VERSION 5.8 ;
BUSBITCHARS "[]" ;
DIVIDERCHAR "/" ;
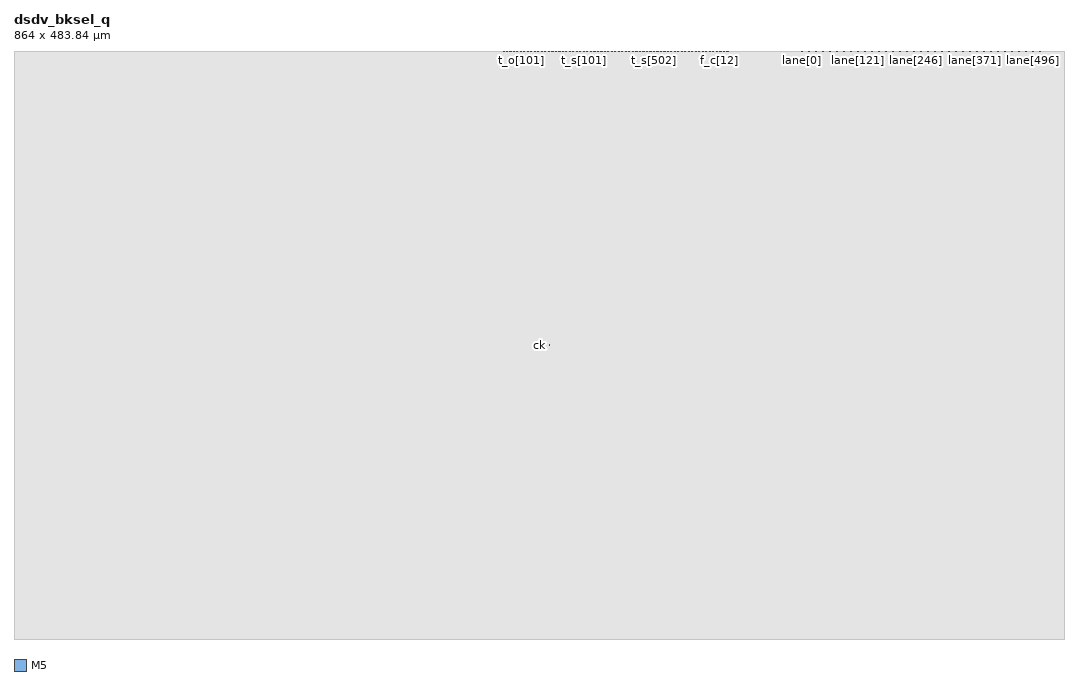
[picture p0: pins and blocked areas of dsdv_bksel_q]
MACRO dsdv_bksel_q
  CLASS BLOCK ;
  ORIGIN 0 0 ;
  SIZE 864.0 BY 483.84 ;
  PIN t_o[0]
    DIRECTION OUTPUT ;
    USE SIGNAL ;
    PORT
      LAYER M5 ;
        RECT 403.200 483.608 403.248 483.808 ;
    END
  END t_o[0]
  PIN t_o[1]
    DIRECTION OUTPUT ;
    USE SIGNAL ;
    PORT
      LAYER M5 ;
        RECT 403.344 483.608 403.392 483.808 ;
    END
  END t_o[1]
  PIN t_o[2]
    DIRECTION OUTPUT ;
    USE SIGNAL ;
    PORT
      LAYER M5 ;
        RECT 403.488 483.608 403.536 483.808 ;
    END
  END t_o[2]
  PIN t_o[3]
    DIRECTION OUTPUT ;
    USE SIGNAL ;
    PORT
      LAYER M5 ;
        RECT 403.632 483.608 403.680 483.808 ;
    END
  END t_o[3]
  PIN t_o[4]
    DIRECTION OUTPUT ;
    USE SIGNAL ;
    PORT
      LAYER M5 ;
        RECT 403.776 483.608 403.824 483.808 ;
    END
  END t_o[4]
  PIN t_o[5]
    DIRECTION OUTPUT ;
    USE SIGNAL ;
    PORT
      LAYER M5 ;
        RECT 403.920 483.608 403.968 483.808 ;
    END
  END t_o[5]
  PIN t_o[6]
    DIRECTION OUTPUT ;
    USE SIGNAL ;
    PORT
      LAYER M5 ;
        RECT 404.064 483.608 404.112 483.808 ;
    END
  END t_o[6]
  PIN t_o[7]
    DIRECTION OUTPUT ;
    USE SIGNAL ;
    PORT
      LAYER M5 ;
        RECT 404.208 483.608 404.256 483.808 ;
    END
  END t_o[7]
  PIN t_o[8]
    DIRECTION OUTPUT ;
    USE SIGNAL ;
    PORT
      LAYER M5 ;
        RECT 404.352 483.608 404.400 483.808 ;
    END
  END t_o[8]
  PIN t_o[9]
    DIRECTION OUTPUT ;
    USE SIGNAL ;
    PORT
      LAYER M5 ;
        RECT 404.496 483.608 404.544 483.808 ;
    END
  END t_o[9]
  PIN t_o[10]
    DIRECTION OUTPUT ;
    USE SIGNAL ;
    PORT
      LAYER M5 ;
        RECT 404.640 483.608 404.688 483.808 ;
    END
  END t_o[10]
  PIN t_o[11]
    DIRECTION OUTPUT ;
    USE SIGNAL ;
    PORT
      LAYER M5 ;
        RECT 404.784 483.608 404.832 483.808 ;
    END
  END t_o[11]
  PIN t_o[12]
    DIRECTION OUTPUT ;
    USE SIGNAL ;
    PORT
      LAYER M5 ;
        RECT 404.928 483.608 404.976 483.808 ;
    END
  END t_o[12]
  PIN t_o[13]
    DIRECTION OUTPUT ;
    USE SIGNAL ;
    PORT
      LAYER M5 ;
        RECT 405.072 483.608 405.120 483.808 ;
    END
  END t_o[13]
  PIN t_o[14]
    DIRECTION OUTPUT ;
    USE SIGNAL ;
    PORT
      LAYER M5 ;
        RECT 405.216 483.608 405.264 483.808 ;
    END
  END t_o[14]
  PIN t_o[15]
    DIRECTION OUTPUT ;
    USE SIGNAL ;
    PORT
      LAYER M5 ;
        RECT 405.360 483.608 405.408 483.808 ;
    END
  END t_o[15]
  PIN t_o[16]
    DIRECTION OUTPUT ;
    USE SIGNAL ;
    PORT
      LAYER M5 ;
        RECT 405.504 483.608 405.552 483.808 ;
    END
  END t_o[16]
  PIN t_o[17]
    DIRECTION OUTPUT ;
    USE SIGNAL ;
    PORT
      LAYER M5 ;
        RECT 405.648 483.608 405.696 483.808 ;
    END
  END t_o[17]
  PIN t_o[18]
    DIRECTION OUTPUT ;
    USE SIGNAL ;
    PORT
      LAYER M5 ;
        RECT 405.792 483.608 405.840 483.808 ;
    END
  END t_o[18]
  PIN t_o[19]
    DIRECTION OUTPUT ;
    USE SIGNAL ;
    PORT
      LAYER M5 ;
        RECT 405.936 483.608 405.984 483.808 ;
    END
  END t_o[19]
  PIN t_o[20]
    DIRECTION OUTPUT ;
    USE SIGNAL ;
    PORT
      LAYER M5 ;
        RECT 406.080 483.608 406.128 483.808 ;
    END
  END t_o[20]
  PIN t_o[21]
    DIRECTION OUTPUT ;
    USE SIGNAL ;
    PORT
      LAYER M5 ;
        RECT 406.224 483.608 406.272 483.808 ;
    END
  END t_o[21]
  PIN t_o[22]
    DIRECTION OUTPUT ;
    USE SIGNAL ;
    PORT
      LAYER M5 ;
        RECT 406.368 483.608 406.416 483.808 ;
    END
  END t_o[22]
  PIN t_o[23]
    DIRECTION OUTPUT ;
    USE SIGNAL ;
    PORT
      LAYER M5 ;
        RECT 406.512 483.608 406.560 483.808 ;
    END
  END t_o[23]
  PIN t_o[24]
    DIRECTION OUTPUT ;
    USE SIGNAL ;
    PORT
      LAYER M5 ;
        RECT 406.656 483.608 406.704 483.808 ;
    END
  END t_o[24]
  PIN t_o[25]
    DIRECTION OUTPUT ;
    USE SIGNAL ;
    PORT
      LAYER M5 ;
        RECT 406.800 483.608 406.848 483.808 ;
    END
  END t_o[25]
  PIN t_o[26]
    DIRECTION OUTPUT ;
    USE SIGNAL ;
    PORT
      LAYER M5 ;
        RECT 406.944 483.608 406.992 483.808 ;
    END
  END t_o[26]
  PIN t_o[27]
    DIRECTION OUTPUT ;
    USE SIGNAL ;
    PORT
      LAYER M5 ;
        RECT 407.088 483.608 407.136 483.808 ;
    END
  END t_o[27]
  PIN t_o[28]
    DIRECTION OUTPUT ;
    USE SIGNAL ;
    PORT
      LAYER M5 ;
        RECT 407.232 483.608 407.280 483.808 ;
    END
  END t_o[28]
  PIN t_o[29]
    DIRECTION OUTPUT ;
    USE SIGNAL ;
    PORT
      LAYER M5 ;
        RECT 407.376 483.608 407.424 483.808 ;
    END
  END t_o[29]
  PIN t_o[30]
    DIRECTION OUTPUT ;
    USE SIGNAL ;
    PORT
      LAYER M5 ;
        RECT 407.520 483.608 407.568 483.808 ;
    END
  END t_o[30]
  PIN t_o[31]
    DIRECTION OUTPUT ;
    USE SIGNAL ;
    PORT
      LAYER M5 ;
        RECT 407.664 483.608 407.712 483.808 ;
    END
  END t_o[31]
  PIN t_o[32]
    DIRECTION OUTPUT ;
    USE SIGNAL ;
    PORT
      LAYER M5 ;
        RECT 407.808 483.608 407.856 483.808 ;
    END
  END t_o[32]
  PIN t_o[33]
    DIRECTION OUTPUT ;
    USE SIGNAL ;
    PORT
      LAYER M5 ;
        RECT 407.952 483.608 408.000 483.808 ;
    END
  END t_o[33]
  PIN t_o[34]
    DIRECTION OUTPUT ;
    USE SIGNAL ;
    PORT
      LAYER M5 ;
        RECT 408.096 483.608 408.144 483.808 ;
    END
  END t_o[34]
  PIN t_o[35]
    DIRECTION OUTPUT ;
    USE SIGNAL ;
    PORT
      LAYER M5 ;
        RECT 408.240 483.608 408.288 483.808 ;
    END
  END t_o[35]
  PIN t_o[36]
    DIRECTION OUTPUT ;
    USE SIGNAL ;
    PORT
      LAYER M5 ;
        RECT 408.384 483.608 408.432 483.808 ;
    END
  END t_o[36]
  PIN t_o[37]
    DIRECTION OUTPUT ;
    USE SIGNAL ;
    PORT
      LAYER M5 ;
        RECT 408.528 483.608 408.576 483.808 ;
    END
  END t_o[37]
  PIN t_o[38]
    DIRECTION OUTPUT ;
    USE SIGNAL ;
    PORT
      LAYER M5 ;
        RECT 408.672 483.608 408.720 483.808 ;
    END
  END t_o[38]
  PIN t_o[39]
    DIRECTION OUTPUT ;
    USE SIGNAL ;
    PORT
      LAYER M5 ;
        RECT 408.816 483.608 408.864 483.808 ;
    END
  END t_o[39]
  PIN t_o[40]
    DIRECTION OUTPUT ;
    USE SIGNAL ;
    PORT
      LAYER M5 ;
        RECT 408.960 483.608 409.008 483.808 ;
    END
  END t_o[40]
  PIN t_o[41]
    DIRECTION OUTPUT ;
    USE SIGNAL ;
    PORT
      LAYER M5 ;
        RECT 409.104 483.608 409.152 483.808 ;
    END
  END t_o[41]
  PIN t_o[42]
    DIRECTION OUTPUT ;
    USE SIGNAL ;
    PORT
      LAYER M5 ;
        RECT 409.248 483.608 409.296 483.808 ;
    END
  END t_o[42]
  PIN t_o[43]
    DIRECTION OUTPUT ;
    USE SIGNAL ;
    PORT
      LAYER M5 ;
        RECT 409.392 483.608 409.440 483.808 ;
    END
  END t_o[43]
  PIN t_o[44]
    DIRECTION OUTPUT ;
    USE SIGNAL ;
    PORT
      LAYER M5 ;
        RECT 409.536 483.608 409.584 483.808 ;
    END
  END t_o[44]
  PIN t_o[45]
    DIRECTION OUTPUT ;
    USE SIGNAL ;
    PORT
      LAYER M5 ;
        RECT 409.680 483.608 409.728 483.808 ;
    END
  END t_o[45]
  PIN t_o[46]
    DIRECTION OUTPUT ;
    USE SIGNAL ;
    PORT
      LAYER M5 ;
        RECT 409.824 483.608 409.872 483.808 ;
    END
  END t_o[46]
  PIN t_o[47]
    DIRECTION OUTPUT ;
    USE SIGNAL ;
    PORT
      LAYER M5 ;
        RECT 409.968 483.608 410.016 483.808 ;
    END
  END t_o[47]
  PIN t_o[48]
    DIRECTION OUTPUT ;
    USE SIGNAL ;
    PORT
      LAYER M5 ;
        RECT 410.112 483.608 410.160 483.808 ;
    END
  END t_o[48]
  PIN t_o[49]
    DIRECTION OUTPUT ;
    USE SIGNAL ;
    PORT
      LAYER M5 ;
        RECT 410.256 483.608 410.304 483.808 ;
    END
  END t_o[49]
  PIN t_o[50]
    DIRECTION OUTPUT ;
    USE SIGNAL ;
    PORT
      LAYER M5 ;
        RECT 410.400 483.608 410.448 483.808 ;
    END
  END t_o[50]
  PIN t_o[51]
    DIRECTION OUTPUT ;
    USE SIGNAL ;
    PORT
      LAYER M5 ;
        RECT 410.544 483.608 410.592 483.808 ;
    END
  END t_o[51]
  PIN t_o[52]
    DIRECTION OUTPUT ;
    USE SIGNAL ;
    PORT
      LAYER M5 ;
        RECT 410.688 483.608 410.736 483.808 ;
    END
  END t_o[52]
  PIN t_o[53]
    DIRECTION OUTPUT ;
    USE SIGNAL ;
    PORT
      LAYER M5 ;
        RECT 410.832 483.608 410.880 483.808 ;
    END
  END t_o[53]
  PIN t_o[54]
    DIRECTION OUTPUT ;
    USE SIGNAL ;
    PORT
      LAYER M5 ;
        RECT 410.976 483.608 411.024 483.808 ;
    END
  END t_o[54]
  PIN t_o[55]
    DIRECTION OUTPUT ;
    USE SIGNAL ;
    PORT
      LAYER M5 ;
        RECT 411.120 483.608 411.168 483.808 ;
    END
  END t_o[55]
  PIN t_o[56]
    DIRECTION OUTPUT ;
    USE SIGNAL ;
    PORT
      LAYER M5 ;
        RECT 411.264 483.608 411.312 483.808 ;
    END
  END t_o[56]
  PIN t_o[57]
    DIRECTION OUTPUT ;
    USE SIGNAL ;
    PORT
      LAYER M5 ;
        RECT 411.408 483.608 411.456 483.808 ;
    END
  END t_o[57]
  PIN t_o[58]
    DIRECTION OUTPUT ;
    USE SIGNAL ;
    PORT
      LAYER M5 ;
        RECT 411.552 483.608 411.600 483.808 ;
    END
  END t_o[58]
  PIN t_o[59]
    DIRECTION OUTPUT ;
    USE SIGNAL ;
    PORT
      LAYER M5 ;
        RECT 411.696 483.608 411.744 483.808 ;
    END
  END t_o[59]
  PIN t_o[60]
    DIRECTION OUTPUT ;
    USE SIGNAL ;
    PORT
      LAYER M5 ;
        RECT 411.840 483.608 411.888 483.808 ;
    END
  END t_o[60]
  PIN t_o[61]
    DIRECTION OUTPUT ;
    USE SIGNAL ;
    PORT
      LAYER M5 ;
        RECT 411.984 483.608 412.032 483.808 ;
    END
  END t_o[61]
  PIN t_o[62]
    DIRECTION OUTPUT ;
    USE SIGNAL ;
    PORT
      LAYER M5 ;
        RECT 412.128 483.608 412.176 483.808 ;
    END
  END t_o[62]
  PIN t_o[63]
    DIRECTION OUTPUT ;
    USE SIGNAL ;
    PORT
      LAYER M5 ;
        RECT 412.272 483.608 412.320 483.808 ;
    END
  END t_o[63]
  PIN t_o[64]
    DIRECTION OUTPUT ;
    USE SIGNAL ;
    PORT
      LAYER M5 ;
        RECT 412.416 483.608 412.464 483.808 ;
    END
  END t_o[64]
  PIN t_o[65]
    DIRECTION OUTPUT ;
    USE SIGNAL ;
    PORT
      LAYER M5 ;
        RECT 412.560 483.608 412.608 483.808 ;
    END
  END t_o[65]
  PIN t_o[66]
    DIRECTION OUTPUT ;
    USE SIGNAL ;
    PORT
      LAYER M5 ;
        RECT 412.704 483.608 412.752 483.808 ;
    END
  END t_o[66]
  PIN t_o[67]
    DIRECTION OUTPUT ;
    USE SIGNAL ;
    PORT
      LAYER M5 ;
        RECT 412.848 483.608 412.896 483.808 ;
    END
  END t_o[67]
  PIN t_o[68]
    DIRECTION OUTPUT ;
    USE SIGNAL ;
    PORT
      LAYER M5 ;
        RECT 412.992 483.608 413.040 483.808 ;
    END
  END t_o[68]
  PIN t_o[69]
    DIRECTION OUTPUT ;
    USE SIGNAL ;
    PORT
      LAYER M5 ;
        RECT 413.136 483.608 413.184 483.808 ;
    END
  END t_o[69]
  PIN t_o[70]
    DIRECTION OUTPUT ;
    USE SIGNAL ;
    PORT
      LAYER M5 ;
        RECT 413.280 483.608 413.328 483.808 ;
    END
  END t_o[70]
  PIN t_o[71]
    DIRECTION OUTPUT ;
    USE SIGNAL ;
    PORT
      LAYER M5 ;
        RECT 413.424 483.608 413.472 483.808 ;
    END
  END t_o[71]
  PIN t_o[72]
    DIRECTION OUTPUT ;
    USE SIGNAL ;
    PORT
      LAYER M5 ;
        RECT 413.568 483.608 413.616 483.808 ;
    END
  END t_o[72]
  PIN t_o[73]
    DIRECTION OUTPUT ;
    USE SIGNAL ;
    PORT
      LAYER M5 ;
        RECT 413.712 483.608 413.760 483.808 ;
    END
  END t_o[73]
  PIN t_o[74]
    DIRECTION OUTPUT ;
    USE SIGNAL ;
    PORT
      LAYER M5 ;
        RECT 413.856 483.608 413.904 483.808 ;
    END
  END t_o[74]
  PIN t_o[75]
    DIRECTION OUTPUT ;
    USE SIGNAL ;
    PORT
      LAYER M5 ;
        RECT 414.000 483.608 414.048 483.808 ;
    END
  END t_o[75]
  PIN t_o[76]
    DIRECTION OUTPUT ;
    USE SIGNAL ;
    PORT
      LAYER M5 ;
        RECT 414.144 483.608 414.192 483.808 ;
    END
  END t_o[76]
  PIN t_o[77]
    DIRECTION OUTPUT ;
    USE SIGNAL ;
    PORT
      LAYER M5 ;
        RECT 414.288 483.608 414.336 483.808 ;
    END
  END t_o[77]
  PIN t_o[78]
    DIRECTION OUTPUT ;
    USE SIGNAL ;
    PORT
      LAYER M5 ;
        RECT 414.432 483.608 414.480 483.808 ;
    END
  END t_o[78]
  PIN t_o[79]
    DIRECTION OUTPUT ;
    USE SIGNAL ;
    PORT
      LAYER M5 ;
        RECT 414.576 483.608 414.624 483.808 ;
    END
  END t_o[79]
  PIN t_o[80]
    DIRECTION OUTPUT ;
    USE SIGNAL ;
    PORT
      LAYER M5 ;
        RECT 414.720 483.608 414.768 483.808 ;
    END
  END t_o[80]
  PIN t_o[81]
    DIRECTION OUTPUT ;
    USE SIGNAL ;
    PORT
      LAYER M5 ;
        RECT 414.864 483.608 414.912 483.808 ;
    END
  END t_o[81]
  PIN t_o[82]
    DIRECTION OUTPUT ;
    USE SIGNAL ;
    PORT
      LAYER M5 ;
        RECT 415.008 483.608 415.056 483.808 ;
    END
  END t_o[82]
  PIN t_o[83]
    DIRECTION OUTPUT ;
    USE SIGNAL ;
    PORT
      LAYER M5 ;
        RECT 415.152 483.608 415.200 483.808 ;
    END
  END t_o[83]
  PIN t_o[84]
    DIRECTION OUTPUT ;
    USE SIGNAL ;
    PORT
      LAYER M5 ;
        RECT 415.296 483.608 415.344 483.808 ;
    END
  END t_o[84]
  PIN t_o[85]
    DIRECTION OUTPUT ;
    USE SIGNAL ;
    PORT
      LAYER M5 ;
        RECT 415.440 483.608 415.488 483.808 ;
    END
  END t_o[85]
  PIN t_o[86]
    DIRECTION OUTPUT ;
    USE SIGNAL ;
    PORT
      LAYER M5 ;
        RECT 415.584 483.608 415.632 483.808 ;
    END
  END t_o[86]
  PIN t_o[87]
    DIRECTION OUTPUT ;
    USE SIGNAL ;
    PORT
      LAYER M5 ;
        RECT 415.728 483.608 415.776 483.808 ;
    END
  END t_o[87]
  PIN t_o[88]
    DIRECTION OUTPUT ;
    USE SIGNAL ;
    PORT
      LAYER M5 ;
        RECT 415.872 483.608 415.920 483.808 ;
    END
  END t_o[88]
  PIN t_o[89]
    DIRECTION OUTPUT ;
    USE SIGNAL ;
    PORT
      LAYER M5 ;
        RECT 416.016 483.608 416.064 483.808 ;
    END
  END t_o[89]
  PIN t_o[90]
    DIRECTION OUTPUT ;
    USE SIGNAL ;
    PORT
      LAYER M5 ;
        RECT 416.160 483.608 416.208 483.808 ;
    END
  END t_o[90]
  PIN t_o[91]
    DIRECTION OUTPUT ;
    USE SIGNAL ;
    PORT
      LAYER M5 ;
        RECT 416.304 483.608 416.352 483.808 ;
    END
  END t_o[91]
  PIN t_o[92]
    DIRECTION OUTPUT ;
    USE SIGNAL ;
    PORT
      LAYER M5 ;
        RECT 416.448 483.608 416.496 483.808 ;
    END
  END t_o[92]
  PIN t_o[93]
    DIRECTION OUTPUT ;
    USE SIGNAL ;
    PORT
      LAYER M5 ;
        RECT 416.592 483.608 416.640 483.808 ;
    END
  END t_o[93]
  PIN t_o[94]
    DIRECTION OUTPUT ;
    USE SIGNAL ;
    PORT
      LAYER M5 ;
        RECT 416.736 483.608 416.784 483.808 ;
    END
  END t_o[94]
  PIN t_o[95]
    DIRECTION OUTPUT ;
    USE SIGNAL ;
    PORT
      LAYER M5 ;
        RECT 416.880 483.608 416.928 483.808 ;
    END
  END t_o[95]
  PIN t_o[96]
    DIRECTION OUTPUT ;
    USE SIGNAL ;
    PORT
      LAYER M5 ;
        RECT 417.024 483.608 417.072 483.808 ;
    END
  END t_o[96]
  PIN t_o[97]
    DIRECTION OUTPUT ;
    USE SIGNAL ;
    PORT
      LAYER M5 ;
        RECT 417.168 483.608 417.216 483.808 ;
    END
  END t_o[97]
  PIN t_o[98]
    DIRECTION OUTPUT ;
    USE SIGNAL ;
    PORT
      LAYER M5 ;
        RECT 417.312 483.608 417.360 483.808 ;
    END
  END t_o[98]
  PIN t_o[99]
    DIRECTION OUTPUT ;
    USE SIGNAL ;
    PORT
      LAYER M5 ;
        RECT 417.456 483.608 417.504 483.808 ;
    END
  END t_o[99]
  PIN t_o[100]
    DIRECTION OUTPUT ;
    USE SIGNAL ;
    PORT
      LAYER M5 ;
        RECT 417.600 483.608 417.648 483.808 ;
    END
  END t_o[100]
  PIN t_o[101]
    DIRECTION OUTPUT ;
    USE SIGNAL ;
    PORT
      LAYER M5 ;
        RECT 417.744 483.608 417.792 483.808 ;
    END
  END t_o[101]
  PIN t_o[102]
    DIRECTION OUTPUT ;
    USE SIGNAL ;
    PORT
      LAYER M5 ;
        RECT 417.888 483.608 417.936 483.808 ;
    END
  END t_o[102]
  PIN t_o[103]
    DIRECTION OUTPUT ;
    USE SIGNAL ;
    PORT
      LAYER M5 ;
        RECT 418.032 483.608 418.080 483.808 ;
    END
  END t_o[103]
  PIN t_o[104]
    DIRECTION OUTPUT ;
    USE SIGNAL ;
    PORT
      LAYER M5 ;
        RECT 418.176 483.608 418.224 483.808 ;
    END
  END t_o[104]
  PIN t_o[105]
    DIRECTION OUTPUT ;
    USE SIGNAL ;
    PORT
      LAYER M5 ;
        RECT 418.320 483.608 418.368 483.808 ;
    END
  END t_o[105]
  PIN t_o[106]
    DIRECTION OUTPUT ;
    USE SIGNAL ;
    PORT
      LAYER M5 ;
        RECT 418.464 483.608 418.512 483.808 ;
    END
  END t_o[106]
  PIN t_o[107]
    DIRECTION OUTPUT ;
    USE SIGNAL ;
    PORT
      LAYER M5 ;
        RECT 418.608 483.608 418.656 483.808 ;
    END
  END t_o[107]
  PIN t_o[108]
    DIRECTION OUTPUT ;
    USE SIGNAL ;
    PORT
      LAYER M5 ;
        RECT 418.752 483.608 418.800 483.808 ;
    END
  END t_o[108]
  PIN t_o[109]
    DIRECTION OUTPUT ;
    USE SIGNAL ;
    PORT
      LAYER M5 ;
        RECT 418.896 483.608 418.944 483.808 ;
    END
  END t_o[109]
  PIN t_o[110]
    DIRECTION OUTPUT ;
    USE SIGNAL ;
    PORT
      LAYER M5 ;
        RECT 419.040 483.608 419.088 483.808 ;
    END
  END t_o[110]
  PIN t_o[111]
    DIRECTION OUTPUT ;
    USE SIGNAL ;
    PORT
      LAYER M5 ;
        RECT 419.184 483.608 419.232 483.808 ;
    END
  END t_o[111]
  PIN t_o[112]
    DIRECTION OUTPUT ;
    USE SIGNAL ;
    PORT
      LAYER M5 ;
        RECT 419.328 483.608 419.376 483.808 ;
    END
  END t_o[112]
  PIN t_o[113]
    DIRECTION OUTPUT ;
    USE SIGNAL ;
    PORT
      LAYER M5 ;
        RECT 419.472 483.608 419.520 483.808 ;
    END
  END t_o[113]
  PIN t_o[114]
    DIRECTION OUTPUT ;
    USE SIGNAL ;
    PORT
      LAYER M5 ;
        RECT 419.616 483.608 419.664 483.808 ;
    END
  END t_o[114]
  PIN t_o[115]
    DIRECTION OUTPUT ;
    USE SIGNAL ;
    PORT
      LAYER M5 ;
        RECT 419.760 483.608 419.808 483.808 ;
    END
  END t_o[115]
  PIN t_o[116]
    DIRECTION OUTPUT ;
    USE SIGNAL ;
    PORT
      LAYER M5 ;
        RECT 419.904 483.608 419.952 483.808 ;
    END
  END t_o[116]
  PIN t_o[117]
    DIRECTION OUTPUT ;
    USE SIGNAL ;
    PORT
      LAYER M5 ;
        RECT 420.048 483.608 420.096 483.808 ;
    END
  END t_o[117]
  PIN t_o[118]
    DIRECTION OUTPUT ;
    USE SIGNAL ;
    PORT
      LAYER M5 ;
        RECT 420.192 483.608 420.240 483.808 ;
    END
  END t_o[118]
  PIN t_o[119]
    DIRECTION OUTPUT ;
    USE SIGNAL ;
    PORT
      LAYER M5 ;
        RECT 420.336 483.608 420.384 483.808 ;
    END
  END t_o[119]
  PIN t_o[120]
    DIRECTION OUTPUT ;
    USE SIGNAL ;
    PORT
      LAYER M5 ;
        RECT 420.480 483.608 420.528 483.808 ;
    END
  END t_o[120]
  PIN t_o[121]
    DIRECTION OUTPUT ;
    USE SIGNAL ;
    PORT
      LAYER M5 ;
        RECT 420.624 483.608 420.672 483.808 ;
    END
  END t_o[121]
  PIN t_o[122]
    DIRECTION OUTPUT ;
    USE SIGNAL ;
    PORT
      LAYER M5 ;
        RECT 420.768 483.608 420.816 483.808 ;
    END
  END t_o[122]
  PIN t_o[123]
    DIRECTION OUTPUT ;
    USE SIGNAL ;
    PORT
      LAYER M5 ;
        RECT 420.912 483.608 420.960 483.808 ;
    END
  END t_o[123]
  PIN t_o[124]
    DIRECTION OUTPUT ;
    USE SIGNAL ;
    PORT
      LAYER M5 ;
        RECT 421.056 483.608 421.104 483.808 ;
    END
  END t_o[124]
  PIN t_o[125]
    DIRECTION OUTPUT ;
    USE SIGNAL ;
    PORT
      LAYER M5 ;
        RECT 421.200 483.608 421.248 483.808 ;
    END
  END t_o[125]
  PIN t_o[126]
    DIRECTION OUTPUT ;
    USE SIGNAL ;
    PORT
      LAYER M5 ;
        RECT 421.344 483.608 421.392 483.808 ;
    END
  END t_o[126]
  PIN t_o[127]
    DIRECTION OUTPUT ;
    USE SIGNAL ;
    PORT
      LAYER M5 ;
        RECT 421.488 483.608 421.536 483.808 ;
    END
  END t_o[127]
  PIN t_o[128]
    DIRECTION OUTPUT ;
    USE SIGNAL ;
    PORT
      LAYER M5 ;
        RECT 421.632 483.608 421.680 483.808 ;
    END
  END t_o[128]
  PIN t_o[129]
    DIRECTION OUTPUT ;
    USE SIGNAL ;
    PORT
      LAYER M5 ;
        RECT 421.776 483.608 421.824 483.808 ;
    END
  END t_o[129]
  PIN t_o[130]
    DIRECTION OUTPUT ;
    USE SIGNAL ;
    PORT
      LAYER M5 ;
        RECT 421.920 483.608 421.968 483.808 ;
    END
  END t_o[130]
  PIN t_o[131]
    DIRECTION OUTPUT ;
    USE SIGNAL ;
    PORT
      LAYER M5 ;
        RECT 422.064 483.608 422.112 483.808 ;
    END
  END t_o[131]
  PIN t_o[132]
    DIRECTION OUTPUT ;
    USE SIGNAL ;
    PORT
      LAYER M5 ;
        RECT 422.208 483.608 422.256 483.808 ;
    END
  END t_o[132]
  PIN t_o[133]
    DIRECTION OUTPUT ;
    USE SIGNAL ;
    PORT
      LAYER M5 ;
        RECT 422.352 483.608 422.400 483.808 ;
    END
  END t_o[133]
  PIN t_o[134]
    DIRECTION OUTPUT ;
    USE SIGNAL ;
    PORT
      LAYER M5 ;
        RECT 422.496 483.608 422.544 483.808 ;
    END
  END t_o[134]
  PIN t_o[135]
    DIRECTION OUTPUT ;
    USE SIGNAL ;
    PORT
      LAYER M5 ;
        RECT 422.640 483.608 422.688 483.808 ;
    END
  END t_o[135]
  PIN t_o[136]
    DIRECTION OUTPUT ;
    USE SIGNAL ;
    PORT
      LAYER M5 ;
        RECT 422.784 483.608 422.832 483.808 ;
    END
  END t_o[136]
  PIN t_o[137]
    DIRECTION OUTPUT ;
    USE SIGNAL ;
    PORT
      LAYER M5 ;
        RECT 422.928 483.608 422.976 483.808 ;
    END
  END t_o[137]
  PIN t_o[138]
    DIRECTION OUTPUT ;
    USE SIGNAL ;
    PORT
      LAYER M5 ;
        RECT 423.072 483.608 423.120 483.808 ;
    END
  END t_o[138]
  PIN t_o[139]
    DIRECTION OUTPUT ;
    USE SIGNAL ;
    PORT
      LAYER M5 ;
        RECT 423.216 483.608 423.264 483.808 ;
    END
  END t_o[139]
  PIN t_o[140]
    DIRECTION OUTPUT ;
    USE SIGNAL ;
    PORT
      LAYER M5 ;
        RECT 423.360 483.608 423.408 483.808 ;
    END
  END t_o[140]
  PIN t_o[141]
    DIRECTION OUTPUT ;
    USE SIGNAL ;
    PORT
      LAYER M5 ;
        RECT 423.504 483.608 423.552 483.808 ;
    END
  END t_o[141]
  PIN t_o[142]
    DIRECTION OUTPUT ;
    USE SIGNAL ;
    PORT
      LAYER M5 ;
        RECT 423.648 483.608 423.696 483.808 ;
    END
  END t_o[142]
  PIN t_o[143]
    DIRECTION OUTPUT ;
    USE SIGNAL ;
    PORT
      LAYER M5 ;
        RECT 423.792 483.608 423.840 483.808 ;
    END
  END t_o[143]
  PIN t_o[144]
    DIRECTION OUTPUT ;
    USE SIGNAL ;
    PORT
      LAYER M5 ;
        RECT 423.936 483.608 423.984 483.808 ;
    END
  END t_o[144]
  PIN t_o[145]
    DIRECTION OUTPUT ;
    USE SIGNAL ;
    PORT
      LAYER M5 ;
        RECT 424.080 483.608 424.128 483.808 ;
    END
  END t_o[145]
  PIN t_o[146]
    DIRECTION OUTPUT ;
    USE SIGNAL ;
    PORT
      LAYER M5 ;
        RECT 424.224 483.608 424.272 483.808 ;
    END
  END t_o[146]
  PIN t_o[147]
    DIRECTION OUTPUT ;
    USE SIGNAL ;
    PORT
      LAYER M5 ;
        RECT 424.368 483.608 424.416 483.808 ;
    END
  END t_o[147]
  PIN t_o[148]
    DIRECTION OUTPUT ;
    USE SIGNAL ;
    PORT
      LAYER M5 ;
        RECT 424.512 483.608 424.560 483.808 ;
    END
  END t_o[148]
  PIN t_o[149]
    DIRECTION OUTPUT ;
    USE SIGNAL ;
    PORT
      LAYER M5 ;
        RECT 424.656 483.608 424.704 483.808 ;
    END
  END t_o[149]
  PIN t_o[150]
    DIRECTION OUTPUT ;
    USE SIGNAL ;
    PORT
      LAYER M5 ;
        RECT 424.800 483.608 424.848 483.808 ;
    END
  END t_o[150]
  PIN t_o[151]
    DIRECTION OUTPUT ;
    USE SIGNAL ;
    PORT
      LAYER M5 ;
        RECT 424.944 483.608 424.992 483.808 ;
    END
  END t_o[151]
  PIN t_o[152]
    DIRECTION OUTPUT ;
    USE SIGNAL ;
    PORT
      LAYER M5 ;
        RECT 425.088 483.608 425.136 483.808 ;
    END
  END t_o[152]
  PIN t_o[153]
    DIRECTION OUTPUT ;
    USE SIGNAL ;
    PORT
      LAYER M5 ;
        RECT 425.232 483.608 425.280 483.808 ;
    END
  END t_o[153]
  PIN t_o[154]
    DIRECTION OUTPUT ;
    USE SIGNAL ;
    PORT
      LAYER M5 ;
        RECT 425.376 483.608 425.424 483.808 ;
    END
  END t_o[154]
  PIN t_o[155]
    DIRECTION OUTPUT ;
    USE SIGNAL ;
    PORT
      LAYER M5 ;
        RECT 425.520 483.608 425.568 483.808 ;
    END
  END t_o[155]
  PIN t_o[156]
    DIRECTION OUTPUT ;
    USE SIGNAL ;
    PORT
      LAYER M5 ;
        RECT 425.664 483.608 425.712 483.808 ;
    END
  END t_o[156]
  PIN t_o[157]
    DIRECTION OUTPUT ;
    USE SIGNAL ;
    PORT
      LAYER M5 ;
        RECT 425.808 483.608 425.856 483.808 ;
    END
  END t_o[157]
  PIN t_o[158]
    DIRECTION OUTPUT ;
    USE SIGNAL ;
    PORT
      LAYER M5 ;
        RECT 425.952 483.608 426.000 483.808 ;
    END
  END t_o[158]
  PIN t_o[159]
    DIRECTION OUTPUT ;
    USE SIGNAL ;
    PORT
      LAYER M5 ;
        RECT 426.096 483.608 426.144 483.808 ;
    END
  END t_o[159]
  PIN t_o[160]
    DIRECTION OUTPUT ;
    USE SIGNAL ;
    PORT
      LAYER M5 ;
        RECT 426.240 483.608 426.288 483.808 ;
    END
  END t_o[160]
  PIN t_o[161]
    DIRECTION OUTPUT ;
    USE SIGNAL ;
    PORT
      LAYER M5 ;
        RECT 426.384 483.608 426.432 483.808 ;
    END
  END t_o[161]
  PIN t_o[162]
    DIRECTION OUTPUT ;
    USE SIGNAL ;
    PORT
      LAYER M5 ;
        RECT 426.528 483.608 426.576 483.808 ;
    END
  END t_o[162]
  PIN t_o[163]
    DIRECTION OUTPUT ;
    USE SIGNAL ;
    PORT
      LAYER M5 ;
        RECT 426.672 483.608 426.720 483.808 ;
    END
  END t_o[163]
  PIN t_o[164]
    DIRECTION OUTPUT ;
    USE SIGNAL ;
    PORT
      LAYER M5 ;
        RECT 426.816 483.608 426.864 483.808 ;
    END
  END t_o[164]
  PIN t_o[165]
    DIRECTION OUTPUT ;
    USE SIGNAL ;
    PORT
      LAYER M5 ;
        RECT 426.960 483.608 427.008 483.808 ;
    END
  END t_o[165]
  PIN t_o[166]
    DIRECTION OUTPUT ;
    USE SIGNAL ;
    PORT
      LAYER M5 ;
        RECT 427.104 483.608 427.152 483.808 ;
    END
  END t_o[166]
  PIN t_o[167]
    DIRECTION OUTPUT ;
    USE SIGNAL ;
    PORT
      LAYER M5 ;
        RECT 427.248 483.608 427.296 483.808 ;
    END
  END t_o[167]
  PIN t_o[168]
    DIRECTION OUTPUT ;
    USE SIGNAL ;
    PORT
      LAYER M5 ;
        RECT 427.392 483.608 427.440 483.808 ;
    END
  END t_o[168]
  PIN t_o[169]
    DIRECTION OUTPUT ;
    USE SIGNAL ;
    PORT
      LAYER M5 ;
        RECT 427.536 483.608 427.584 483.808 ;
    END
  END t_o[169]
  PIN t_o[170]
    DIRECTION OUTPUT ;
    USE SIGNAL ;
    PORT
      LAYER M5 ;
        RECT 427.680 483.608 427.728 483.808 ;
    END
  END t_o[170]
  PIN t_o[171]
    DIRECTION OUTPUT ;
    USE SIGNAL ;
    PORT
      LAYER M5 ;
        RECT 427.824 483.608 427.872 483.808 ;
    END
  END t_o[171]
  PIN t_o[172]
    DIRECTION OUTPUT ;
    USE SIGNAL ;
    PORT
      LAYER M5 ;
        RECT 427.968 483.608 428.016 483.808 ;
    END
  END t_o[172]
  PIN t_o[173]
    DIRECTION OUTPUT ;
    USE SIGNAL ;
    PORT
      LAYER M5 ;
        RECT 428.112 483.608 428.160 483.808 ;
    END
  END t_o[173]
  PIN t_o[174]
    DIRECTION OUTPUT ;
    USE SIGNAL ;
    PORT
      LAYER M5 ;
        RECT 428.256 483.608 428.304 483.808 ;
    END
  END t_o[174]
  PIN t_o[175]
    DIRECTION OUTPUT ;
    USE SIGNAL ;
    PORT
      LAYER M5 ;
        RECT 428.400 483.608 428.448 483.808 ;
    END
  END t_o[175]
  PIN t_o[176]
    DIRECTION OUTPUT ;
    USE SIGNAL ;
    PORT
      LAYER M5 ;
        RECT 428.544 483.608 428.592 483.808 ;
    END
  END t_o[176]
  PIN t_o[177]
    DIRECTION OUTPUT ;
    USE SIGNAL ;
    PORT
      LAYER M5 ;
        RECT 428.688 483.608 428.736 483.808 ;
    END
  END t_o[177]
  PIN t_o[178]
    DIRECTION OUTPUT ;
    USE SIGNAL ;
    PORT
      LAYER M5 ;
        RECT 428.832 483.608 428.880 483.808 ;
    END
  END t_o[178]
  PIN t_o[179]
    DIRECTION OUTPUT ;
    USE SIGNAL ;
    PORT
      LAYER M5 ;
        RECT 428.976 483.608 429.024 483.808 ;
    END
  END t_o[179]
  PIN t_o[180]
    DIRECTION OUTPUT ;
    USE SIGNAL ;
    PORT
      LAYER M5 ;
        RECT 429.120 483.608 429.168 483.808 ;
    END
  END t_o[180]
  PIN t_o[181]
    DIRECTION OUTPUT ;
    USE SIGNAL ;
    PORT
      LAYER M5 ;
        RECT 429.264 483.608 429.312 483.808 ;
    END
  END t_o[181]
  PIN t_o[182]
    DIRECTION OUTPUT ;
    USE SIGNAL ;
    PORT
      LAYER M5 ;
        RECT 429.408 483.608 429.456 483.808 ;
    END
  END t_o[182]
  PIN t_o[183]
    DIRECTION OUTPUT ;
    USE SIGNAL ;
    PORT
      LAYER M5 ;
        RECT 429.552 483.608 429.600 483.808 ;
    END
  END t_o[183]
  PIN t_o[184]
    DIRECTION OUTPUT ;
    USE SIGNAL ;
    PORT
      LAYER M5 ;
        RECT 429.696 483.608 429.744 483.808 ;
    END
  END t_o[184]
  PIN t_o[185]
    DIRECTION OUTPUT ;
    USE SIGNAL ;
    PORT
      LAYER M5 ;
        RECT 429.840 483.608 429.888 483.808 ;
    END
  END t_o[185]
  PIN t_o[186]
    DIRECTION OUTPUT ;
    USE SIGNAL ;
    PORT
      LAYER M5 ;
        RECT 429.984 483.608 430.032 483.808 ;
    END
  END t_o[186]
  PIN t_o[187]
    DIRECTION OUTPUT ;
    USE SIGNAL ;
    PORT
      LAYER M5 ;
        RECT 430.128 483.608 430.176 483.808 ;
    END
  END t_o[187]
  PIN t_o[188]
    DIRECTION OUTPUT ;
    USE SIGNAL ;
    PORT
      LAYER M5 ;
        RECT 430.272 483.608 430.320 483.808 ;
    END
  END t_o[188]
  PIN t_o[189]
    DIRECTION OUTPUT ;
    USE SIGNAL ;
    PORT
      LAYER M5 ;
        RECT 430.416 483.608 430.464 483.808 ;
    END
  END t_o[189]
  PIN t_o[190]
    DIRECTION OUTPUT ;
    USE SIGNAL ;
    PORT
      LAYER M5 ;
        RECT 430.560 483.608 430.608 483.808 ;
    END
  END t_o[190]
  PIN t_o[191]
    DIRECTION OUTPUT ;
    USE SIGNAL ;
    PORT
      LAYER M5 ;
        RECT 430.704 483.608 430.752 483.808 ;
    END
  END t_o[191]
  PIN t_o[192]
    DIRECTION OUTPUT ;
    USE SIGNAL ;
    PORT
      LAYER M5 ;
        RECT 430.848 483.608 430.896 483.808 ;
    END
  END t_o[192]
  PIN t_o[193]
    DIRECTION OUTPUT ;
    USE SIGNAL ;
    PORT
      LAYER M5 ;
        RECT 430.992 483.608 431.040 483.808 ;
    END
  END t_o[193]
  PIN t_o[194]
    DIRECTION OUTPUT ;
    USE SIGNAL ;
    PORT
      LAYER M5 ;
        RECT 431.136 483.608 431.184 483.808 ;
    END
  END t_o[194]
  PIN t_o[195]
    DIRECTION OUTPUT ;
    USE SIGNAL ;
    PORT
      LAYER M5 ;
        RECT 431.280 483.608 431.328 483.808 ;
    END
  END t_o[195]
  PIN t_o[196]
    DIRECTION OUTPUT ;
    USE SIGNAL ;
    PORT
      LAYER M5 ;
        RECT 431.424 483.608 431.472 483.808 ;
    END
  END t_o[196]
  PIN t_o[197]
    DIRECTION OUTPUT ;
    USE SIGNAL ;
    PORT
      LAYER M5 ;
        RECT 431.568 483.608 431.616 483.808 ;
    END
  END t_o[197]
  PIN t_o[198]
    DIRECTION OUTPUT ;
    USE SIGNAL ;
    PORT
      LAYER M5 ;
        RECT 431.712 483.608 431.760 483.808 ;
    END
  END t_o[198]
  PIN t_o[199]
    DIRECTION OUTPUT ;
    USE SIGNAL ;
    PORT
      LAYER M5 ;
        RECT 431.856 483.608 431.904 483.808 ;
    END
  END t_o[199]
  PIN t_o[200]
    DIRECTION OUTPUT ;
    USE SIGNAL ;
    PORT
      LAYER M5 ;
        RECT 432.000 483.608 432.048 483.808 ;
    END
  END t_o[200]
  PIN t_o[201]
    DIRECTION OUTPUT ;
    USE SIGNAL ;
    PORT
      LAYER M5 ;
        RECT 432.144 483.608 432.192 483.808 ;
    END
  END t_o[201]
  PIN t_o[202]
    DIRECTION OUTPUT ;
    USE SIGNAL ;
    PORT
      LAYER M5 ;
        RECT 432.288 483.608 432.336 483.808 ;
    END
  END t_o[202]
  PIN t_o[203]
    DIRECTION OUTPUT ;
    USE SIGNAL ;
    PORT
      LAYER M5 ;
        RECT 432.432 483.608 432.480 483.808 ;
    END
  END t_o[203]
  PIN t_o[204]
    DIRECTION OUTPUT ;
    USE SIGNAL ;
    PORT
      LAYER M5 ;
        RECT 432.576 483.608 432.624 483.808 ;
    END
  END t_o[204]
  PIN t_o[205]
    DIRECTION OUTPUT ;
    USE SIGNAL ;
    PORT
      LAYER M5 ;
        RECT 432.720 483.608 432.768 483.808 ;
    END
  END t_o[205]
  PIN t_o[206]
    DIRECTION OUTPUT ;
    USE SIGNAL ;
    PORT
      LAYER M5 ;
        RECT 432.864 483.608 432.912 483.808 ;
    END
  END t_o[206]
  PIN t_o[207]
    DIRECTION OUTPUT ;
    USE SIGNAL ;
    PORT
      LAYER M5 ;
        RECT 433.008 483.608 433.056 483.808 ;
    END
  END t_o[207]
  PIN t_o[208]
    DIRECTION OUTPUT ;
    USE SIGNAL ;
    PORT
      LAYER M5 ;
        RECT 433.152 483.608 433.200 483.808 ;
    END
  END t_o[208]
  PIN t_o[209]
    DIRECTION OUTPUT ;
    USE SIGNAL ;
    PORT
      LAYER M5 ;
        RECT 433.296 483.608 433.344 483.808 ;
    END
  END t_o[209]
  PIN t_o[210]
    DIRECTION OUTPUT ;
    USE SIGNAL ;
    PORT
      LAYER M5 ;
        RECT 433.440 483.608 433.488 483.808 ;
    END
  END t_o[210]
  PIN t_o[211]
    DIRECTION OUTPUT ;
    USE SIGNAL ;
    PORT
      LAYER M5 ;
        RECT 433.584 483.608 433.632 483.808 ;
    END
  END t_o[211]
  PIN t_o[212]
    DIRECTION OUTPUT ;
    USE SIGNAL ;
    PORT
      LAYER M5 ;
        RECT 433.728 483.608 433.776 483.808 ;
    END
  END t_o[212]
  PIN t_o[213]
    DIRECTION OUTPUT ;
    USE SIGNAL ;
    PORT
      LAYER M5 ;
        RECT 433.872 483.608 433.920 483.808 ;
    END
  END t_o[213]
  PIN t_o[214]
    DIRECTION OUTPUT ;
    USE SIGNAL ;
    PORT
      LAYER M5 ;
        RECT 434.016 483.608 434.064 483.808 ;
    END
  END t_o[214]
  PIN t_o[215]
    DIRECTION OUTPUT ;
    USE SIGNAL ;
    PORT
      LAYER M5 ;
        RECT 434.160 483.608 434.208 483.808 ;
    END
  END t_o[215]
  PIN t_o[216]
    DIRECTION OUTPUT ;
    USE SIGNAL ;
    PORT
      LAYER M5 ;
        RECT 434.304 483.608 434.352 483.808 ;
    END
  END t_o[216]
  PIN t_o[217]
    DIRECTION OUTPUT ;
    USE SIGNAL ;
    PORT
      LAYER M5 ;
        RECT 434.448 483.608 434.496 483.808 ;
    END
  END t_o[217]
  PIN t_o[218]
    DIRECTION OUTPUT ;
    USE SIGNAL ;
    PORT
      LAYER M5 ;
        RECT 434.592 483.608 434.640 483.808 ;
    END
  END t_o[218]
  PIN t_o[219]
    DIRECTION OUTPUT ;
    USE SIGNAL ;
    PORT
      LAYER M5 ;
        RECT 434.736 483.608 434.784 483.808 ;
    END
  END t_o[219]
  PIN t_o[220]
    DIRECTION OUTPUT ;
    USE SIGNAL ;
    PORT
      LAYER M5 ;
        RECT 434.880 483.608 434.928 483.808 ;
    END
  END t_o[220]
  PIN t_o[221]
    DIRECTION OUTPUT ;
    USE SIGNAL ;
    PORT
      LAYER M5 ;
        RECT 435.024 483.608 435.072 483.808 ;
    END
  END t_o[221]
  PIN t_o[222]
    DIRECTION OUTPUT ;
    USE SIGNAL ;
    PORT
      LAYER M5 ;
        RECT 435.168 483.608 435.216 483.808 ;
    END
  END t_o[222]
  PIN t_o[223]
    DIRECTION OUTPUT ;
    USE SIGNAL ;
    PORT
      LAYER M5 ;
        RECT 435.312 483.608 435.360 483.808 ;
    END
  END t_o[223]
  PIN t_o[224]
    DIRECTION OUTPUT ;
    USE SIGNAL ;
    PORT
      LAYER M5 ;
        RECT 435.456 483.608 435.504 483.808 ;
    END
  END t_o[224]
  PIN t_o[225]
    DIRECTION OUTPUT ;
    USE SIGNAL ;
    PORT
      LAYER M5 ;
        RECT 435.600 483.608 435.648 483.808 ;
    END
  END t_o[225]
  PIN t_o[226]
    DIRECTION OUTPUT ;
    USE SIGNAL ;
    PORT
      LAYER M5 ;
        RECT 435.744 483.608 435.792 483.808 ;
    END
  END t_o[226]
  PIN t_o[227]
    DIRECTION OUTPUT ;
    USE SIGNAL ;
    PORT
      LAYER M5 ;
        RECT 435.888 483.608 435.936 483.808 ;
    END
  END t_o[227]
  PIN t_o[228]
    DIRECTION OUTPUT ;
    USE SIGNAL ;
    PORT
      LAYER M5 ;
        RECT 436.032 483.608 436.080 483.808 ;
    END
  END t_o[228]
  PIN t_o[229]
    DIRECTION OUTPUT ;
    USE SIGNAL ;
    PORT
      LAYER M5 ;
        RECT 436.176 483.608 436.224 483.808 ;
    END
  END t_o[229]
  PIN t_o[230]
    DIRECTION OUTPUT ;
    USE SIGNAL ;
    PORT
      LAYER M5 ;
        RECT 436.320 483.608 436.368 483.808 ;
    END
  END t_o[230]
  PIN t_o[231]
    DIRECTION OUTPUT ;
    USE SIGNAL ;
    PORT
      LAYER M5 ;
        RECT 436.464 483.608 436.512 483.808 ;
    END
  END t_o[231]
  PIN t_o[232]
    DIRECTION OUTPUT ;
    USE SIGNAL ;
    PORT
      LAYER M5 ;
        RECT 436.608 483.608 436.656 483.808 ;
    END
  END t_o[232]
  PIN t_o[233]
    DIRECTION OUTPUT ;
    USE SIGNAL ;
    PORT
      LAYER M5 ;
        RECT 436.752 483.608 436.800 483.808 ;
    END
  END t_o[233]
  PIN t_o[234]
    DIRECTION OUTPUT ;
    USE SIGNAL ;
    PORT
      LAYER M5 ;
        RECT 436.896 483.608 436.944 483.808 ;
    END
  END t_o[234]
  PIN t_o[235]
    DIRECTION OUTPUT ;
    USE SIGNAL ;
    PORT
      LAYER M5 ;
        RECT 437.040 483.608 437.088 483.808 ;
    END
  END t_o[235]
  PIN t_o[236]
    DIRECTION OUTPUT ;
    USE SIGNAL ;
    PORT
      LAYER M5 ;
        RECT 437.184 483.608 437.232 483.808 ;
    END
  END t_o[236]
  PIN t_o[237]
    DIRECTION OUTPUT ;
    USE SIGNAL ;
    PORT
      LAYER M5 ;
        RECT 437.328 483.608 437.376 483.808 ;
    END
  END t_o[237]
  PIN t_o[238]
    DIRECTION OUTPUT ;
    USE SIGNAL ;
    PORT
      LAYER M5 ;
        RECT 437.472 483.608 437.520 483.808 ;
    END
  END t_o[238]
  PIN t_o[239]
    DIRECTION OUTPUT ;
    USE SIGNAL ;
    PORT
      LAYER M5 ;
        RECT 437.616 483.608 437.664 483.808 ;
    END
  END t_o[239]
  PIN t_o[240]
    DIRECTION OUTPUT ;
    USE SIGNAL ;
    PORT
      LAYER M5 ;
        RECT 437.760 483.608 437.808 483.808 ;
    END
  END t_o[240]
  PIN t_o[241]
    DIRECTION OUTPUT ;
    USE SIGNAL ;
    PORT
      LAYER M5 ;
        RECT 437.904 483.608 437.952 483.808 ;
    END
  END t_o[241]
  PIN t_o[242]
    DIRECTION OUTPUT ;
    USE SIGNAL ;
    PORT
      LAYER M5 ;
        RECT 438.048 483.608 438.096 483.808 ;
    END
  END t_o[242]
  PIN t_o[243]
    DIRECTION OUTPUT ;
    USE SIGNAL ;
    PORT
      LAYER M5 ;
        RECT 438.192 483.608 438.240 483.808 ;
    END
  END t_o[243]
  PIN t_o[244]
    DIRECTION OUTPUT ;
    USE SIGNAL ;
    PORT
      LAYER M5 ;
        RECT 438.336 483.608 438.384 483.808 ;
    END
  END t_o[244]
  PIN t_o[245]
    DIRECTION OUTPUT ;
    USE SIGNAL ;
    PORT
      LAYER M5 ;
        RECT 438.480 483.608 438.528 483.808 ;
    END
  END t_o[245]
  PIN t_o[246]
    DIRECTION OUTPUT ;
    USE SIGNAL ;
    PORT
      LAYER M5 ;
        RECT 438.624 483.608 438.672 483.808 ;
    END
  END t_o[246]
  PIN t_o[247]
    DIRECTION OUTPUT ;
    USE SIGNAL ;
    PORT
      LAYER M5 ;
        RECT 438.768 483.608 438.816 483.808 ;
    END
  END t_o[247]
  PIN t_o[248]
    DIRECTION OUTPUT ;
    USE SIGNAL ;
    PORT
      LAYER M5 ;
        RECT 438.912 483.608 438.960 483.808 ;
    END
  END t_o[248]
  PIN t_o[249]
    DIRECTION OUTPUT ;
    USE SIGNAL ;
    PORT
      LAYER M5 ;
        RECT 439.056 483.608 439.104 483.808 ;
    END
  END t_o[249]
  PIN t_o[250]
    DIRECTION OUTPUT ;
    USE SIGNAL ;
    PORT
      LAYER M5 ;
        RECT 439.200 483.608 439.248 483.808 ;
    END
  END t_o[250]
  PIN t_o[251]
    DIRECTION OUTPUT ;
    USE SIGNAL ;
    PORT
      LAYER M5 ;
        RECT 439.344 483.608 439.392 483.808 ;
    END
  END t_o[251]
  PIN t_o[252]
    DIRECTION OUTPUT ;
    USE SIGNAL ;
    PORT
      LAYER M5 ;
        RECT 439.488 483.608 439.536 483.808 ;
    END
  END t_o[252]
  PIN t_o[253]
    DIRECTION OUTPUT ;
    USE SIGNAL ;
    PORT
      LAYER M5 ;
        RECT 439.632 483.608 439.680 483.808 ;
    END
  END t_o[253]
  PIN t_o[254]
    DIRECTION OUTPUT ;
    USE SIGNAL ;
    PORT
      LAYER M5 ;
        RECT 439.776 483.608 439.824 483.808 ;
    END
  END t_o[254]
  PIN t_o[255]
    DIRECTION OUTPUT ;
    USE SIGNAL ;
    PORT
      LAYER M5 ;
        RECT 439.920 483.608 439.968 483.808 ;
    END
  END t_o[255]
  PIN t_o[256]
    DIRECTION OUTPUT ;
    USE SIGNAL ;
    PORT
      LAYER M5 ;
        RECT 440.064 483.608 440.112 483.808 ;
    END
  END t_o[256]
  PIN t_o[257]
    DIRECTION OUTPUT ;
    USE SIGNAL ;
    PORT
      LAYER M5 ;
        RECT 440.208 483.608 440.256 483.808 ;
    END
  END t_o[257]
  PIN t_o[258]
    DIRECTION OUTPUT ;
    USE SIGNAL ;
    PORT
      LAYER M5 ;
        RECT 440.352 483.608 440.400 483.808 ;
    END
  END t_o[258]
  PIN t_o[259]
    DIRECTION OUTPUT ;
    USE SIGNAL ;
    PORT
      LAYER M5 ;
        RECT 440.496 483.608 440.544 483.808 ;
    END
  END t_o[259]
  PIN t_o[260]
    DIRECTION OUTPUT ;
    USE SIGNAL ;
    PORT
      LAYER M5 ;
        RECT 440.640 483.608 440.688 483.808 ;
    END
  END t_o[260]
  PIN t_o[261]
    DIRECTION OUTPUT ;
    USE SIGNAL ;
    PORT
      LAYER M5 ;
        RECT 440.784 483.608 440.832 483.808 ;
    END
  END t_o[261]
  PIN t_o[262]
    DIRECTION OUTPUT ;
    USE SIGNAL ;
    PORT
      LAYER M5 ;
        RECT 440.928 483.608 440.976 483.808 ;
    END
  END t_o[262]
  PIN t_o[263]
    DIRECTION OUTPUT ;
    USE SIGNAL ;
    PORT
      LAYER M5 ;
        RECT 441.072 483.608 441.120 483.808 ;
    END
  END t_o[263]
  PIN t_o[264]
    DIRECTION OUTPUT ;
    USE SIGNAL ;
    PORT
      LAYER M5 ;
        RECT 441.216 483.608 441.264 483.808 ;
    END
  END t_o[264]
  PIN t_o[265]
    DIRECTION OUTPUT ;
    USE SIGNAL ;
    PORT
      LAYER M5 ;
        RECT 441.360 483.608 441.408 483.808 ;
    END
  END t_o[265]
  PIN t_o[266]
    DIRECTION OUTPUT ;
    USE SIGNAL ;
    PORT
      LAYER M5 ;
        RECT 441.504 483.608 441.552 483.808 ;
    END
  END t_o[266]
  PIN t_o[267]
    DIRECTION OUTPUT ;
    USE SIGNAL ;
    PORT
      LAYER M5 ;
        RECT 441.648 483.608 441.696 483.808 ;
    END
  END t_o[267]
  PIN t_o[268]
    DIRECTION OUTPUT ;
    USE SIGNAL ;
    PORT
      LAYER M5 ;
        RECT 441.792 483.608 441.840 483.808 ;
    END
  END t_o[268]
  PIN t_o[269]
    DIRECTION OUTPUT ;
    USE SIGNAL ;
    PORT
      LAYER M5 ;
        RECT 441.936 483.608 441.984 483.808 ;
    END
  END t_o[269]
  PIN t_o[270]
    DIRECTION OUTPUT ;
    USE SIGNAL ;
    PORT
      LAYER M5 ;
        RECT 442.080 483.608 442.128 483.808 ;
    END
  END t_o[270]
  PIN t_o[271]
    DIRECTION OUTPUT ;
    USE SIGNAL ;
    PORT
      LAYER M5 ;
        RECT 442.224 483.608 442.272 483.808 ;
    END
  END t_o[271]
  PIN t_o[272]
    DIRECTION OUTPUT ;
    USE SIGNAL ;
    PORT
      LAYER M5 ;
        RECT 442.368 483.608 442.416 483.808 ;
    END
  END t_o[272]
  PIN t_o[273]
    DIRECTION OUTPUT ;
    USE SIGNAL ;
    PORT
      LAYER M5 ;
        RECT 442.512 483.608 442.560 483.808 ;
    END
  END t_o[273]
  PIN t_o[274]
    DIRECTION OUTPUT ;
    USE SIGNAL ;
    PORT
      LAYER M5 ;
        RECT 442.656 483.608 442.704 483.808 ;
    END
  END t_o[274]
  PIN t_o[275]
    DIRECTION OUTPUT ;
    USE SIGNAL ;
    PORT
      LAYER M5 ;
        RECT 442.800 483.608 442.848 483.808 ;
    END
  END t_o[275]
  PIN t_o[276]
    DIRECTION OUTPUT ;
    USE SIGNAL ;
    PORT
      LAYER M5 ;
        RECT 442.944 483.608 442.992 483.808 ;
    END
  END t_o[276]
  PIN t_o[277]
    DIRECTION OUTPUT ;
    USE SIGNAL ;
    PORT
      LAYER M5 ;
        RECT 443.088 483.608 443.136 483.808 ;
    END
  END t_o[277]
  PIN t_o[278]
    DIRECTION OUTPUT ;
    USE SIGNAL ;
    PORT
      LAYER M5 ;
        RECT 443.232 483.608 443.280 483.808 ;
    END
  END t_o[278]
  PIN t_o[279]
    DIRECTION OUTPUT ;
    USE SIGNAL ;
    PORT
      LAYER M5 ;
        RECT 443.376 483.608 443.424 483.808 ;
    END
  END t_o[279]
  PIN t_o[280]
    DIRECTION OUTPUT ;
    USE SIGNAL ;
    PORT
      LAYER M5 ;
        RECT 443.520 483.608 443.568 483.808 ;
    END
  END t_o[280]
  PIN t_o[281]
    DIRECTION OUTPUT ;
    USE SIGNAL ;
    PORT
      LAYER M5 ;
        RECT 443.664 483.608 443.712 483.808 ;
    END
  END t_o[281]
  PIN t_o[282]
    DIRECTION OUTPUT ;
    USE SIGNAL ;
    PORT
      LAYER M5 ;
        RECT 443.808 483.608 443.856 483.808 ;
    END
  END t_o[282]
  PIN t_o[283]
    DIRECTION OUTPUT ;
    USE SIGNAL ;
    PORT
      LAYER M5 ;
        RECT 443.952 483.608 444.000 483.808 ;
    END
  END t_o[283]
  PIN t_o[284]
    DIRECTION OUTPUT ;
    USE SIGNAL ;
    PORT
      LAYER M5 ;
        RECT 444.096 483.608 444.144 483.808 ;
    END
  END t_o[284]
  PIN t_o[285]
    DIRECTION OUTPUT ;
    USE SIGNAL ;
    PORT
      LAYER M5 ;
        RECT 444.240 483.608 444.288 483.808 ;
    END
  END t_o[285]
  PIN t_o[286]
    DIRECTION OUTPUT ;
    USE SIGNAL ;
    PORT
      LAYER M5 ;
        RECT 444.384 483.608 444.432 483.808 ;
    END
  END t_o[286]
  PIN t_o[287]
    DIRECTION OUTPUT ;
    USE SIGNAL ;
    PORT
      LAYER M5 ;
        RECT 444.528 483.608 444.576 483.808 ;
    END
  END t_o[287]
  PIN t_o[288]
    DIRECTION OUTPUT ;
    USE SIGNAL ;
    PORT
      LAYER M5 ;
        RECT 444.672 483.608 444.720 483.808 ;
    END
  END t_o[288]
  PIN t_o[289]
    DIRECTION OUTPUT ;
    USE SIGNAL ;
    PORT
      LAYER M5 ;
        RECT 444.816 483.608 444.864 483.808 ;
    END
  END t_o[289]
  PIN t_o[290]
    DIRECTION OUTPUT ;
    USE SIGNAL ;
    PORT
      LAYER M5 ;
        RECT 444.960 483.608 445.008 483.808 ;
    END
  END t_o[290]
  PIN t_o[291]
    DIRECTION OUTPUT ;
    USE SIGNAL ;
    PORT
      LAYER M5 ;
        RECT 445.104 483.608 445.152 483.808 ;
    END
  END t_o[291]
  PIN t_o[292]
    DIRECTION OUTPUT ;
    USE SIGNAL ;
    PORT
      LAYER M5 ;
        RECT 445.248 483.608 445.296 483.808 ;
    END
  END t_o[292]
  PIN t_o[293]
    DIRECTION OUTPUT ;
    USE SIGNAL ;
    PORT
      LAYER M5 ;
        RECT 445.392 483.608 445.440 483.808 ;
    END
  END t_o[293]
  PIN t_o[294]
    DIRECTION OUTPUT ;
    USE SIGNAL ;
    PORT
      LAYER M5 ;
        RECT 445.536 483.608 445.584 483.808 ;
    END
  END t_o[294]
  PIN t_o[295]
    DIRECTION OUTPUT ;
    USE SIGNAL ;
    PORT
      LAYER M5 ;
        RECT 445.680 483.608 445.728 483.808 ;
    END
  END t_o[295]
  PIN t_o[296]
    DIRECTION OUTPUT ;
    USE SIGNAL ;
    PORT
      LAYER M5 ;
        RECT 445.824 483.608 445.872 483.808 ;
    END
  END t_o[296]
  PIN t_o[297]
    DIRECTION OUTPUT ;
    USE SIGNAL ;
    PORT
      LAYER M5 ;
        RECT 445.968 483.608 446.016 483.808 ;
    END
  END t_o[297]
  PIN t_o[298]
    DIRECTION OUTPUT ;
    USE SIGNAL ;
    PORT
      LAYER M5 ;
        RECT 446.112 483.608 446.160 483.808 ;
    END
  END t_o[298]
  PIN t_o[299]
    DIRECTION OUTPUT ;
    USE SIGNAL ;
    PORT
      LAYER M5 ;
        RECT 446.256 483.608 446.304 483.808 ;
    END
  END t_o[299]
  PIN t_o[300]
    DIRECTION OUTPUT ;
    USE SIGNAL ;
    PORT
      LAYER M5 ;
        RECT 446.400 483.608 446.448 483.808 ;
    END
  END t_o[300]
  PIN t_o[301]
    DIRECTION OUTPUT ;
    USE SIGNAL ;
    PORT
      LAYER M5 ;
        RECT 446.544 483.608 446.592 483.808 ;
    END
  END t_o[301]
  PIN t_o[302]
    DIRECTION OUTPUT ;
    USE SIGNAL ;
    PORT
      LAYER M5 ;
        RECT 446.688 483.608 446.736 483.808 ;
    END
  END t_o[302]
  PIN t_o[303]
    DIRECTION OUTPUT ;
    USE SIGNAL ;
    PORT
      LAYER M5 ;
        RECT 446.832 483.608 446.880 483.808 ;
    END
  END t_o[303]
  PIN t_o[304]
    DIRECTION OUTPUT ;
    USE SIGNAL ;
    PORT
      LAYER M5 ;
        RECT 446.976 483.608 447.024 483.808 ;
    END
  END t_o[304]
  PIN t_o[305]
    DIRECTION OUTPUT ;
    USE SIGNAL ;
    PORT
      LAYER M5 ;
        RECT 447.120 483.608 447.168 483.808 ;
    END
  END t_o[305]
  PIN t_o[306]
    DIRECTION OUTPUT ;
    USE SIGNAL ;
    PORT
      LAYER M5 ;
        RECT 447.264 483.608 447.312 483.808 ;
    END
  END t_o[306]
  PIN t_o[307]
    DIRECTION OUTPUT ;
    USE SIGNAL ;
    PORT
      LAYER M5 ;
        RECT 447.408 483.608 447.456 483.808 ;
    END
  END t_o[307]
  PIN t_o[308]
    DIRECTION OUTPUT ;
    USE SIGNAL ;
    PORT
      LAYER M5 ;
        RECT 447.552 483.608 447.600 483.808 ;
    END
  END t_o[308]
  PIN t_o[309]
    DIRECTION OUTPUT ;
    USE SIGNAL ;
    PORT
      LAYER M5 ;
        RECT 447.696 483.608 447.744 483.808 ;
    END
  END t_o[309]
  PIN t_o[310]
    DIRECTION OUTPUT ;
    USE SIGNAL ;
    PORT
      LAYER M5 ;
        RECT 447.840 483.608 447.888 483.808 ;
    END
  END t_o[310]
  PIN t_o[311]
    DIRECTION OUTPUT ;
    USE SIGNAL ;
    PORT
      LAYER M5 ;
        RECT 447.984 483.608 448.032 483.808 ;
    END
  END t_o[311]
  PIN t_o[312]
    DIRECTION OUTPUT ;
    USE SIGNAL ;
    PORT
      LAYER M5 ;
        RECT 448.128 483.608 448.176 483.808 ;
    END
  END t_o[312]
  PIN t_o[313]
    DIRECTION OUTPUT ;
    USE SIGNAL ;
    PORT
      LAYER M5 ;
        RECT 448.272 483.608 448.320 483.808 ;
    END
  END t_o[313]
  PIN t_o[314]
    DIRECTION OUTPUT ;
    USE SIGNAL ;
    PORT
      LAYER M5 ;
        RECT 448.416 483.608 448.464 483.808 ;
    END
  END t_o[314]
  PIN t_o[315]
    DIRECTION OUTPUT ;
    USE SIGNAL ;
    PORT
      LAYER M5 ;
        RECT 448.560 483.608 448.608 483.808 ;
    END
  END t_o[315]
  PIN t_o[316]
    DIRECTION OUTPUT ;
    USE SIGNAL ;
    PORT
      LAYER M5 ;
        RECT 448.704 483.608 448.752 483.808 ;
    END
  END t_o[316]
  PIN t_o[317]
    DIRECTION OUTPUT ;
    USE SIGNAL ;
    PORT
      LAYER M5 ;
        RECT 448.848 483.608 448.896 483.808 ;
    END
  END t_o[317]
  PIN t_o[318]
    DIRECTION OUTPUT ;
    USE SIGNAL ;
    PORT
      LAYER M5 ;
        RECT 448.992 483.608 449.040 483.808 ;
    END
  END t_o[318]
  PIN t_o[319]
    DIRECTION OUTPUT ;
    USE SIGNAL ;
    PORT
      LAYER M5 ;
        RECT 449.136 483.608 449.184 483.808 ;
    END
  END t_o[319]
  PIN t_o[320]
    DIRECTION OUTPUT ;
    USE SIGNAL ;
    PORT
      LAYER M5 ;
        RECT 449.280 483.608 449.328 483.808 ;
    END
  END t_o[320]
  PIN t_o[321]
    DIRECTION OUTPUT ;
    USE SIGNAL ;
    PORT
      LAYER M5 ;
        RECT 449.424 483.608 449.472 483.808 ;
    END
  END t_o[321]
  PIN t_o[322]
    DIRECTION OUTPUT ;
    USE SIGNAL ;
    PORT
      LAYER M5 ;
        RECT 449.568 483.608 449.616 483.808 ;
    END
  END t_o[322]
  PIN t_o[323]
    DIRECTION OUTPUT ;
    USE SIGNAL ;
    PORT
      LAYER M5 ;
        RECT 449.712 483.608 449.760 483.808 ;
    END
  END t_o[323]
  PIN t_o[324]
    DIRECTION OUTPUT ;
    USE SIGNAL ;
    PORT
      LAYER M5 ;
        RECT 449.856 483.608 449.904 483.808 ;
    END
  END t_o[324]
  PIN t_o[325]
    DIRECTION OUTPUT ;
    USE SIGNAL ;
    PORT
      LAYER M5 ;
        RECT 450.000 483.608 450.048 483.808 ;
    END
  END t_o[325]
  PIN t_o[326]
    DIRECTION OUTPUT ;
    USE SIGNAL ;
    PORT
      LAYER M5 ;
        RECT 450.144 483.608 450.192 483.808 ;
    END
  END t_o[326]
  PIN t_o[327]
    DIRECTION OUTPUT ;
    USE SIGNAL ;
    PORT
      LAYER M5 ;
        RECT 450.288 483.608 450.336 483.808 ;
    END
  END t_o[327]
  PIN t_o[328]
    DIRECTION OUTPUT ;
    USE SIGNAL ;
    PORT
      LAYER M5 ;
        RECT 450.432 483.608 450.480 483.808 ;
    END
  END t_o[328]
  PIN t_o[329]
    DIRECTION OUTPUT ;
    USE SIGNAL ;
    PORT
      LAYER M5 ;
        RECT 450.576 483.608 450.624 483.808 ;
    END
  END t_o[329]
  PIN t_o[330]
    DIRECTION OUTPUT ;
    USE SIGNAL ;
    PORT
      LAYER M5 ;
        RECT 450.720 483.608 450.768 483.808 ;
    END
  END t_o[330]
  PIN t_o[331]
    DIRECTION OUTPUT ;
    USE SIGNAL ;
    PORT
      LAYER M5 ;
        RECT 450.864 483.608 450.912 483.808 ;
    END
  END t_o[331]
  PIN t_o[332]
    DIRECTION OUTPUT ;
    USE SIGNAL ;
    PORT
      LAYER M5 ;
        RECT 451.008 483.608 451.056 483.808 ;
    END
  END t_o[332]
  PIN t_o[333]
    DIRECTION OUTPUT ;
    USE SIGNAL ;
    PORT
      LAYER M5 ;
        RECT 451.152 483.608 451.200 483.808 ;
    END
  END t_o[333]
  PIN t_o[334]
    DIRECTION OUTPUT ;
    USE SIGNAL ;
    PORT
      LAYER M5 ;
        RECT 451.296 483.608 451.344 483.808 ;
    END
  END t_o[334]
  PIN t_o[335]
    DIRECTION OUTPUT ;
    USE SIGNAL ;
    PORT
      LAYER M5 ;
        RECT 451.440 483.608 451.488 483.808 ;
    END
  END t_o[335]
  PIN t_o[336]
    DIRECTION OUTPUT ;
    USE SIGNAL ;
    PORT
      LAYER M5 ;
        RECT 451.584 483.608 451.632 483.808 ;
    END
  END t_o[336]
  PIN t_o[337]
    DIRECTION OUTPUT ;
    USE SIGNAL ;
    PORT
      LAYER M5 ;
        RECT 451.728 483.608 451.776 483.808 ;
    END
  END t_o[337]
  PIN t_o[338]
    DIRECTION OUTPUT ;
    USE SIGNAL ;
    PORT
      LAYER M5 ;
        RECT 451.872 483.608 451.920 483.808 ;
    END
  END t_o[338]
  PIN t_o[339]
    DIRECTION OUTPUT ;
    USE SIGNAL ;
    PORT
      LAYER M5 ;
        RECT 452.016 483.608 452.064 483.808 ;
    END
  END t_o[339]
  PIN t_o[340]
    DIRECTION OUTPUT ;
    USE SIGNAL ;
    PORT
      LAYER M5 ;
        RECT 452.160 483.608 452.208 483.808 ;
    END
  END t_o[340]
  PIN t_o[341]
    DIRECTION OUTPUT ;
    USE SIGNAL ;
    PORT
      LAYER M5 ;
        RECT 452.304 483.608 452.352 483.808 ;
    END
  END t_o[341]
  PIN t_o[342]
    DIRECTION OUTPUT ;
    USE SIGNAL ;
    PORT
      LAYER M5 ;
        RECT 452.448 483.608 452.496 483.808 ;
    END
  END t_o[342]
  PIN t_o[343]
    DIRECTION OUTPUT ;
    USE SIGNAL ;
    PORT
      LAYER M5 ;
        RECT 452.592 483.608 452.640 483.808 ;
    END
  END t_o[343]
  PIN t_o[344]
    DIRECTION OUTPUT ;
    USE SIGNAL ;
    PORT
      LAYER M5 ;
        RECT 452.736 483.608 452.784 483.808 ;
    END
  END t_o[344]
  PIN t_o[345]
    DIRECTION OUTPUT ;
    USE SIGNAL ;
    PORT
      LAYER M5 ;
        RECT 452.880 483.608 452.928 483.808 ;
    END
  END t_o[345]
  PIN t_o[346]
    DIRECTION OUTPUT ;
    USE SIGNAL ;
    PORT
      LAYER M5 ;
        RECT 453.024 483.608 453.072 483.808 ;
    END
  END t_o[346]
  PIN t_o[347]
    DIRECTION OUTPUT ;
    USE SIGNAL ;
    PORT
      LAYER M5 ;
        RECT 453.168 483.608 453.216 483.808 ;
    END
  END t_o[347]
  PIN t_o[348]
    DIRECTION OUTPUT ;
    USE SIGNAL ;
    PORT
      LAYER M5 ;
        RECT 453.312 483.608 453.360 483.808 ;
    END
  END t_o[348]
  PIN t_o[349]
    DIRECTION OUTPUT ;
    USE SIGNAL ;
    PORT
      LAYER M5 ;
        RECT 453.456 483.608 453.504 483.808 ;
    END
  END t_o[349]
  PIN t_o[350]
    DIRECTION OUTPUT ;
    USE SIGNAL ;
    PORT
      LAYER M5 ;
        RECT 453.600 483.608 453.648 483.808 ;
    END
  END t_o[350]
  PIN t_o[351]
    DIRECTION OUTPUT ;
    USE SIGNAL ;
    PORT
      LAYER M5 ;
        RECT 453.744 483.608 453.792 483.808 ;
    END
  END t_o[351]
  PIN t_o[352]
    DIRECTION OUTPUT ;
    USE SIGNAL ;
    PORT
      LAYER M5 ;
        RECT 453.888 483.608 453.936 483.808 ;
    END
  END t_o[352]
  PIN t_o[353]
    DIRECTION OUTPUT ;
    USE SIGNAL ;
    PORT
      LAYER M5 ;
        RECT 454.032 483.608 454.080 483.808 ;
    END
  END t_o[353]
  PIN t_s[0]
    DIRECTION OUTPUT ;
    USE SIGNAL ;
    PORT
      LAYER M5 ;
        RECT 454.176 483.608 454.224 483.808 ;
    END
  END t_s[0]
  PIN t_s[1]
    DIRECTION OUTPUT ;
    USE SIGNAL ;
    PORT
      LAYER M5 ;
        RECT 454.320 483.608 454.368 483.808 ;
    END
  END t_s[1]
  PIN t_s[2]
    DIRECTION OUTPUT ;
    USE SIGNAL ;
    PORT
      LAYER M5 ;
        RECT 454.464 483.608 454.512 483.808 ;
    END
  END t_s[2]
  PIN t_s[3]
    DIRECTION OUTPUT ;
    USE SIGNAL ;
    PORT
      LAYER M5 ;
        RECT 454.608 483.608 454.656 483.808 ;
    END
  END t_s[3]
  PIN t_s[4]
    DIRECTION OUTPUT ;
    USE SIGNAL ;
    PORT
      LAYER M5 ;
        RECT 454.752 483.608 454.800 483.808 ;
    END
  END t_s[4]
  PIN t_s[5]
    DIRECTION OUTPUT ;
    USE SIGNAL ;
    PORT
      LAYER M5 ;
        RECT 454.896 483.608 454.944 483.808 ;
    END
  END t_s[5]
  PIN t_s[6]
    DIRECTION OUTPUT ;
    USE SIGNAL ;
    PORT
      LAYER M5 ;
        RECT 455.040 483.608 455.088 483.808 ;
    END
  END t_s[6]
  PIN t_s[7]
    DIRECTION OUTPUT ;
    USE SIGNAL ;
    PORT
      LAYER M5 ;
        RECT 455.184 483.608 455.232 483.808 ;
    END
  END t_s[7]
  PIN t_s[8]
    DIRECTION OUTPUT ;
    USE SIGNAL ;
    PORT
      LAYER M5 ;
        RECT 455.328 483.608 455.376 483.808 ;
    END
  END t_s[8]
  PIN t_s[9]
    DIRECTION OUTPUT ;
    USE SIGNAL ;
    PORT
      LAYER M5 ;
        RECT 455.472 483.608 455.520 483.808 ;
    END
  END t_s[9]
  PIN t_s[10]
    DIRECTION OUTPUT ;
    USE SIGNAL ;
    PORT
      LAYER M5 ;
        RECT 455.616 483.608 455.664 483.808 ;
    END
  END t_s[10]
  PIN t_s[11]
    DIRECTION OUTPUT ;
    USE SIGNAL ;
    PORT
      LAYER M5 ;
        RECT 455.760 483.608 455.808 483.808 ;
    END
  END t_s[11]
  PIN t_s[12]
    DIRECTION OUTPUT ;
    USE SIGNAL ;
    PORT
      LAYER M5 ;
        RECT 455.904 483.608 455.952 483.808 ;
    END
  END t_s[12]
  PIN t_s[13]
    DIRECTION OUTPUT ;
    USE SIGNAL ;
    PORT
      LAYER M5 ;
        RECT 456.048 483.608 456.096 483.808 ;
    END
  END t_s[13]
  PIN t_s[14]
    DIRECTION OUTPUT ;
    USE SIGNAL ;
    PORT
      LAYER M5 ;
        RECT 456.192 483.608 456.240 483.808 ;
    END
  END t_s[14]
  PIN t_s[15]
    DIRECTION OUTPUT ;
    USE SIGNAL ;
    PORT
      LAYER M5 ;
        RECT 456.336 483.608 456.384 483.808 ;
    END
  END t_s[15]
  PIN t_s[16]
    DIRECTION OUTPUT ;
    USE SIGNAL ;
    PORT
      LAYER M5 ;
        RECT 456.480 483.608 456.528 483.808 ;
    END
  END t_s[16]
  PIN t_s[17]
    DIRECTION OUTPUT ;
    USE SIGNAL ;
    PORT
      LAYER M5 ;
        RECT 456.624 483.608 456.672 483.808 ;
    END
  END t_s[17]
  PIN t_s[18]
    DIRECTION OUTPUT ;
    USE SIGNAL ;
    PORT
      LAYER M5 ;
        RECT 456.768 483.608 456.816 483.808 ;
    END
  END t_s[18]
  PIN t_s[19]
    DIRECTION OUTPUT ;
    USE SIGNAL ;
    PORT
      LAYER M5 ;
        RECT 456.912 483.608 456.960 483.808 ;
    END
  END t_s[19]
  PIN t_s[20]
    DIRECTION OUTPUT ;
    USE SIGNAL ;
    PORT
      LAYER M5 ;
        RECT 457.056 483.608 457.104 483.808 ;
    END
  END t_s[20]
  PIN t_s[21]
    DIRECTION OUTPUT ;
    USE SIGNAL ;
    PORT
      LAYER M5 ;
        RECT 457.200 483.608 457.248 483.808 ;
    END
  END t_s[21]
  PIN t_s[22]
    DIRECTION OUTPUT ;
    USE SIGNAL ;
    PORT
      LAYER M5 ;
        RECT 457.344 483.608 457.392 483.808 ;
    END
  END t_s[22]
  PIN t_s[23]
    DIRECTION OUTPUT ;
    USE SIGNAL ;
    PORT
      LAYER M5 ;
        RECT 457.488 483.608 457.536 483.808 ;
    END
  END t_s[23]
  PIN t_s[24]
    DIRECTION OUTPUT ;
    USE SIGNAL ;
    PORT
      LAYER M5 ;
        RECT 457.632 483.608 457.680 483.808 ;
    END
  END t_s[24]
  PIN t_s[25]
    DIRECTION OUTPUT ;
    USE SIGNAL ;
    PORT
      LAYER M5 ;
        RECT 457.776 483.608 457.824 483.808 ;
    END
  END t_s[25]
  PIN t_s[26]
    DIRECTION OUTPUT ;
    USE SIGNAL ;
    PORT
      LAYER M5 ;
        RECT 457.920 483.608 457.968 483.808 ;
    END
  END t_s[26]
  PIN t_s[27]
    DIRECTION OUTPUT ;
    USE SIGNAL ;
    PORT
      LAYER M5 ;
        RECT 458.064 483.608 458.112 483.808 ;
    END
  END t_s[27]
  PIN t_s[28]
    DIRECTION OUTPUT ;
    USE SIGNAL ;
    PORT
      LAYER M5 ;
        RECT 458.208 483.608 458.256 483.808 ;
    END
  END t_s[28]
  PIN t_s[29]
    DIRECTION OUTPUT ;
    USE SIGNAL ;
    PORT
      LAYER M5 ;
        RECT 458.352 483.608 458.400 483.808 ;
    END
  END t_s[29]
  PIN t_s[30]
    DIRECTION OUTPUT ;
    USE SIGNAL ;
    PORT
      LAYER M5 ;
        RECT 458.496 483.608 458.544 483.808 ;
    END
  END t_s[30]
  PIN t_s[31]
    DIRECTION OUTPUT ;
    USE SIGNAL ;
    PORT
      LAYER M5 ;
        RECT 458.640 483.608 458.688 483.808 ;
    END
  END t_s[31]
  PIN t_s[32]
    DIRECTION OUTPUT ;
    USE SIGNAL ;
    PORT
      LAYER M5 ;
        RECT 458.784 483.608 458.832 483.808 ;
    END
  END t_s[32]
  PIN t_s[33]
    DIRECTION OUTPUT ;
    USE SIGNAL ;
    PORT
      LAYER M5 ;
        RECT 458.928 483.608 458.976 483.808 ;
    END
  END t_s[33]
  PIN t_s[34]
    DIRECTION OUTPUT ;
    USE SIGNAL ;
    PORT
      LAYER M5 ;
        RECT 459.072 483.608 459.120 483.808 ;
    END
  END t_s[34]
  PIN t_s[35]
    DIRECTION OUTPUT ;
    USE SIGNAL ;
    PORT
      LAYER M5 ;
        RECT 459.216 483.608 459.264 483.808 ;
    END
  END t_s[35]
  PIN t_s[36]
    DIRECTION OUTPUT ;
    USE SIGNAL ;
    PORT
      LAYER M5 ;
        RECT 459.360 483.608 459.408 483.808 ;
    END
  END t_s[36]
  PIN t_s[37]
    DIRECTION OUTPUT ;
    USE SIGNAL ;
    PORT
      LAYER M5 ;
        RECT 459.504 483.608 459.552 483.808 ;
    END
  END t_s[37]
  PIN t_s[38]
    DIRECTION OUTPUT ;
    USE SIGNAL ;
    PORT
      LAYER M5 ;
        RECT 459.648 483.608 459.696 483.808 ;
    END
  END t_s[38]
  PIN t_s[39]
    DIRECTION OUTPUT ;
    USE SIGNAL ;
    PORT
      LAYER M5 ;
        RECT 459.792 483.608 459.840 483.808 ;
    END
  END t_s[39]
  PIN t_s[40]
    DIRECTION OUTPUT ;
    USE SIGNAL ;
    PORT
      LAYER M5 ;
        RECT 459.936 483.608 459.984 483.808 ;
    END
  END t_s[40]
  PIN t_s[41]
    DIRECTION OUTPUT ;
    USE SIGNAL ;
    PORT
      LAYER M5 ;
        RECT 460.080 483.608 460.128 483.808 ;
    END
  END t_s[41]
  PIN t_s[42]
    DIRECTION OUTPUT ;
    USE SIGNAL ;
    PORT
      LAYER M5 ;
        RECT 460.224 483.608 460.272 483.808 ;
    END
  END t_s[42]
  PIN t_s[43]
    DIRECTION OUTPUT ;
    USE SIGNAL ;
    PORT
      LAYER M5 ;
        RECT 460.368 483.608 460.416 483.808 ;
    END
  END t_s[43]
  PIN t_s[44]
    DIRECTION OUTPUT ;
    USE SIGNAL ;
    PORT
      LAYER M5 ;
        RECT 460.512 483.608 460.560 483.808 ;
    END
  END t_s[44]
  PIN t_s[45]
    DIRECTION OUTPUT ;
    USE SIGNAL ;
    PORT
      LAYER M5 ;
        RECT 460.656 483.608 460.704 483.808 ;
    END
  END t_s[45]
  PIN t_s[46]
    DIRECTION OUTPUT ;
    USE SIGNAL ;
    PORT
      LAYER M5 ;
        RECT 460.800 483.608 460.848 483.808 ;
    END
  END t_s[46]
  PIN t_s[47]
    DIRECTION OUTPUT ;
    USE SIGNAL ;
    PORT
      LAYER M5 ;
        RECT 460.944 483.608 460.992 483.808 ;
    END
  END t_s[47]
  PIN t_s[48]
    DIRECTION OUTPUT ;
    USE SIGNAL ;
    PORT
      LAYER M5 ;
        RECT 461.088 483.608 461.136 483.808 ;
    END
  END t_s[48]
  PIN t_s[49]
    DIRECTION OUTPUT ;
    USE SIGNAL ;
    PORT
      LAYER M5 ;
        RECT 461.232 483.608 461.280 483.808 ;
    END
  END t_s[49]
  PIN t_s[50]
    DIRECTION OUTPUT ;
    USE SIGNAL ;
    PORT
      LAYER M5 ;
        RECT 461.376 483.608 461.424 483.808 ;
    END
  END t_s[50]
  PIN t_s[51]
    DIRECTION OUTPUT ;
    USE SIGNAL ;
    PORT
      LAYER M5 ;
        RECT 461.520 483.608 461.568 483.808 ;
    END
  END t_s[51]
  PIN t_s[52]
    DIRECTION OUTPUT ;
    USE SIGNAL ;
    PORT
      LAYER M5 ;
        RECT 461.664 483.608 461.712 483.808 ;
    END
  END t_s[52]
  PIN t_s[53]
    DIRECTION OUTPUT ;
    USE SIGNAL ;
    PORT
      LAYER M5 ;
        RECT 461.808 483.608 461.856 483.808 ;
    END
  END t_s[53]
  PIN t_s[54]
    DIRECTION OUTPUT ;
    USE SIGNAL ;
    PORT
      LAYER M5 ;
        RECT 461.952 483.608 462.000 483.808 ;
    END
  END t_s[54]
  PIN t_s[55]
    DIRECTION OUTPUT ;
    USE SIGNAL ;
    PORT
      LAYER M5 ;
        RECT 462.096 483.608 462.144 483.808 ;
    END
  END t_s[55]
  PIN t_s[56]
    DIRECTION OUTPUT ;
    USE SIGNAL ;
    PORT
      LAYER M5 ;
        RECT 462.240 483.608 462.288 483.808 ;
    END
  END t_s[56]
  PIN t_s[57]
    DIRECTION OUTPUT ;
    USE SIGNAL ;
    PORT
      LAYER M5 ;
        RECT 462.384 483.608 462.432 483.808 ;
    END
  END t_s[57]
  PIN t_s[58]
    DIRECTION OUTPUT ;
    USE SIGNAL ;
    PORT
      LAYER M5 ;
        RECT 462.528 483.608 462.576 483.808 ;
    END
  END t_s[58]
  PIN t_s[59]
    DIRECTION OUTPUT ;
    USE SIGNAL ;
    PORT
      LAYER M5 ;
        RECT 462.672 483.608 462.720 483.808 ;
    END
  END t_s[59]
  PIN t_s[60]
    DIRECTION OUTPUT ;
    USE SIGNAL ;
    PORT
      LAYER M5 ;
        RECT 462.816 483.608 462.864 483.808 ;
    END
  END t_s[60]
  PIN t_s[61]
    DIRECTION OUTPUT ;
    USE SIGNAL ;
    PORT
      LAYER M5 ;
        RECT 462.960 483.608 463.008 483.808 ;
    END
  END t_s[61]
  PIN t_s[62]
    DIRECTION OUTPUT ;
    USE SIGNAL ;
    PORT
      LAYER M5 ;
        RECT 463.104 483.608 463.152 483.808 ;
    END
  END t_s[62]
  PIN t_s[63]
    DIRECTION OUTPUT ;
    USE SIGNAL ;
    PORT
      LAYER M5 ;
        RECT 463.248 483.608 463.296 483.808 ;
    END
  END t_s[63]
  PIN t_s[64]
    DIRECTION OUTPUT ;
    USE SIGNAL ;
    PORT
      LAYER M5 ;
        RECT 463.392 483.608 463.440 483.808 ;
    END
  END t_s[64]
  PIN t_s[65]
    DIRECTION OUTPUT ;
    USE SIGNAL ;
    PORT
      LAYER M5 ;
        RECT 463.536 483.608 463.584 483.808 ;
    END
  END t_s[65]
  PIN t_s[66]
    DIRECTION OUTPUT ;
    USE SIGNAL ;
    PORT
      LAYER M5 ;
        RECT 463.680 483.608 463.728 483.808 ;
    END
  END t_s[66]
  PIN t_s[67]
    DIRECTION OUTPUT ;
    USE SIGNAL ;
    PORT
      LAYER M5 ;
        RECT 463.824 483.608 463.872 483.808 ;
    END
  END t_s[67]
  PIN t_s[68]
    DIRECTION OUTPUT ;
    USE SIGNAL ;
    PORT
      LAYER M5 ;
        RECT 463.968 483.608 464.016 483.808 ;
    END
  END t_s[68]
  PIN t_s[69]
    DIRECTION OUTPUT ;
    USE SIGNAL ;
    PORT
      LAYER M5 ;
        RECT 464.112 483.608 464.160 483.808 ;
    END
  END t_s[69]
  PIN t_s[70]
    DIRECTION OUTPUT ;
    USE SIGNAL ;
    PORT
      LAYER M5 ;
        RECT 464.256 483.608 464.304 483.808 ;
    END
  END t_s[70]
  PIN t_s[71]
    DIRECTION OUTPUT ;
    USE SIGNAL ;
    PORT
      LAYER M5 ;
        RECT 464.400 483.608 464.448 483.808 ;
    END
  END t_s[71]
  PIN t_s[72]
    DIRECTION OUTPUT ;
    USE SIGNAL ;
    PORT
      LAYER M5 ;
        RECT 464.544 483.608 464.592 483.808 ;
    END
  END t_s[72]
  PIN t_s[73]
    DIRECTION OUTPUT ;
    USE SIGNAL ;
    PORT
      LAYER M5 ;
        RECT 464.688 483.608 464.736 483.808 ;
    END
  END t_s[73]
  PIN t_s[74]
    DIRECTION OUTPUT ;
    USE SIGNAL ;
    PORT
      LAYER M5 ;
        RECT 464.832 483.608 464.880 483.808 ;
    END
  END t_s[74]
  PIN t_s[75]
    DIRECTION OUTPUT ;
    USE SIGNAL ;
    PORT
      LAYER M5 ;
        RECT 464.976 483.608 465.024 483.808 ;
    END
  END t_s[75]
  PIN t_s[76]
    DIRECTION OUTPUT ;
    USE SIGNAL ;
    PORT
      LAYER M5 ;
        RECT 465.120 483.608 465.168 483.808 ;
    END
  END t_s[76]
  PIN t_s[77]
    DIRECTION OUTPUT ;
    USE SIGNAL ;
    PORT
      LAYER M5 ;
        RECT 465.264 483.608 465.312 483.808 ;
    END
  END t_s[77]
  PIN t_s[78]
    DIRECTION OUTPUT ;
    USE SIGNAL ;
    PORT
      LAYER M5 ;
        RECT 465.408 483.608 465.456 483.808 ;
    END
  END t_s[78]
  PIN t_s[79]
    DIRECTION OUTPUT ;
    USE SIGNAL ;
    PORT
      LAYER M5 ;
        RECT 465.552 483.608 465.600 483.808 ;
    END
  END t_s[79]
  PIN t_s[80]
    DIRECTION OUTPUT ;
    USE SIGNAL ;
    PORT
      LAYER M5 ;
        RECT 465.696 483.608 465.744 483.808 ;
    END
  END t_s[80]
  PIN t_s[81]
    DIRECTION OUTPUT ;
    USE SIGNAL ;
    PORT
      LAYER M5 ;
        RECT 465.840 483.608 465.888 483.808 ;
    END
  END t_s[81]
  PIN t_s[82]
    DIRECTION OUTPUT ;
    USE SIGNAL ;
    PORT
      LAYER M5 ;
        RECT 465.984 483.608 466.032 483.808 ;
    END
  END t_s[82]
  PIN t_s[83]
    DIRECTION OUTPUT ;
    USE SIGNAL ;
    PORT
      LAYER M5 ;
        RECT 466.128 483.608 466.176 483.808 ;
    END
  END t_s[83]
  PIN t_s[84]
    DIRECTION OUTPUT ;
    USE SIGNAL ;
    PORT
      LAYER M5 ;
        RECT 466.272 483.608 466.320 483.808 ;
    END
  END t_s[84]
  PIN t_s[85]
    DIRECTION OUTPUT ;
    USE SIGNAL ;
    PORT
      LAYER M5 ;
        RECT 466.416 483.608 466.464 483.808 ;
    END
  END t_s[85]
  PIN t_s[86]
    DIRECTION OUTPUT ;
    USE SIGNAL ;
    PORT
      LAYER M5 ;
        RECT 466.560 483.608 466.608 483.808 ;
    END
  END t_s[86]
  PIN t_s[87]
    DIRECTION OUTPUT ;
    USE SIGNAL ;
    PORT
      LAYER M5 ;
        RECT 466.704 483.608 466.752 483.808 ;
    END
  END t_s[87]
  PIN t_s[88]
    DIRECTION OUTPUT ;
    USE SIGNAL ;
    PORT
      LAYER M5 ;
        RECT 466.848 483.608 466.896 483.808 ;
    END
  END t_s[88]
  PIN t_s[89]
    DIRECTION OUTPUT ;
    USE SIGNAL ;
    PORT
      LAYER M5 ;
        RECT 466.992 483.608 467.040 483.808 ;
    END
  END t_s[89]
  PIN t_s[90]
    DIRECTION OUTPUT ;
    USE SIGNAL ;
    PORT
      LAYER M5 ;
        RECT 467.136 483.608 467.184 483.808 ;
    END
  END t_s[90]
  PIN t_s[91]
    DIRECTION OUTPUT ;
    USE SIGNAL ;
    PORT
      LAYER M5 ;
        RECT 467.280 483.608 467.328 483.808 ;
    END
  END t_s[91]
  PIN t_s[92]
    DIRECTION OUTPUT ;
    USE SIGNAL ;
    PORT
      LAYER M5 ;
        RECT 467.424 483.608 467.472 483.808 ;
    END
  END t_s[92]
  PIN t_s[93]
    DIRECTION OUTPUT ;
    USE SIGNAL ;
    PORT
      LAYER M5 ;
        RECT 467.568 483.608 467.616 483.808 ;
    END
  END t_s[93]
  PIN t_s[94]
    DIRECTION OUTPUT ;
    USE SIGNAL ;
    PORT
      LAYER M5 ;
        RECT 467.712 483.608 467.760 483.808 ;
    END
  END t_s[94]
  PIN t_s[95]
    DIRECTION OUTPUT ;
    USE SIGNAL ;
    PORT
      LAYER M5 ;
        RECT 467.856 483.608 467.904 483.808 ;
    END
  END t_s[95]
  PIN t_s[96]
    DIRECTION OUTPUT ;
    USE SIGNAL ;
    PORT
      LAYER M5 ;
        RECT 468.000 483.608 468.048 483.808 ;
    END
  END t_s[96]
  PIN t_s[97]
    DIRECTION OUTPUT ;
    USE SIGNAL ;
    PORT
      LAYER M5 ;
        RECT 468.144 483.608 468.192 483.808 ;
    END
  END t_s[97]
  PIN t_s[98]
    DIRECTION OUTPUT ;
    USE SIGNAL ;
    PORT
      LAYER M5 ;
        RECT 468.288 483.608 468.336 483.808 ;
    END
  END t_s[98]
  PIN t_s[99]
    DIRECTION OUTPUT ;
    USE SIGNAL ;
    PORT
      LAYER M5 ;
        RECT 468.432 483.608 468.480 483.808 ;
    END
  END t_s[99]
  PIN t_s[100]
    DIRECTION OUTPUT ;
    USE SIGNAL ;
    PORT
      LAYER M5 ;
        RECT 468.576 483.608 468.624 483.808 ;
    END
  END t_s[100]
  PIN t_s[101]
    DIRECTION OUTPUT ;
    USE SIGNAL ;
    PORT
      LAYER M5 ;
        RECT 468.720 483.608 468.768 483.808 ;
    END
  END t_s[101]
  PIN t_s[102]
    DIRECTION OUTPUT ;
    USE SIGNAL ;
    PORT
      LAYER M5 ;
        RECT 468.864 483.608 468.912 483.808 ;
    END
  END t_s[102]
  PIN t_s[103]
    DIRECTION OUTPUT ;
    USE SIGNAL ;
    PORT
      LAYER M5 ;
        RECT 469.008 483.608 469.056 483.808 ;
    END
  END t_s[103]
  PIN t_s[104]
    DIRECTION OUTPUT ;
    USE SIGNAL ;
    PORT
      LAYER M5 ;
        RECT 469.152 483.608 469.200 483.808 ;
    END
  END t_s[104]
  PIN t_s[105]
    DIRECTION OUTPUT ;
    USE SIGNAL ;
    PORT
      LAYER M5 ;
        RECT 469.296 483.608 469.344 483.808 ;
    END
  END t_s[105]
  PIN t_s[106]
    DIRECTION OUTPUT ;
    USE SIGNAL ;
    PORT
      LAYER M5 ;
        RECT 469.440 483.608 469.488 483.808 ;
    END
  END t_s[106]
  PIN t_s[107]
    DIRECTION OUTPUT ;
    USE SIGNAL ;
    PORT
      LAYER M5 ;
        RECT 469.584 483.608 469.632 483.808 ;
    END
  END t_s[107]
  PIN t_s[108]
    DIRECTION OUTPUT ;
    USE SIGNAL ;
    PORT
      LAYER M5 ;
        RECT 469.728 483.608 469.776 483.808 ;
    END
  END t_s[108]
  PIN t_s[109]
    DIRECTION OUTPUT ;
    USE SIGNAL ;
    PORT
      LAYER M5 ;
        RECT 469.872 483.608 469.920 483.808 ;
    END
  END t_s[109]
  PIN t_s[110]
    DIRECTION OUTPUT ;
    USE SIGNAL ;
    PORT
      LAYER M5 ;
        RECT 470.016 483.608 470.064 483.808 ;
    END
  END t_s[110]
  PIN t_s[111]
    DIRECTION OUTPUT ;
    USE SIGNAL ;
    PORT
      LAYER M5 ;
        RECT 470.160 483.608 470.208 483.808 ;
    END
  END t_s[111]
  PIN t_s[112]
    DIRECTION OUTPUT ;
    USE SIGNAL ;
    PORT
      LAYER M5 ;
        RECT 470.304 483.608 470.352 483.808 ;
    END
  END t_s[112]
  PIN t_s[113]
    DIRECTION OUTPUT ;
    USE SIGNAL ;
    PORT
      LAYER M5 ;
        RECT 470.448 483.608 470.496 483.808 ;
    END
  END t_s[113]
  PIN t_s[114]
    DIRECTION OUTPUT ;
    USE SIGNAL ;
    PORT
      LAYER M5 ;
        RECT 470.592 483.608 470.640 483.808 ;
    END
  END t_s[114]
  PIN t_s[115]
    DIRECTION OUTPUT ;
    USE SIGNAL ;
    PORT
      LAYER M5 ;
        RECT 470.736 483.608 470.784 483.808 ;
    END
  END t_s[115]
  PIN t_s[116]
    DIRECTION OUTPUT ;
    USE SIGNAL ;
    PORT
      LAYER M5 ;
        RECT 470.880 483.608 470.928 483.808 ;
    END
  END t_s[116]
  PIN t_s[117]
    DIRECTION OUTPUT ;
    USE SIGNAL ;
    PORT
      LAYER M5 ;
        RECT 471.024 483.608 471.072 483.808 ;
    END
  END t_s[117]
  PIN t_s[118]
    DIRECTION OUTPUT ;
    USE SIGNAL ;
    PORT
      LAYER M5 ;
        RECT 471.168 483.608 471.216 483.808 ;
    END
  END t_s[118]
  PIN t_s[119]
    DIRECTION OUTPUT ;
    USE SIGNAL ;
    PORT
      LAYER M5 ;
        RECT 471.312 483.608 471.360 483.808 ;
    END
  END t_s[119]
  PIN t_s[120]
    DIRECTION OUTPUT ;
    USE SIGNAL ;
    PORT
      LAYER M5 ;
        RECT 471.456 483.608 471.504 483.808 ;
    END
  END t_s[120]
  PIN t_s[121]
    DIRECTION OUTPUT ;
    USE SIGNAL ;
    PORT
      LAYER M5 ;
        RECT 471.600 483.608 471.648 483.808 ;
    END
  END t_s[121]
  PIN t_s[122]
    DIRECTION OUTPUT ;
    USE SIGNAL ;
    PORT
      LAYER M5 ;
        RECT 471.744 483.608 471.792 483.808 ;
    END
  END t_s[122]
  PIN t_s[123]
    DIRECTION OUTPUT ;
    USE SIGNAL ;
    PORT
      LAYER M5 ;
        RECT 471.888 483.608 471.936 483.808 ;
    END
  END t_s[123]
  PIN t_s[124]
    DIRECTION OUTPUT ;
    USE SIGNAL ;
    PORT
      LAYER M5 ;
        RECT 472.032 483.608 472.080 483.808 ;
    END
  END t_s[124]
  PIN t_s[125]
    DIRECTION OUTPUT ;
    USE SIGNAL ;
    PORT
      LAYER M5 ;
        RECT 472.176 483.608 472.224 483.808 ;
    END
  END t_s[125]
  PIN t_s[126]
    DIRECTION OUTPUT ;
    USE SIGNAL ;
    PORT
      LAYER M5 ;
        RECT 472.320 483.608 472.368 483.808 ;
    END
  END t_s[126]
  PIN t_s[127]
    DIRECTION OUTPUT ;
    USE SIGNAL ;
    PORT
      LAYER M5 ;
        RECT 472.464 483.608 472.512 483.808 ;
    END
  END t_s[127]
  PIN t_s[128]
    DIRECTION OUTPUT ;
    USE SIGNAL ;
    PORT
      LAYER M5 ;
        RECT 472.608 483.608 472.656 483.808 ;
    END
  END t_s[128]
  PIN t_s[129]
    DIRECTION OUTPUT ;
    USE SIGNAL ;
    PORT
      LAYER M5 ;
        RECT 472.752 483.608 472.800 483.808 ;
    END
  END t_s[129]
  PIN t_s[130]
    DIRECTION OUTPUT ;
    USE SIGNAL ;
    PORT
      LAYER M5 ;
        RECT 472.896 483.608 472.944 483.808 ;
    END
  END t_s[130]
  PIN t_s[131]
    DIRECTION OUTPUT ;
    USE SIGNAL ;
    PORT
      LAYER M5 ;
        RECT 473.040 483.608 473.088 483.808 ;
    END
  END t_s[131]
  PIN t_s[132]
    DIRECTION OUTPUT ;
    USE SIGNAL ;
    PORT
      LAYER M5 ;
        RECT 473.184 483.608 473.232 483.808 ;
    END
  END t_s[132]
  PIN t_s[133]
    DIRECTION OUTPUT ;
    USE SIGNAL ;
    PORT
      LAYER M5 ;
        RECT 473.328 483.608 473.376 483.808 ;
    END
  END t_s[133]
  PIN t_s[134]
    DIRECTION OUTPUT ;
    USE SIGNAL ;
    PORT
      LAYER M5 ;
        RECT 473.472 483.608 473.520 483.808 ;
    END
  END t_s[134]
  PIN t_s[135]
    DIRECTION OUTPUT ;
    USE SIGNAL ;
    PORT
      LAYER M5 ;
        RECT 473.616 483.608 473.664 483.808 ;
    END
  END t_s[135]
  PIN t_s[136]
    DIRECTION OUTPUT ;
    USE SIGNAL ;
    PORT
      LAYER M5 ;
        RECT 473.760 483.608 473.808 483.808 ;
    END
  END t_s[136]
  PIN t_s[137]
    DIRECTION OUTPUT ;
    USE SIGNAL ;
    PORT
      LAYER M5 ;
        RECT 473.904 483.608 473.952 483.808 ;
    END
  END t_s[137]
  PIN t_s[138]
    DIRECTION OUTPUT ;
    USE SIGNAL ;
    PORT
      LAYER M5 ;
        RECT 474.048 483.608 474.096 483.808 ;
    END
  END t_s[138]
  PIN t_s[139]
    DIRECTION OUTPUT ;
    USE SIGNAL ;
    PORT
      LAYER M5 ;
        RECT 474.192 483.608 474.240 483.808 ;
    END
  END t_s[139]
  PIN t_s[140]
    DIRECTION OUTPUT ;
    USE SIGNAL ;
    PORT
      LAYER M5 ;
        RECT 474.336 483.608 474.384 483.808 ;
    END
  END t_s[140]
  PIN t_s[141]
    DIRECTION OUTPUT ;
    USE SIGNAL ;
    PORT
      LAYER M5 ;
        RECT 474.480 483.608 474.528 483.808 ;
    END
  END t_s[141]
  PIN t_s[142]
    DIRECTION OUTPUT ;
    USE SIGNAL ;
    PORT
      LAYER M5 ;
        RECT 474.624 483.608 474.672 483.808 ;
    END
  END t_s[142]
  PIN t_s[143]
    DIRECTION OUTPUT ;
    USE SIGNAL ;
    PORT
      LAYER M5 ;
        RECT 474.768 483.608 474.816 483.808 ;
    END
  END t_s[143]
  PIN t_s[144]
    DIRECTION OUTPUT ;
    USE SIGNAL ;
    PORT
      LAYER M5 ;
        RECT 474.912 483.608 474.960 483.808 ;
    END
  END t_s[144]
  PIN t_s[145]
    DIRECTION OUTPUT ;
    USE SIGNAL ;
    PORT
      LAYER M5 ;
        RECT 475.056 483.608 475.104 483.808 ;
    END
  END t_s[145]
  PIN t_s[146]
    DIRECTION OUTPUT ;
    USE SIGNAL ;
    PORT
      LAYER M5 ;
        RECT 475.200 483.608 475.248 483.808 ;
    END
  END t_s[146]
  PIN t_s[147]
    DIRECTION OUTPUT ;
    USE SIGNAL ;
    PORT
      LAYER M5 ;
        RECT 475.344 483.608 475.392 483.808 ;
    END
  END t_s[147]
  PIN t_s[148]
    DIRECTION OUTPUT ;
    USE SIGNAL ;
    PORT
      LAYER M5 ;
        RECT 475.488 483.608 475.536 483.808 ;
    END
  END t_s[148]
  PIN t_s[149]
    DIRECTION OUTPUT ;
    USE SIGNAL ;
    PORT
      LAYER M5 ;
        RECT 475.632 483.608 475.680 483.808 ;
    END
  END t_s[149]
  PIN t_s[150]
    DIRECTION OUTPUT ;
    USE SIGNAL ;
    PORT
      LAYER M5 ;
        RECT 475.776 483.608 475.824 483.808 ;
    END
  END t_s[150]
  PIN t_s[151]
    DIRECTION OUTPUT ;
    USE SIGNAL ;
    PORT
      LAYER M5 ;
        RECT 475.920 483.608 475.968 483.808 ;
    END
  END t_s[151]
  PIN t_s[152]
    DIRECTION OUTPUT ;
    USE SIGNAL ;
    PORT
      LAYER M5 ;
        RECT 476.064 483.608 476.112 483.808 ;
    END
  END t_s[152]
  PIN t_s[153]
    DIRECTION OUTPUT ;
    USE SIGNAL ;
    PORT
      LAYER M5 ;
        RECT 476.208 483.608 476.256 483.808 ;
    END
  END t_s[153]
  PIN t_s[154]
    DIRECTION OUTPUT ;
    USE SIGNAL ;
    PORT
      LAYER M5 ;
        RECT 476.352 483.608 476.400 483.808 ;
    END
  END t_s[154]
  PIN t_s[155]
    DIRECTION OUTPUT ;
    USE SIGNAL ;
    PORT
      LAYER M5 ;
        RECT 476.496 483.608 476.544 483.808 ;
    END
  END t_s[155]
  PIN t_s[156]
    DIRECTION OUTPUT ;
    USE SIGNAL ;
    PORT
      LAYER M5 ;
        RECT 476.640 483.608 476.688 483.808 ;
    END
  END t_s[156]
  PIN t_s[157]
    DIRECTION OUTPUT ;
    USE SIGNAL ;
    PORT
      LAYER M5 ;
        RECT 476.784 483.608 476.832 483.808 ;
    END
  END t_s[157]
  PIN t_s[158]
    DIRECTION OUTPUT ;
    USE SIGNAL ;
    PORT
      LAYER M5 ;
        RECT 476.928 483.608 476.976 483.808 ;
    END
  END t_s[158]
  PIN t_s[159]
    DIRECTION OUTPUT ;
    USE SIGNAL ;
    PORT
      LAYER M5 ;
        RECT 477.072 483.608 477.120 483.808 ;
    END
  END t_s[159]
  PIN t_s[160]
    DIRECTION OUTPUT ;
    USE SIGNAL ;
    PORT
      LAYER M5 ;
        RECT 477.216 483.608 477.264 483.808 ;
    END
  END t_s[160]
  PIN t_s[161]
    DIRECTION OUTPUT ;
    USE SIGNAL ;
    PORT
      LAYER M5 ;
        RECT 477.360 483.608 477.408 483.808 ;
    END
  END t_s[161]
  PIN t_s[162]
    DIRECTION OUTPUT ;
    USE SIGNAL ;
    PORT
      LAYER M5 ;
        RECT 477.504 483.608 477.552 483.808 ;
    END
  END t_s[162]
  PIN t_s[163]
    DIRECTION OUTPUT ;
    USE SIGNAL ;
    PORT
      LAYER M5 ;
        RECT 477.648 483.608 477.696 483.808 ;
    END
  END t_s[163]
  PIN t_s[164]
    DIRECTION OUTPUT ;
    USE SIGNAL ;
    PORT
      LAYER M5 ;
        RECT 477.792 483.608 477.840 483.808 ;
    END
  END t_s[164]
  PIN t_s[165]
    DIRECTION OUTPUT ;
    USE SIGNAL ;
    PORT
      LAYER M5 ;
        RECT 477.936 483.608 477.984 483.808 ;
    END
  END t_s[165]
  PIN t_s[166]
    DIRECTION OUTPUT ;
    USE SIGNAL ;
    PORT
      LAYER M5 ;
        RECT 478.080 483.608 478.128 483.808 ;
    END
  END t_s[166]
  PIN t_s[167]
    DIRECTION OUTPUT ;
    USE SIGNAL ;
    PORT
      LAYER M5 ;
        RECT 478.224 483.608 478.272 483.808 ;
    END
  END t_s[167]
  PIN t_s[168]
    DIRECTION OUTPUT ;
    USE SIGNAL ;
    PORT
      LAYER M5 ;
        RECT 478.368 483.608 478.416 483.808 ;
    END
  END t_s[168]
  PIN t_s[169]
    DIRECTION OUTPUT ;
    USE SIGNAL ;
    PORT
      LAYER M5 ;
        RECT 478.512 483.608 478.560 483.808 ;
    END
  END t_s[169]
  PIN t_s[170]
    DIRECTION OUTPUT ;
    USE SIGNAL ;
    PORT
      LAYER M5 ;
        RECT 478.656 483.608 478.704 483.808 ;
    END
  END t_s[170]
  PIN t_s[171]
    DIRECTION OUTPUT ;
    USE SIGNAL ;
    PORT
      LAYER M5 ;
        RECT 478.800 483.608 478.848 483.808 ;
    END
  END t_s[171]
  PIN t_s[172]
    DIRECTION OUTPUT ;
    USE SIGNAL ;
    PORT
      LAYER M5 ;
        RECT 478.944 483.608 478.992 483.808 ;
    END
  END t_s[172]
  PIN t_s[173]
    DIRECTION OUTPUT ;
    USE SIGNAL ;
    PORT
      LAYER M5 ;
        RECT 479.088 483.608 479.136 483.808 ;
    END
  END t_s[173]
  PIN t_s[174]
    DIRECTION OUTPUT ;
    USE SIGNAL ;
    PORT
      LAYER M5 ;
        RECT 479.232 483.608 479.280 483.808 ;
    END
  END t_s[174]
  PIN t_s[175]
    DIRECTION OUTPUT ;
    USE SIGNAL ;
    PORT
      LAYER M5 ;
        RECT 479.376 483.608 479.424 483.808 ;
    END
  END t_s[175]
  PIN t_s[176]
    DIRECTION OUTPUT ;
    USE SIGNAL ;
    PORT
      LAYER M5 ;
        RECT 479.520 483.608 479.568 483.808 ;
    END
  END t_s[176]
  PIN t_s[177]
    DIRECTION OUTPUT ;
    USE SIGNAL ;
    PORT
      LAYER M5 ;
        RECT 479.664 483.608 479.712 483.808 ;
    END
  END t_s[177]
  PIN t_s[178]
    DIRECTION OUTPUT ;
    USE SIGNAL ;
    PORT
      LAYER M5 ;
        RECT 479.808 483.608 479.856 483.808 ;
    END
  END t_s[178]
  PIN t_s[179]
    DIRECTION OUTPUT ;
    USE SIGNAL ;
    PORT
      LAYER M5 ;
        RECT 479.952 483.608 480.000 483.808 ;
    END
  END t_s[179]
  PIN t_s[180]
    DIRECTION OUTPUT ;
    USE SIGNAL ;
    PORT
      LAYER M5 ;
        RECT 480.096 483.608 480.144 483.808 ;
    END
  END t_s[180]
  PIN t_s[181]
    DIRECTION OUTPUT ;
    USE SIGNAL ;
    PORT
      LAYER M5 ;
        RECT 480.240 483.608 480.288 483.808 ;
    END
  END t_s[181]
  PIN t_s[182]
    DIRECTION OUTPUT ;
    USE SIGNAL ;
    PORT
      LAYER M5 ;
        RECT 480.384 483.608 480.432 483.808 ;
    END
  END t_s[182]
  PIN t_s[183]
    DIRECTION OUTPUT ;
    USE SIGNAL ;
    PORT
      LAYER M5 ;
        RECT 480.528 483.608 480.576 483.808 ;
    END
  END t_s[183]
  PIN t_s[184]
    DIRECTION OUTPUT ;
    USE SIGNAL ;
    PORT
      LAYER M5 ;
        RECT 480.672 483.608 480.720 483.808 ;
    END
  END t_s[184]
  PIN t_s[185]
    DIRECTION OUTPUT ;
    USE SIGNAL ;
    PORT
      LAYER M5 ;
        RECT 480.816 483.608 480.864 483.808 ;
    END
  END t_s[185]
  PIN t_s[186]
    DIRECTION OUTPUT ;
    USE SIGNAL ;
    PORT
      LAYER M5 ;
        RECT 480.960 483.608 481.008 483.808 ;
    END
  END t_s[186]
  PIN t_s[187]
    DIRECTION OUTPUT ;
    USE SIGNAL ;
    PORT
      LAYER M5 ;
        RECT 481.104 483.608 481.152 483.808 ;
    END
  END t_s[187]
  PIN t_s[188]
    DIRECTION OUTPUT ;
    USE SIGNAL ;
    PORT
      LAYER M5 ;
        RECT 481.248 483.608 481.296 483.808 ;
    END
  END t_s[188]
  PIN t_s[189]
    DIRECTION OUTPUT ;
    USE SIGNAL ;
    PORT
      LAYER M5 ;
        RECT 481.392 483.608 481.440 483.808 ;
    END
  END t_s[189]
  PIN t_s[190]
    DIRECTION OUTPUT ;
    USE SIGNAL ;
    PORT
      LAYER M5 ;
        RECT 481.536 483.608 481.584 483.808 ;
    END
  END t_s[190]
  PIN t_s[191]
    DIRECTION OUTPUT ;
    USE SIGNAL ;
    PORT
      LAYER M5 ;
        RECT 481.680 483.608 481.728 483.808 ;
    END
  END t_s[191]
  PIN t_s[192]
    DIRECTION OUTPUT ;
    USE SIGNAL ;
    PORT
      LAYER M5 ;
        RECT 481.824 483.608 481.872 483.808 ;
    END
  END t_s[192]
  PIN t_s[193]
    DIRECTION OUTPUT ;
    USE SIGNAL ;
    PORT
      LAYER M5 ;
        RECT 481.968 483.608 482.016 483.808 ;
    END
  END t_s[193]
  PIN t_s[194]
    DIRECTION OUTPUT ;
    USE SIGNAL ;
    PORT
      LAYER M5 ;
        RECT 482.112 483.608 482.160 483.808 ;
    END
  END t_s[194]
  PIN t_s[195]
    DIRECTION OUTPUT ;
    USE SIGNAL ;
    PORT
      LAYER M5 ;
        RECT 482.256 483.608 482.304 483.808 ;
    END
  END t_s[195]
  PIN t_s[196]
    DIRECTION OUTPUT ;
    USE SIGNAL ;
    PORT
      LAYER M5 ;
        RECT 482.400 483.608 482.448 483.808 ;
    END
  END t_s[196]
  PIN t_s[197]
    DIRECTION OUTPUT ;
    USE SIGNAL ;
    PORT
      LAYER M5 ;
        RECT 482.544 483.608 482.592 483.808 ;
    END
  END t_s[197]
  PIN t_s[198]
    DIRECTION OUTPUT ;
    USE SIGNAL ;
    PORT
      LAYER M5 ;
        RECT 482.688 483.608 482.736 483.808 ;
    END
  END t_s[198]
  PIN t_s[199]
    DIRECTION OUTPUT ;
    USE SIGNAL ;
    PORT
      LAYER M5 ;
        RECT 482.832 483.608 482.880 483.808 ;
    END
  END t_s[199]
  PIN t_s[200]
    DIRECTION OUTPUT ;
    USE SIGNAL ;
    PORT
      LAYER M5 ;
        RECT 482.976 483.608 483.024 483.808 ;
    END
  END t_s[200]
  PIN t_s[201]
    DIRECTION OUTPUT ;
    USE SIGNAL ;
    PORT
      LAYER M5 ;
        RECT 483.120 483.608 483.168 483.808 ;
    END
  END t_s[201]
  PIN t_s[202]
    DIRECTION OUTPUT ;
    USE SIGNAL ;
    PORT
      LAYER M5 ;
        RECT 483.264 483.608 483.312 483.808 ;
    END
  END t_s[202]
  PIN t_s[203]
    DIRECTION OUTPUT ;
    USE SIGNAL ;
    PORT
      LAYER M5 ;
        RECT 483.408 483.608 483.456 483.808 ;
    END
  END t_s[203]
  PIN t_s[204]
    DIRECTION OUTPUT ;
    USE SIGNAL ;
    PORT
      LAYER M5 ;
        RECT 483.552 483.608 483.600 483.808 ;
    END
  END t_s[204]
  PIN t_s[205]
    DIRECTION OUTPUT ;
    USE SIGNAL ;
    PORT
      LAYER M5 ;
        RECT 483.696 483.608 483.744 483.808 ;
    END
  END t_s[205]
  PIN t_s[206]
    DIRECTION OUTPUT ;
    USE SIGNAL ;
    PORT
      LAYER M5 ;
        RECT 483.840 483.608 483.888 483.808 ;
    END
  END t_s[206]
  PIN t_s[207]
    DIRECTION OUTPUT ;
    USE SIGNAL ;
    PORT
      LAYER M5 ;
        RECT 483.984 483.608 484.032 483.808 ;
    END
  END t_s[207]
  PIN t_s[208]
    DIRECTION OUTPUT ;
    USE SIGNAL ;
    PORT
      LAYER M5 ;
        RECT 484.128 483.608 484.176 483.808 ;
    END
  END t_s[208]
  PIN t_s[209]
    DIRECTION OUTPUT ;
    USE SIGNAL ;
    PORT
      LAYER M5 ;
        RECT 484.272 483.608 484.320 483.808 ;
    END
  END t_s[209]
  PIN t_s[210]
    DIRECTION OUTPUT ;
    USE SIGNAL ;
    PORT
      LAYER M5 ;
        RECT 484.416 483.608 484.464 483.808 ;
    END
  END t_s[210]
  PIN t_s[211]
    DIRECTION OUTPUT ;
    USE SIGNAL ;
    PORT
      LAYER M5 ;
        RECT 484.560 483.608 484.608 483.808 ;
    END
  END t_s[211]
  PIN t_s[212]
    DIRECTION OUTPUT ;
    USE SIGNAL ;
    PORT
      LAYER M5 ;
        RECT 484.704 483.608 484.752 483.808 ;
    END
  END t_s[212]
  PIN t_s[213]
    DIRECTION OUTPUT ;
    USE SIGNAL ;
    PORT
      LAYER M5 ;
        RECT 484.848 483.608 484.896 483.808 ;
    END
  END t_s[213]
  PIN t_s[214]
    DIRECTION OUTPUT ;
    USE SIGNAL ;
    PORT
      LAYER M5 ;
        RECT 484.992 483.608 485.040 483.808 ;
    END
  END t_s[214]
  PIN t_s[215]
    DIRECTION OUTPUT ;
    USE SIGNAL ;
    PORT
      LAYER M5 ;
        RECT 485.136 483.608 485.184 483.808 ;
    END
  END t_s[215]
  PIN t_s[216]
    DIRECTION OUTPUT ;
    USE SIGNAL ;
    PORT
      LAYER M5 ;
        RECT 485.280 483.608 485.328 483.808 ;
    END
  END t_s[216]
  PIN t_s[217]
    DIRECTION OUTPUT ;
    USE SIGNAL ;
    PORT
      LAYER M5 ;
        RECT 485.424 483.608 485.472 483.808 ;
    END
  END t_s[217]
  PIN t_s[218]
    DIRECTION OUTPUT ;
    USE SIGNAL ;
    PORT
      LAYER M5 ;
        RECT 485.568 483.608 485.616 483.808 ;
    END
  END t_s[218]
  PIN t_s[219]
    DIRECTION OUTPUT ;
    USE SIGNAL ;
    PORT
      LAYER M5 ;
        RECT 485.712 483.608 485.760 483.808 ;
    END
  END t_s[219]
  PIN t_s[220]
    DIRECTION OUTPUT ;
    USE SIGNAL ;
    PORT
      LAYER M5 ;
        RECT 485.856 483.608 485.904 483.808 ;
    END
  END t_s[220]
  PIN t_s[221]
    DIRECTION OUTPUT ;
    USE SIGNAL ;
    PORT
      LAYER M5 ;
        RECT 486.000 483.608 486.048 483.808 ;
    END
  END t_s[221]
  PIN t_s[222]
    DIRECTION OUTPUT ;
    USE SIGNAL ;
    PORT
      LAYER M5 ;
        RECT 486.144 483.608 486.192 483.808 ;
    END
  END t_s[222]
  PIN t_s[223]
    DIRECTION OUTPUT ;
    USE SIGNAL ;
    PORT
      LAYER M5 ;
        RECT 486.288 483.608 486.336 483.808 ;
    END
  END t_s[223]
  PIN t_s[224]
    DIRECTION OUTPUT ;
    USE SIGNAL ;
    PORT
      LAYER M5 ;
        RECT 486.432 483.608 486.480 483.808 ;
    END
  END t_s[224]
  PIN t_s[225]
    DIRECTION OUTPUT ;
    USE SIGNAL ;
    PORT
      LAYER M5 ;
        RECT 486.576 483.608 486.624 483.808 ;
    END
  END t_s[225]
  PIN t_s[226]
    DIRECTION OUTPUT ;
    USE SIGNAL ;
    PORT
      LAYER M5 ;
        RECT 486.720 483.608 486.768 483.808 ;
    END
  END t_s[226]
  PIN t_s[227]
    DIRECTION OUTPUT ;
    USE SIGNAL ;
    PORT
      LAYER M5 ;
        RECT 486.864 483.608 486.912 483.808 ;
    END
  END t_s[227]
  PIN t_s[228]
    DIRECTION OUTPUT ;
    USE SIGNAL ;
    PORT
      LAYER M5 ;
        RECT 487.008 483.608 487.056 483.808 ;
    END
  END t_s[228]
  PIN t_s[229]
    DIRECTION OUTPUT ;
    USE SIGNAL ;
    PORT
      LAYER M5 ;
        RECT 487.152 483.608 487.200 483.808 ;
    END
  END t_s[229]
  PIN t_s[230]
    DIRECTION OUTPUT ;
    USE SIGNAL ;
    PORT
      LAYER M5 ;
        RECT 487.296 483.608 487.344 483.808 ;
    END
  END t_s[230]
  PIN t_s[231]
    DIRECTION OUTPUT ;
    USE SIGNAL ;
    PORT
      LAYER M5 ;
        RECT 487.440 483.608 487.488 483.808 ;
    END
  END t_s[231]
  PIN t_s[232]
    DIRECTION OUTPUT ;
    USE SIGNAL ;
    PORT
      LAYER M5 ;
        RECT 487.584 483.608 487.632 483.808 ;
    END
  END t_s[232]
  PIN t_s[233]
    DIRECTION OUTPUT ;
    USE SIGNAL ;
    PORT
      LAYER M5 ;
        RECT 487.728 483.608 487.776 483.808 ;
    END
  END t_s[233]
  PIN t_s[234]
    DIRECTION OUTPUT ;
    USE SIGNAL ;
    PORT
      LAYER M5 ;
        RECT 487.872 483.608 487.920 483.808 ;
    END
  END t_s[234]
  PIN t_s[235]
    DIRECTION OUTPUT ;
    USE SIGNAL ;
    PORT
      LAYER M5 ;
        RECT 488.016 483.608 488.064 483.808 ;
    END
  END t_s[235]
  PIN t_s[236]
    DIRECTION OUTPUT ;
    USE SIGNAL ;
    PORT
      LAYER M5 ;
        RECT 488.160 483.608 488.208 483.808 ;
    END
  END t_s[236]
  PIN t_s[237]
    DIRECTION OUTPUT ;
    USE SIGNAL ;
    PORT
      LAYER M5 ;
        RECT 488.304 483.608 488.352 483.808 ;
    END
  END t_s[237]
  PIN t_s[238]
    DIRECTION OUTPUT ;
    USE SIGNAL ;
    PORT
      LAYER M5 ;
        RECT 488.448 483.608 488.496 483.808 ;
    END
  END t_s[238]
  PIN t_s[239]
    DIRECTION OUTPUT ;
    USE SIGNAL ;
    PORT
      LAYER M5 ;
        RECT 488.592 483.608 488.640 483.808 ;
    END
  END t_s[239]
  PIN t_s[240]
    DIRECTION OUTPUT ;
    USE SIGNAL ;
    PORT
      LAYER M5 ;
        RECT 488.736 483.608 488.784 483.808 ;
    END
  END t_s[240]
  PIN t_s[241]
    DIRECTION OUTPUT ;
    USE SIGNAL ;
    PORT
      LAYER M5 ;
        RECT 488.880 483.608 488.928 483.808 ;
    END
  END t_s[241]
  PIN t_s[242]
    DIRECTION OUTPUT ;
    USE SIGNAL ;
    PORT
      LAYER M5 ;
        RECT 489.024 483.608 489.072 483.808 ;
    END
  END t_s[242]
  PIN t_s[243]
    DIRECTION OUTPUT ;
    USE SIGNAL ;
    PORT
      LAYER M5 ;
        RECT 489.168 483.608 489.216 483.808 ;
    END
  END t_s[243]
  PIN t_s[244]
    DIRECTION OUTPUT ;
    USE SIGNAL ;
    PORT
      LAYER M5 ;
        RECT 489.312 483.608 489.360 483.808 ;
    END
  END t_s[244]
  PIN t_s[245]
    DIRECTION OUTPUT ;
    USE SIGNAL ;
    PORT
      LAYER M5 ;
        RECT 489.456 483.608 489.504 483.808 ;
    END
  END t_s[245]
  PIN t_s[246]
    DIRECTION OUTPUT ;
    USE SIGNAL ;
    PORT
      LAYER M5 ;
        RECT 489.600 483.608 489.648 483.808 ;
    END
  END t_s[246]
  PIN t_s[247]
    DIRECTION OUTPUT ;
    USE SIGNAL ;
    PORT
      LAYER M5 ;
        RECT 489.744 483.608 489.792 483.808 ;
    END
  END t_s[247]
  PIN t_s[248]
    DIRECTION OUTPUT ;
    USE SIGNAL ;
    PORT
      LAYER M5 ;
        RECT 489.888 483.608 489.936 483.808 ;
    END
  END t_s[248]
  PIN t_s[249]
    DIRECTION OUTPUT ;
    USE SIGNAL ;
    PORT
      LAYER M5 ;
        RECT 490.032 483.608 490.080 483.808 ;
    END
  END t_s[249]
  PIN t_s[250]
    DIRECTION OUTPUT ;
    USE SIGNAL ;
    PORT
      LAYER M5 ;
        RECT 490.176 483.608 490.224 483.808 ;
    END
  END t_s[250]
  PIN t_s[251]
    DIRECTION OUTPUT ;
    USE SIGNAL ;
    PORT
      LAYER M5 ;
        RECT 490.320 483.608 490.368 483.808 ;
    END
  END t_s[251]
  PIN t_s[252]
    DIRECTION OUTPUT ;
    USE SIGNAL ;
    PORT
      LAYER M5 ;
        RECT 490.464 483.608 490.512 483.808 ;
    END
  END t_s[252]
  PIN t_s[253]
    DIRECTION OUTPUT ;
    USE SIGNAL ;
    PORT
      LAYER M5 ;
        RECT 490.608 483.608 490.656 483.808 ;
    END
  END t_s[253]
  PIN t_s[254]
    DIRECTION OUTPUT ;
    USE SIGNAL ;
    PORT
      LAYER M5 ;
        RECT 490.752 483.608 490.800 483.808 ;
    END
  END t_s[254]
  PIN t_s[255]
    DIRECTION OUTPUT ;
    USE SIGNAL ;
    PORT
      LAYER M5 ;
        RECT 490.896 483.608 490.944 483.808 ;
    END
  END t_s[255]
  PIN t_s[256]
    DIRECTION OUTPUT ;
    USE SIGNAL ;
    PORT
      LAYER M5 ;
        RECT 491.040 483.608 491.088 483.808 ;
    END
  END t_s[256]
  PIN t_s[257]
    DIRECTION OUTPUT ;
    USE SIGNAL ;
    PORT
      LAYER M5 ;
        RECT 491.184 483.608 491.232 483.808 ;
    END
  END t_s[257]
  PIN t_s[258]
    DIRECTION OUTPUT ;
    USE SIGNAL ;
    PORT
      LAYER M5 ;
        RECT 491.328 483.608 491.376 483.808 ;
    END
  END t_s[258]
  PIN t_s[259]
    DIRECTION OUTPUT ;
    USE SIGNAL ;
    PORT
      LAYER M5 ;
        RECT 491.472 483.608 491.520 483.808 ;
    END
  END t_s[259]
  PIN t_s[260]
    DIRECTION OUTPUT ;
    USE SIGNAL ;
    PORT
      LAYER M5 ;
        RECT 491.616 483.608 491.664 483.808 ;
    END
  END t_s[260]
  PIN t_s[261]
    DIRECTION OUTPUT ;
    USE SIGNAL ;
    PORT
      LAYER M5 ;
        RECT 491.760 483.608 491.808 483.808 ;
    END
  END t_s[261]
  PIN t_s[262]
    DIRECTION OUTPUT ;
    USE SIGNAL ;
    PORT
      LAYER M5 ;
        RECT 491.904 483.608 491.952 483.808 ;
    END
  END t_s[262]
  PIN t_s[263]
    DIRECTION OUTPUT ;
    USE SIGNAL ;
    PORT
      LAYER M5 ;
        RECT 492.048 483.608 492.096 483.808 ;
    END
  END t_s[263]
  PIN t_s[264]
    DIRECTION OUTPUT ;
    USE SIGNAL ;
    PORT
      LAYER M5 ;
        RECT 492.192 483.608 492.240 483.808 ;
    END
  END t_s[264]
  PIN t_s[265]
    DIRECTION OUTPUT ;
    USE SIGNAL ;
    PORT
      LAYER M5 ;
        RECT 492.336 483.608 492.384 483.808 ;
    END
  END t_s[265]
  PIN t_s[266]
    DIRECTION OUTPUT ;
    USE SIGNAL ;
    PORT
      LAYER M5 ;
        RECT 492.480 483.608 492.528 483.808 ;
    END
  END t_s[266]
  PIN t_s[267]
    DIRECTION OUTPUT ;
    USE SIGNAL ;
    PORT
      LAYER M5 ;
        RECT 492.624 483.608 492.672 483.808 ;
    END
  END t_s[267]
  PIN t_s[268]
    DIRECTION OUTPUT ;
    USE SIGNAL ;
    PORT
      LAYER M5 ;
        RECT 492.768 483.608 492.816 483.808 ;
    END
  END t_s[268]
  PIN t_s[269]
    DIRECTION OUTPUT ;
    USE SIGNAL ;
    PORT
      LAYER M5 ;
        RECT 492.912 483.608 492.960 483.808 ;
    END
  END t_s[269]
  PIN t_s[270]
    DIRECTION OUTPUT ;
    USE SIGNAL ;
    PORT
      LAYER M5 ;
        RECT 493.056 483.608 493.104 483.808 ;
    END
  END t_s[270]
  PIN t_s[271]
    DIRECTION OUTPUT ;
    USE SIGNAL ;
    PORT
      LAYER M5 ;
        RECT 493.200 483.608 493.248 483.808 ;
    END
  END t_s[271]
  PIN t_s[272]
    DIRECTION OUTPUT ;
    USE SIGNAL ;
    PORT
      LAYER M5 ;
        RECT 493.344 483.608 493.392 483.808 ;
    END
  END t_s[272]
  PIN t_s[273]
    DIRECTION OUTPUT ;
    USE SIGNAL ;
    PORT
      LAYER M5 ;
        RECT 493.488 483.608 493.536 483.808 ;
    END
  END t_s[273]
  PIN t_s[274]
    DIRECTION OUTPUT ;
    USE SIGNAL ;
    PORT
      LAYER M5 ;
        RECT 493.632 483.608 493.680 483.808 ;
    END
  END t_s[274]
  PIN t_s[275]
    DIRECTION OUTPUT ;
    USE SIGNAL ;
    PORT
      LAYER M5 ;
        RECT 493.776 483.608 493.824 483.808 ;
    END
  END t_s[275]
  PIN t_s[276]
    DIRECTION OUTPUT ;
    USE SIGNAL ;
    PORT
      LAYER M5 ;
        RECT 493.920 483.608 493.968 483.808 ;
    END
  END t_s[276]
  PIN t_s[277]
    DIRECTION OUTPUT ;
    USE SIGNAL ;
    PORT
      LAYER M5 ;
        RECT 494.064 483.608 494.112 483.808 ;
    END
  END t_s[277]
  PIN t_s[278]
    DIRECTION OUTPUT ;
    USE SIGNAL ;
    PORT
      LAYER M5 ;
        RECT 494.208 483.608 494.256 483.808 ;
    END
  END t_s[278]
  PIN t_s[279]
    DIRECTION OUTPUT ;
    USE SIGNAL ;
    PORT
      LAYER M5 ;
        RECT 494.352 483.608 494.400 483.808 ;
    END
  END t_s[279]
  PIN t_s[280]
    DIRECTION OUTPUT ;
    USE SIGNAL ;
    PORT
      LAYER M5 ;
        RECT 494.496 483.608 494.544 483.808 ;
    END
  END t_s[280]
  PIN t_s[281]
    DIRECTION OUTPUT ;
    USE SIGNAL ;
    PORT
      LAYER M5 ;
        RECT 494.640 483.608 494.688 483.808 ;
    END
  END t_s[281]
  PIN t_s[282]
    DIRECTION OUTPUT ;
    USE SIGNAL ;
    PORT
      LAYER M5 ;
        RECT 494.784 483.608 494.832 483.808 ;
    END
  END t_s[282]
  PIN t_s[283]
    DIRECTION OUTPUT ;
    USE SIGNAL ;
    PORT
      LAYER M5 ;
        RECT 494.928 483.608 494.976 483.808 ;
    END
  END t_s[283]
  PIN t_s[284]
    DIRECTION OUTPUT ;
    USE SIGNAL ;
    PORT
      LAYER M5 ;
        RECT 495.072 483.608 495.120 483.808 ;
    END
  END t_s[284]
  PIN t_s[285]
    DIRECTION OUTPUT ;
    USE SIGNAL ;
    PORT
      LAYER M5 ;
        RECT 495.216 483.608 495.264 483.808 ;
    END
  END t_s[285]
  PIN t_s[286]
    DIRECTION OUTPUT ;
    USE SIGNAL ;
    PORT
      LAYER M5 ;
        RECT 495.360 483.608 495.408 483.808 ;
    END
  END t_s[286]
  PIN t_s[287]
    DIRECTION OUTPUT ;
    USE SIGNAL ;
    PORT
      LAYER M5 ;
        RECT 495.504 483.608 495.552 483.808 ;
    END
  END t_s[287]
  PIN t_s[288]
    DIRECTION OUTPUT ;
    USE SIGNAL ;
    PORT
      LAYER M5 ;
        RECT 495.648 483.608 495.696 483.808 ;
    END
  END t_s[288]
  PIN t_s[289]
    DIRECTION OUTPUT ;
    USE SIGNAL ;
    PORT
      LAYER M5 ;
        RECT 495.792 483.608 495.840 483.808 ;
    END
  END t_s[289]
  PIN t_s[290]
    DIRECTION OUTPUT ;
    USE SIGNAL ;
    PORT
      LAYER M5 ;
        RECT 495.936 483.608 495.984 483.808 ;
    END
  END t_s[290]
  PIN t_s[291]
    DIRECTION OUTPUT ;
    USE SIGNAL ;
    PORT
      LAYER M5 ;
        RECT 496.080 483.608 496.128 483.808 ;
    END
  END t_s[291]
  PIN t_s[292]
    DIRECTION OUTPUT ;
    USE SIGNAL ;
    PORT
      LAYER M5 ;
        RECT 496.224 483.608 496.272 483.808 ;
    END
  END t_s[292]
  PIN t_s[293]
    DIRECTION OUTPUT ;
    USE SIGNAL ;
    PORT
      LAYER M5 ;
        RECT 496.368 483.608 496.416 483.808 ;
    END
  END t_s[293]
  PIN t_s[294]
    DIRECTION OUTPUT ;
    USE SIGNAL ;
    PORT
      LAYER M5 ;
        RECT 496.512 483.608 496.560 483.808 ;
    END
  END t_s[294]
  PIN t_s[295]
    DIRECTION OUTPUT ;
    USE SIGNAL ;
    PORT
      LAYER M5 ;
        RECT 496.656 483.608 496.704 483.808 ;
    END
  END t_s[295]
  PIN t_s[296]
    DIRECTION OUTPUT ;
    USE SIGNAL ;
    PORT
      LAYER M5 ;
        RECT 496.800 483.608 496.848 483.808 ;
    END
  END t_s[296]
  PIN t_s[297]
    DIRECTION OUTPUT ;
    USE SIGNAL ;
    PORT
      LAYER M5 ;
        RECT 496.944 483.608 496.992 483.808 ;
    END
  END t_s[297]
  PIN t_s[298]
    DIRECTION OUTPUT ;
    USE SIGNAL ;
    PORT
      LAYER M5 ;
        RECT 497.088 483.608 497.136 483.808 ;
    END
  END t_s[298]
  PIN t_s[299]
    DIRECTION OUTPUT ;
    USE SIGNAL ;
    PORT
      LAYER M5 ;
        RECT 497.232 483.608 497.280 483.808 ;
    END
  END t_s[299]
  PIN t_s[300]
    DIRECTION OUTPUT ;
    USE SIGNAL ;
    PORT
      LAYER M5 ;
        RECT 497.376 483.608 497.424 483.808 ;
    END
  END t_s[300]
  PIN t_s[301]
    DIRECTION OUTPUT ;
    USE SIGNAL ;
    PORT
      LAYER M5 ;
        RECT 497.520 483.608 497.568 483.808 ;
    END
  END t_s[301]
  PIN t_s[302]
    DIRECTION OUTPUT ;
    USE SIGNAL ;
    PORT
      LAYER M5 ;
        RECT 497.664 483.608 497.712 483.808 ;
    END
  END t_s[302]
  PIN t_s[303]
    DIRECTION OUTPUT ;
    USE SIGNAL ;
    PORT
      LAYER M5 ;
        RECT 497.808 483.608 497.856 483.808 ;
    END
  END t_s[303]
  PIN t_s[304]
    DIRECTION OUTPUT ;
    USE SIGNAL ;
    PORT
      LAYER M5 ;
        RECT 497.952 483.608 498.000 483.808 ;
    END
  END t_s[304]
  PIN t_s[305]
    DIRECTION OUTPUT ;
    USE SIGNAL ;
    PORT
      LAYER M5 ;
        RECT 498.096 483.608 498.144 483.808 ;
    END
  END t_s[305]
  PIN t_s[306]
    DIRECTION OUTPUT ;
    USE SIGNAL ;
    PORT
      LAYER M5 ;
        RECT 498.240 483.608 498.288 483.808 ;
    END
  END t_s[306]
  PIN t_s[307]
    DIRECTION OUTPUT ;
    USE SIGNAL ;
    PORT
      LAYER M5 ;
        RECT 498.384 483.608 498.432 483.808 ;
    END
  END t_s[307]
  PIN t_s[308]
    DIRECTION OUTPUT ;
    USE SIGNAL ;
    PORT
      LAYER M5 ;
        RECT 498.528 483.608 498.576 483.808 ;
    END
  END t_s[308]
  PIN t_s[309]
    DIRECTION OUTPUT ;
    USE SIGNAL ;
    PORT
      LAYER M5 ;
        RECT 498.672 483.608 498.720 483.808 ;
    END
  END t_s[309]
  PIN t_s[310]
    DIRECTION OUTPUT ;
    USE SIGNAL ;
    PORT
      LAYER M5 ;
        RECT 498.816 483.608 498.864 483.808 ;
    END
  END t_s[310]
  PIN t_s[311]
    DIRECTION OUTPUT ;
    USE SIGNAL ;
    PORT
      LAYER M5 ;
        RECT 498.960 483.608 499.008 483.808 ;
    END
  END t_s[311]
  PIN t_s[312]
    DIRECTION OUTPUT ;
    USE SIGNAL ;
    PORT
      LAYER M5 ;
        RECT 499.104 483.608 499.152 483.808 ;
    END
  END t_s[312]
  PIN t_s[313]
    DIRECTION OUTPUT ;
    USE SIGNAL ;
    PORT
      LAYER M5 ;
        RECT 499.248 483.608 499.296 483.808 ;
    END
  END t_s[313]
  PIN t_s[314]
    DIRECTION OUTPUT ;
    USE SIGNAL ;
    PORT
      LAYER M5 ;
        RECT 499.392 483.608 499.440 483.808 ;
    END
  END t_s[314]
  PIN t_s[315]
    DIRECTION OUTPUT ;
    USE SIGNAL ;
    PORT
      LAYER M5 ;
        RECT 499.536 483.608 499.584 483.808 ;
    END
  END t_s[315]
  PIN t_s[316]
    DIRECTION OUTPUT ;
    USE SIGNAL ;
    PORT
      LAYER M5 ;
        RECT 499.680 483.608 499.728 483.808 ;
    END
  END t_s[316]
  PIN t_s[317]
    DIRECTION OUTPUT ;
    USE SIGNAL ;
    PORT
      LAYER M5 ;
        RECT 499.824 483.608 499.872 483.808 ;
    END
  END t_s[317]
  PIN t_s[318]
    DIRECTION OUTPUT ;
    USE SIGNAL ;
    PORT
      LAYER M5 ;
        RECT 499.968 483.608 500.016 483.808 ;
    END
  END t_s[318]
  PIN t_s[319]
    DIRECTION OUTPUT ;
    USE SIGNAL ;
    PORT
      LAYER M5 ;
        RECT 500.112 483.608 500.160 483.808 ;
    END
  END t_s[319]
  PIN t_s[320]
    DIRECTION OUTPUT ;
    USE SIGNAL ;
    PORT
      LAYER M5 ;
        RECT 500.256 483.608 500.304 483.808 ;
    END
  END t_s[320]
  PIN t_s[321]
    DIRECTION OUTPUT ;
    USE SIGNAL ;
    PORT
      LAYER M5 ;
        RECT 500.400 483.608 500.448 483.808 ;
    END
  END t_s[321]
  PIN t_s[322]
    DIRECTION OUTPUT ;
    USE SIGNAL ;
    PORT
      LAYER M5 ;
        RECT 500.544 483.608 500.592 483.808 ;
    END
  END t_s[322]
  PIN t_s[323]
    DIRECTION OUTPUT ;
    USE SIGNAL ;
    PORT
      LAYER M5 ;
        RECT 500.688 483.608 500.736 483.808 ;
    END
  END t_s[323]
  PIN t_s[324]
    DIRECTION OUTPUT ;
    USE SIGNAL ;
    PORT
      LAYER M5 ;
        RECT 500.832 483.608 500.880 483.808 ;
    END
  END t_s[324]
  PIN t_s[325]
    DIRECTION OUTPUT ;
    USE SIGNAL ;
    PORT
      LAYER M5 ;
        RECT 500.976 483.608 501.024 483.808 ;
    END
  END t_s[325]
  PIN t_s[326]
    DIRECTION OUTPUT ;
    USE SIGNAL ;
    PORT
      LAYER M5 ;
        RECT 501.120 483.608 501.168 483.808 ;
    END
  END t_s[326]
  PIN t_s[327]
    DIRECTION OUTPUT ;
    USE SIGNAL ;
    PORT
      LAYER M5 ;
        RECT 501.264 483.608 501.312 483.808 ;
    END
  END t_s[327]
  PIN t_s[328]
    DIRECTION OUTPUT ;
    USE SIGNAL ;
    PORT
      LAYER M5 ;
        RECT 501.408 483.608 501.456 483.808 ;
    END
  END t_s[328]
  PIN t_s[329]
    DIRECTION OUTPUT ;
    USE SIGNAL ;
    PORT
      LAYER M5 ;
        RECT 501.552 483.608 501.600 483.808 ;
    END
  END t_s[329]
  PIN t_s[330]
    DIRECTION OUTPUT ;
    USE SIGNAL ;
    PORT
      LAYER M5 ;
        RECT 501.696 483.608 501.744 483.808 ;
    END
  END t_s[330]
  PIN t_s[331]
    DIRECTION OUTPUT ;
    USE SIGNAL ;
    PORT
      LAYER M5 ;
        RECT 501.840 483.608 501.888 483.808 ;
    END
  END t_s[331]
  PIN t_s[332]
    DIRECTION OUTPUT ;
    USE SIGNAL ;
    PORT
      LAYER M5 ;
        RECT 501.984 483.608 502.032 483.808 ;
    END
  END t_s[332]
  PIN t_s[333]
    DIRECTION OUTPUT ;
    USE SIGNAL ;
    PORT
      LAYER M5 ;
        RECT 502.128 483.608 502.176 483.808 ;
    END
  END t_s[333]
  PIN t_s[334]
    DIRECTION OUTPUT ;
    USE SIGNAL ;
    PORT
      LAYER M5 ;
        RECT 502.272 483.608 502.320 483.808 ;
    END
  END t_s[334]
  PIN t_s[335]
    DIRECTION OUTPUT ;
    USE SIGNAL ;
    PORT
      LAYER M5 ;
        RECT 502.416 483.608 502.464 483.808 ;
    END
  END t_s[335]
  PIN t_s[336]
    DIRECTION OUTPUT ;
    USE SIGNAL ;
    PORT
      LAYER M5 ;
        RECT 502.560 483.608 502.608 483.808 ;
    END
  END t_s[336]
  PIN t_s[337]
    DIRECTION OUTPUT ;
    USE SIGNAL ;
    PORT
      LAYER M5 ;
        RECT 502.704 483.608 502.752 483.808 ;
    END
  END t_s[337]
  PIN t_s[338]
    DIRECTION OUTPUT ;
    USE SIGNAL ;
    PORT
      LAYER M5 ;
        RECT 502.848 483.608 502.896 483.808 ;
    END
  END t_s[338]
  PIN t_s[339]
    DIRECTION OUTPUT ;
    USE SIGNAL ;
    PORT
      LAYER M5 ;
        RECT 502.992 483.608 503.040 483.808 ;
    END
  END t_s[339]
  PIN t_s[340]
    DIRECTION OUTPUT ;
    USE SIGNAL ;
    PORT
      LAYER M5 ;
        RECT 503.136 483.608 503.184 483.808 ;
    END
  END t_s[340]
  PIN t_s[341]
    DIRECTION OUTPUT ;
    USE SIGNAL ;
    PORT
      LAYER M5 ;
        RECT 503.280 483.608 503.328 483.808 ;
    END
  END t_s[341]
  PIN t_s[342]
    DIRECTION OUTPUT ;
    USE SIGNAL ;
    PORT
      LAYER M5 ;
        RECT 503.424 483.608 503.472 483.808 ;
    END
  END t_s[342]
  PIN t_s[343]
    DIRECTION OUTPUT ;
    USE SIGNAL ;
    PORT
      LAYER M5 ;
        RECT 503.568 483.608 503.616 483.808 ;
    END
  END t_s[343]
  PIN t_s[344]
    DIRECTION OUTPUT ;
    USE SIGNAL ;
    PORT
      LAYER M5 ;
        RECT 503.712 483.608 503.760 483.808 ;
    END
  END t_s[344]
  PIN t_s[345]
    DIRECTION OUTPUT ;
    USE SIGNAL ;
    PORT
      LAYER M5 ;
        RECT 503.856 483.608 503.904 483.808 ;
    END
  END t_s[345]
  PIN t_s[346]
    DIRECTION OUTPUT ;
    USE SIGNAL ;
    PORT
      LAYER M5 ;
        RECT 504.000 483.608 504.048 483.808 ;
    END
  END t_s[346]
  PIN t_s[347]
    DIRECTION OUTPUT ;
    USE SIGNAL ;
    PORT
      LAYER M5 ;
        RECT 504.144 483.608 504.192 483.808 ;
    END
  END t_s[347]
  PIN t_s[348]
    DIRECTION OUTPUT ;
    USE SIGNAL ;
    PORT
      LAYER M5 ;
        RECT 504.288 483.608 504.336 483.808 ;
    END
  END t_s[348]
  PIN t_s[349]
    DIRECTION OUTPUT ;
    USE SIGNAL ;
    PORT
      LAYER M5 ;
        RECT 504.432 483.608 504.480 483.808 ;
    END
  END t_s[349]
  PIN t_s[350]
    DIRECTION OUTPUT ;
    USE SIGNAL ;
    PORT
      LAYER M5 ;
        RECT 504.576 483.608 504.624 483.808 ;
    END
  END t_s[350]
  PIN t_s[351]
    DIRECTION OUTPUT ;
    USE SIGNAL ;
    PORT
      LAYER M5 ;
        RECT 504.720 483.608 504.768 483.808 ;
    END
  END t_s[351]
  PIN t_s[352]
    DIRECTION OUTPUT ;
    USE SIGNAL ;
    PORT
      LAYER M5 ;
        RECT 504.864 483.608 504.912 483.808 ;
    END
  END t_s[352]
  PIN t_s[353]
    DIRECTION OUTPUT ;
    USE SIGNAL ;
    PORT
      LAYER M5 ;
        RECT 505.008 483.608 505.056 483.808 ;
    END
  END t_s[353]
  PIN t_s[354]
    DIRECTION OUTPUT ;
    USE SIGNAL ;
    PORT
      LAYER M5 ;
        RECT 505.152 483.608 505.200 483.808 ;
    END
  END t_s[354]
  PIN t_s[355]
    DIRECTION OUTPUT ;
    USE SIGNAL ;
    PORT
      LAYER M5 ;
        RECT 505.296 483.608 505.344 483.808 ;
    END
  END t_s[355]
  PIN t_s[356]
    DIRECTION OUTPUT ;
    USE SIGNAL ;
    PORT
      LAYER M5 ;
        RECT 505.440 483.608 505.488 483.808 ;
    END
  END t_s[356]
  PIN t_s[357]
    DIRECTION OUTPUT ;
    USE SIGNAL ;
    PORT
      LAYER M5 ;
        RECT 505.584 483.608 505.632 483.808 ;
    END
  END t_s[357]
  PIN t_s[358]
    DIRECTION OUTPUT ;
    USE SIGNAL ;
    PORT
      LAYER M5 ;
        RECT 505.728 483.608 505.776 483.808 ;
    END
  END t_s[358]
  PIN t_s[359]
    DIRECTION OUTPUT ;
    USE SIGNAL ;
    PORT
      LAYER M5 ;
        RECT 505.872 483.608 505.920 483.808 ;
    END
  END t_s[359]
  PIN t_s[360]
    DIRECTION OUTPUT ;
    USE SIGNAL ;
    PORT
      LAYER M5 ;
        RECT 506.016 483.608 506.064 483.808 ;
    END
  END t_s[360]
  PIN t_s[361]
    DIRECTION OUTPUT ;
    USE SIGNAL ;
    PORT
      LAYER M5 ;
        RECT 506.160 483.608 506.208 483.808 ;
    END
  END t_s[361]
  PIN t_s[362]
    DIRECTION OUTPUT ;
    USE SIGNAL ;
    PORT
      LAYER M5 ;
        RECT 506.304 483.608 506.352 483.808 ;
    END
  END t_s[362]
  PIN t_s[363]
    DIRECTION OUTPUT ;
    USE SIGNAL ;
    PORT
      LAYER M5 ;
        RECT 506.448 483.608 506.496 483.808 ;
    END
  END t_s[363]
  PIN t_s[364]
    DIRECTION OUTPUT ;
    USE SIGNAL ;
    PORT
      LAYER M5 ;
        RECT 506.592 483.608 506.640 483.808 ;
    END
  END t_s[364]
  PIN t_s[365]
    DIRECTION OUTPUT ;
    USE SIGNAL ;
    PORT
      LAYER M5 ;
        RECT 506.736 483.608 506.784 483.808 ;
    END
  END t_s[365]
  PIN t_s[366]
    DIRECTION OUTPUT ;
    USE SIGNAL ;
    PORT
      LAYER M5 ;
        RECT 506.880 483.608 506.928 483.808 ;
    END
  END t_s[366]
  PIN t_s[367]
    DIRECTION OUTPUT ;
    USE SIGNAL ;
    PORT
      LAYER M5 ;
        RECT 507.024 483.608 507.072 483.808 ;
    END
  END t_s[367]
  PIN t_s[368]
    DIRECTION OUTPUT ;
    USE SIGNAL ;
    PORT
      LAYER M5 ;
        RECT 507.168 483.608 507.216 483.808 ;
    END
  END t_s[368]
  PIN t_s[369]
    DIRECTION OUTPUT ;
    USE SIGNAL ;
    PORT
      LAYER M5 ;
        RECT 507.312 483.608 507.360 483.808 ;
    END
  END t_s[369]
  PIN t_s[370]
    DIRECTION OUTPUT ;
    USE SIGNAL ;
    PORT
      LAYER M5 ;
        RECT 507.456 483.608 507.504 483.808 ;
    END
  END t_s[370]
  PIN t_s[371]
    DIRECTION OUTPUT ;
    USE SIGNAL ;
    PORT
      LAYER M5 ;
        RECT 507.600 483.608 507.648 483.808 ;
    END
  END t_s[371]
  PIN t_s[372]
    DIRECTION OUTPUT ;
    USE SIGNAL ;
    PORT
      LAYER M5 ;
        RECT 507.744 483.608 507.792 483.808 ;
    END
  END t_s[372]
  PIN t_s[373]
    DIRECTION OUTPUT ;
    USE SIGNAL ;
    PORT
      LAYER M5 ;
        RECT 507.888 483.608 507.936 483.808 ;
    END
  END t_s[373]
  PIN t_s[374]
    DIRECTION OUTPUT ;
    USE SIGNAL ;
    PORT
      LAYER M5 ;
        RECT 508.032 483.608 508.080 483.808 ;
    END
  END t_s[374]
  PIN t_s[375]
    DIRECTION OUTPUT ;
    USE SIGNAL ;
    PORT
      LAYER M5 ;
        RECT 508.176 483.608 508.224 483.808 ;
    END
  END t_s[375]
  PIN t_s[376]
    DIRECTION OUTPUT ;
    USE SIGNAL ;
    PORT
      LAYER M5 ;
        RECT 508.320 483.608 508.368 483.808 ;
    END
  END t_s[376]
  PIN t_s[377]
    DIRECTION OUTPUT ;
    USE SIGNAL ;
    PORT
      LAYER M5 ;
        RECT 508.464 483.608 508.512 483.808 ;
    END
  END t_s[377]
  PIN t_s[378]
    DIRECTION OUTPUT ;
    USE SIGNAL ;
    PORT
      LAYER M5 ;
        RECT 508.608 483.608 508.656 483.808 ;
    END
  END t_s[378]
  PIN t_s[379]
    DIRECTION OUTPUT ;
    USE SIGNAL ;
    PORT
      LAYER M5 ;
        RECT 508.752 483.608 508.800 483.808 ;
    END
  END t_s[379]
  PIN t_s[380]
    DIRECTION OUTPUT ;
    USE SIGNAL ;
    PORT
      LAYER M5 ;
        RECT 508.896 483.608 508.944 483.808 ;
    END
  END t_s[380]
  PIN t_s[381]
    DIRECTION OUTPUT ;
    USE SIGNAL ;
    PORT
      LAYER M5 ;
        RECT 509.040 483.608 509.088 483.808 ;
    END
  END t_s[381]
  PIN t_s[382]
    DIRECTION OUTPUT ;
    USE SIGNAL ;
    PORT
      LAYER M5 ;
        RECT 509.184 483.608 509.232 483.808 ;
    END
  END t_s[382]
  PIN t_s[383]
    DIRECTION OUTPUT ;
    USE SIGNAL ;
    PORT
      LAYER M5 ;
        RECT 509.328 483.608 509.376 483.808 ;
    END
  END t_s[383]
  PIN t_s[384]
    DIRECTION OUTPUT ;
    USE SIGNAL ;
    PORT
      LAYER M5 ;
        RECT 509.472 483.608 509.520 483.808 ;
    END
  END t_s[384]
  PIN t_s[385]
    DIRECTION OUTPUT ;
    USE SIGNAL ;
    PORT
      LAYER M5 ;
        RECT 509.616 483.608 509.664 483.808 ;
    END
  END t_s[385]
  PIN t_s[386]
    DIRECTION OUTPUT ;
    USE SIGNAL ;
    PORT
      LAYER M5 ;
        RECT 509.760 483.608 509.808 483.808 ;
    END
  END t_s[386]
  PIN t_s[387]
    DIRECTION OUTPUT ;
    USE SIGNAL ;
    PORT
      LAYER M5 ;
        RECT 509.904 483.608 509.952 483.808 ;
    END
  END t_s[387]
  PIN t_s[388]
    DIRECTION OUTPUT ;
    USE SIGNAL ;
    PORT
      LAYER M5 ;
        RECT 510.048 483.608 510.096 483.808 ;
    END
  END t_s[388]
  PIN t_s[389]
    DIRECTION OUTPUT ;
    USE SIGNAL ;
    PORT
      LAYER M5 ;
        RECT 510.192 483.608 510.240 483.808 ;
    END
  END t_s[389]
  PIN t_s[390]
    DIRECTION OUTPUT ;
    USE SIGNAL ;
    PORT
      LAYER M5 ;
        RECT 510.336 483.608 510.384 483.808 ;
    END
  END t_s[390]
  PIN t_s[391]
    DIRECTION OUTPUT ;
    USE SIGNAL ;
    PORT
      LAYER M5 ;
        RECT 510.480 483.608 510.528 483.808 ;
    END
  END t_s[391]
  PIN t_s[392]
    DIRECTION OUTPUT ;
    USE SIGNAL ;
    PORT
      LAYER M5 ;
        RECT 510.624 483.608 510.672 483.808 ;
    END
  END t_s[392]
  PIN t_s[393]
    DIRECTION OUTPUT ;
    USE SIGNAL ;
    PORT
      LAYER M5 ;
        RECT 510.768 483.608 510.816 483.808 ;
    END
  END t_s[393]
  PIN t_s[394]
    DIRECTION OUTPUT ;
    USE SIGNAL ;
    PORT
      LAYER M5 ;
        RECT 510.912 483.608 510.960 483.808 ;
    END
  END t_s[394]
  PIN t_s[395]
    DIRECTION OUTPUT ;
    USE SIGNAL ;
    PORT
      LAYER M5 ;
        RECT 511.056 483.608 511.104 483.808 ;
    END
  END t_s[395]
  PIN t_s[396]
    DIRECTION OUTPUT ;
    USE SIGNAL ;
    PORT
      LAYER M5 ;
        RECT 511.200 483.608 511.248 483.808 ;
    END
  END t_s[396]
  PIN t_s[397]
    DIRECTION OUTPUT ;
    USE SIGNAL ;
    PORT
      LAYER M5 ;
        RECT 511.344 483.608 511.392 483.808 ;
    END
  END t_s[397]
  PIN t_s[398]
    DIRECTION OUTPUT ;
    USE SIGNAL ;
    PORT
      LAYER M5 ;
        RECT 511.488 483.608 511.536 483.808 ;
    END
  END t_s[398]
  PIN t_s[399]
    DIRECTION OUTPUT ;
    USE SIGNAL ;
    PORT
      LAYER M5 ;
        RECT 511.632 483.608 511.680 483.808 ;
    END
  END t_s[399]
  PIN t_s[400]
    DIRECTION OUTPUT ;
    USE SIGNAL ;
    PORT
      LAYER M5 ;
        RECT 511.776 483.608 511.824 483.808 ;
    END
  END t_s[400]
  PIN t_s[401]
    DIRECTION OUTPUT ;
    USE SIGNAL ;
    PORT
      LAYER M5 ;
        RECT 511.920 483.608 511.968 483.808 ;
    END
  END t_s[401]
  PIN t_s[402]
    DIRECTION OUTPUT ;
    USE SIGNAL ;
    PORT
      LAYER M5 ;
        RECT 512.064 483.608 512.112 483.808 ;
    END
  END t_s[402]
  PIN t_s[403]
    DIRECTION OUTPUT ;
    USE SIGNAL ;
    PORT
      LAYER M5 ;
        RECT 512.208 483.608 512.256 483.808 ;
    END
  END t_s[403]
  PIN t_s[404]
    DIRECTION OUTPUT ;
    USE SIGNAL ;
    PORT
      LAYER M5 ;
        RECT 512.352 483.608 512.400 483.808 ;
    END
  END t_s[404]
  PIN t_s[405]
    DIRECTION OUTPUT ;
    USE SIGNAL ;
    PORT
      LAYER M5 ;
        RECT 512.496 483.608 512.544 483.808 ;
    END
  END t_s[405]
  PIN t_s[406]
    DIRECTION OUTPUT ;
    USE SIGNAL ;
    PORT
      LAYER M5 ;
        RECT 512.640 483.608 512.688 483.808 ;
    END
  END t_s[406]
  PIN t_s[407]
    DIRECTION OUTPUT ;
    USE SIGNAL ;
    PORT
      LAYER M5 ;
        RECT 512.784 483.608 512.832 483.808 ;
    END
  END t_s[407]
  PIN t_s[408]
    DIRECTION OUTPUT ;
    USE SIGNAL ;
    PORT
      LAYER M5 ;
        RECT 512.928 483.608 512.976 483.808 ;
    END
  END t_s[408]
  PIN t_s[409]
    DIRECTION OUTPUT ;
    USE SIGNAL ;
    PORT
      LAYER M5 ;
        RECT 513.072 483.608 513.120 483.808 ;
    END
  END t_s[409]
  PIN t_s[410]
    DIRECTION OUTPUT ;
    USE SIGNAL ;
    PORT
      LAYER M5 ;
        RECT 513.216 483.608 513.264 483.808 ;
    END
  END t_s[410]
  PIN t_s[411]
    DIRECTION OUTPUT ;
    USE SIGNAL ;
    PORT
      LAYER M5 ;
        RECT 513.360 483.608 513.408 483.808 ;
    END
  END t_s[411]
  PIN t_s[412]
    DIRECTION OUTPUT ;
    USE SIGNAL ;
    PORT
      LAYER M5 ;
        RECT 513.504 483.608 513.552 483.808 ;
    END
  END t_s[412]
  PIN t_s[413]
    DIRECTION OUTPUT ;
    USE SIGNAL ;
    PORT
      LAYER M5 ;
        RECT 513.648 483.608 513.696 483.808 ;
    END
  END t_s[413]
  PIN t_s[414]
    DIRECTION OUTPUT ;
    USE SIGNAL ;
    PORT
      LAYER M5 ;
        RECT 513.792 483.608 513.840 483.808 ;
    END
  END t_s[414]
  PIN t_s[415]
    DIRECTION OUTPUT ;
    USE SIGNAL ;
    PORT
      LAYER M5 ;
        RECT 513.936 483.608 513.984 483.808 ;
    END
  END t_s[415]
  PIN t_s[416]
    DIRECTION OUTPUT ;
    USE SIGNAL ;
    PORT
      LAYER M5 ;
        RECT 514.080 483.608 514.128 483.808 ;
    END
  END t_s[416]
  PIN t_s[417]
    DIRECTION OUTPUT ;
    USE SIGNAL ;
    PORT
      LAYER M5 ;
        RECT 514.224 483.608 514.272 483.808 ;
    END
  END t_s[417]
  PIN t_s[418]
    DIRECTION OUTPUT ;
    USE SIGNAL ;
    PORT
      LAYER M5 ;
        RECT 514.368 483.608 514.416 483.808 ;
    END
  END t_s[418]
  PIN t_s[419]
    DIRECTION OUTPUT ;
    USE SIGNAL ;
    PORT
      LAYER M5 ;
        RECT 514.512 483.608 514.560 483.808 ;
    END
  END t_s[419]
  PIN t_s[420]
    DIRECTION OUTPUT ;
    USE SIGNAL ;
    PORT
      LAYER M5 ;
        RECT 514.656 483.608 514.704 483.808 ;
    END
  END t_s[420]
  PIN t_s[421]
    DIRECTION OUTPUT ;
    USE SIGNAL ;
    PORT
      LAYER M5 ;
        RECT 514.800 483.608 514.848 483.808 ;
    END
  END t_s[421]
  PIN t_s[422]
    DIRECTION OUTPUT ;
    USE SIGNAL ;
    PORT
      LAYER M5 ;
        RECT 514.944 483.608 514.992 483.808 ;
    END
  END t_s[422]
  PIN t_s[423]
    DIRECTION OUTPUT ;
    USE SIGNAL ;
    PORT
      LAYER M5 ;
        RECT 515.088 483.608 515.136 483.808 ;
    END
  END t_s[423]
  PIN t_s[424]
    DIRECTION OUTPUT ;
    USE SIGNAL ;
    PORT
      LAYER M5 ;
        RECT 515.232 483.608 515.280 483.808 ;
    END
  END t_s[424]
  PIN t_s[425]
    DIRECTION OUTPUT ;
    USE SIGNAL ;
    PORT
      LAYER M5 ;
        RECT 515.376 483.608 515.424 483.808 ;
    END
  END t_s[425]
  PIN t_s[426]
    DIRECTION OUTPUT ;
    USE SIGNAL ;
    PORT
      LAYER M5 ;
        RECT 515.520 483.608 515.568 483.808 ;
    END
  END t_s[426]
  PIN t_s[427]
    DIRECTION OUTPUT ;
    USE SIGNAL ;
    PORT
      LAYER M5 ;
        RECT 515.664 483.608 515.712 483.808 ;
    END
  END t_s[427]
  PIN t_s[428]
    DIRECTION OUTPUT ;
    USE SIGNAL ;
    PORT
      LAYER M5 ;
        RECT 515.808 483.608 515.856 483.808 ;
    END
  END t_s[428]
  PIN t_s[429]
    DIRECTION OUTPUT ;
    USE SIGNAL ;
    PORT
      LAYER M5 ;
        RECT 515.952 483.608 516.000 483.808 ;
    END
  END t_s[429]
  PIN t_s[430]
    DIRECTION OUTPUT ;
    USE SIGNAL ;
    PORT
      LAYER M5 ;
        RECT 516.096 483.608 516.144 483.808 ;
    END
  END t_s[430]
  PIN t_s[431]
    DIRECTION OUTPUT ;
    USE SIGNAL ;
    PORT
      LAYER M5 ;
        RECT 516.240 483.608 516.288 483.808 ;
    END
  END t_s[431]
  PIN t_s[432]
    DIRECTION OUTPUT ;
    USE SIGNAL ;
    PORT
      LAYER M5 ;
        RECT 516.384 483.608 516.432 483.808 ;
    END
  END t_s[432]
  PIN t_s[433]
    DIRECTION OUTPUT ;
    USE SIGNAL ;
    PORT
      LAYER M5 ;
        RECT 516.528 483.608 516.576 483.808 ;
    END
  END t_s[433]
  PIN t_s[434]
    DIRECTION OUTPUT ;
    USE SIGNAL ;
    PORT
      LAYER M5 ;
        RECT 516.672 483.608 516.720 483.808 ;
    END
  END t_s[434]
  PIN t_s[435]
    DIRECTION OUTPUT ;
    USE SIGNAL ;
    PORT
      LAYER M5 ;
        RECT 516.816 483.608 516.864 483.808 ;
    END
  END t_s[435]
  PIN t_s[436]
    DIRECTION OUTPUT ;
    USE SIGNAL ;
    PORT
      LAYER M5 ;
        RECT 516.960 483.608 517.008 483.808 ;
    END
  END t_s[436]
  PIN t_s[437]
    DIRECTION OUTPUT ;
    USE SIGNAL ;
    PORT
      LAYER M5 ;
        RECT 517.104 483.608 517.152 483.808 ;
    END
  END t_s[437]
  PIN t_s[438]
    DIRECTION OUTPUT ;
    USE SIGNAL ;
    PORT
      LAYER M5 ;
        RECT 517.248 483.608 517.296 483.808 ;
    END
  END t_s[438]
  PIN t_s[439]
    DIRECTION OUTPUT ;
    USE SIGNAL ;
    PORT
      LAYER M5 ;
        RECT 517.392 483.608 517.440 483.808 ;
    END
  END t_s[439]
  PIN t_s[440]
    DIRECTION OUTPUT ;
    USE SIGNAL ;
    PORT
      LAYER M5 ;
        RECT 517.536 483.608 517.584 483.808 ;
    END
  END t_s[440]
  PIN t_s[441]
    DIRECTION OUTPUT ;
    USE SIGNAL ;
    PORT
      LAYER M5 ;
        RECT 517.680 483.608 517.728 483.808 ;
    END
  END t_s[441]
  PIN t_s[442]
    DIRECTION OUTPUT ;
    USE SIGNAL ;
    PORT
      LAYER M5 ;
        RECT 517.824 483.608 517.872 483.808 ;
    END
  END t_s[442]
  PIN t_s[443]
    DIRECTION OUTPUT ;
    USE SIGNAL ;
    PORT
      LAYER M5 ;
        RECT 517.968 483.608 518.016 483.808 ;
    END
  END t_s[443]
  PIN t_s[444]
    DIRECTION OUTPUT ;
    USE SIGNAL ;
    PORT
      LAYER M5 ;
        RECT 518.112 483.608 518.160 483.808 ;
    END
  END t_s[444]
  PIN t_s[445]
    DIRECTION OUTPUT ;
    USE SIGNAL ;
    PORT
      LAYER M5 ;
        RECT 518.256 483.608 518.304 483.808 ;
    END
  END t_s[445]
  PIN t_s[446]
    DIRECTION OUTPUT ;
    USE SIGNAL ;
    PORT
      LAYER M5 ;
        RECT 518.400 483.608 518.448 483.808 ;
    END
  END t_s[446]
  PIN t_s[447]
    DIRECTION OUTPUT ;
    USE SIGNAL ;
    PORT
      LAYER M5 ;
        RECT 518.544 483.608 518.592 483.808 ;
    END
  END t_s[447]
  PIN t_s[448]
    DIRECTION OUTPUT ;
    USE SIGNAL ;
    PORT
      LAYER M5 ;
        RECT 518.688 483.608 518.736 483.808 ;
    END
  END t_s[448]
  PIN t_s[449]
    DIRECTION OUTPUT ;
    USE SIGNAL ;
    PORT
      LAYER M5 ;
        RECT 518.832 483.608 518.880 483.808 ;
    END
  END t_s[449]
  PIN t_s[450]
    DIRECTION OUTPUT ;
    USE SIGNAL ;
    PORT
      LAYER M5 ;
        RECT 518.976 483.608 519.024 483.808 ;
    END
  END t_s[450]
  PIN t_s[451]
    DIRECTION OUTPUT ;
    USE SIGNAL ;
    PORT
      LAYER M5 ;
        RECT 519.120 483.608 519.168 483.808 ;
    END
  END t_s[451]
  PIN t_s[452]
    DIRECTION OUTPUT ;
    USE SIGNAL ;
    PORT
      LAYER M5 ;
        RECT 519.264 483.608 519.312 483.808 ;
    END
  END t_s[452]
  PIN t_s[453]
    DIRECTION OUTPUT ;
    USE SIGNAL ;
    PORT
      LAYER M5 ;
        RECT 519.408 483.608 519.456 483.808 ;
    END
  END t_s[453]
  PIN t_s[454]
    DIRECTION OUTPUT ;
    USE SIGNAL ;
    PORT
      LAYER M5 ;
        RECT 519.552 483.608 519.600 483.808 ;
    END
  END t_s[454]
  PIN t_s[455]
    DIRECTION OUTPUT ;
    USE SIGNAL ;
    PORT
      LAYER M5 ;
        RECT 519.696 483.608 519.744 483.808 ;
    END
  END t_s[455]
  PIN t_s[456]
    DIRECTION OUTPUT ;
    USE SIGNAL ;
    PORT
      LAYER M5 ;
        RECT 519.840 483.608 519.888 483.808 ;
    END
  END t_s[456]
  PIN t_s[457]
    DIRECTION OUTPUT ;
    USE SIGNAL ;
    PORT
      LAYER M5 ;
        RECT 519.984 483.608 520.032 483.808 ;
    END
  END t_s[457]
  PIN t_s[458]
    DIRECTION OUTPUT ;
    USE SIGNAL ;
    PORT
      LAYER M5 ;
        RECT 520.128 483.608 520.176 483.808 ;
    END
  END t_s[458]
  PIN t_s[459]
    DIRECTION OUTPUT ;
    USE SIGNAL ;
    PORT
      LAYER M5 ;
        RECT 520.272 483.608 520.320 483.808 ;
    END
  END t_s[459]
  PIN t_s[460]
    DIRECTION OUTPUT ;
    USE SIGNAL ;
    PORT
      LAYER M5 ;
        RECT 520.416 483.608 520.464 483.808 ;
    END
  END t_s[460]
  PIN t_s[461]
    DIRECTION OUTPUT ;
    USE SIGNAL ;
    PORT
      LAYER M5 ;
        RECT 520.560 483.608 520.608 483.808 ;
    END
  END t_s[461]
  PIN t_s[462]
    DIRECTION OUTPUT ;
    USE SIGNAL ;
    PORT
      LAYER M5 ;
        RECT 520.704 483.608 520.752 483.808 ;
    END
  END t_s[462]
  PIN t_s[463]
    DIRECTION OUTPUT ;
    USE SIGNAL ;
    PORT
      LAYER M5 ;
        RECT 520.848 483.608 520.896 483.808 ;
    END
  END t_s[463]
  PIN t_s[464]
    DIRECTION OUTPUT ;
    USE SIGNAL ;
    PORT
      LAYER M5 ;
        RECT 520.992 483.608 521.040 483.808 ;
    END
  END t_s[464]
  PIN t_s[465]
    DIRECTION OUTPUT ;
    USE SIGNAL ;
    PORT
      LAYER M5 ;
        RECT 521.136 483.608 521.184 483.808 ;
    END
  END t_s[465]
  PIN t_s[466]
    DIRECTION OUTPUT ;
    USE SIGNAL ;
    PORT
      LAYER M5 ;
        RECT 521.280 483.608 521.328 483.808 ;
    END
  END t_s[466]
  PIN t_s[467]
    DIRECTION OUTPUT ;
    USE SIGNAL ;
    PORT
      LAYER M5 ;
        RECT 521.424 483.608 521.472 483.808 ;
    END
  END t_s[467]
  PIN t_s[468]
    DIRECTION OUTPUT ;
    USE SIGNAL ;
    PORT
      LAYER M5 ;
        RECT 521.568 483.608 521.616 483.808 ;
    END
  END t_s[468]
  PIN t_s[469]
    DIRECTION OUTPUT ;
    USE SIGNAL ;
    PORT
      LAYER M5 ;
        RECT 521.712 483.608 521.760 483.808 ;
    END
  END t_s[469]
  PIN t_s[470]
    DIRECTION OUTPUT ;
    USE SIGNAL ;
    PORT
      LAYER M5 ;
        RECT 521.856 483.608 521.904 483.808 ;
    END
  END t_s[470]
  PIN t_s[471]
    DIRECTION OUTPUT ;
    USE SIGNAL ;
    PORT
      LAYER M5 ;
        RECT 522.000 483.608 522.048 483.808 ;
    END
  END t_s[471]
  PIN t_s[472]
    DIRECTION OUTPUT ;
    USE SIGNAL ;
    PORT
      LAYER M5 ;
        RECT 522.144 483.608 522.192 483.808 ;
    END
  END t_s[472]
  PIN t_s[473]
    DIRECTION OUTPUT ;
    USE SIGNAL ;
    PORT
      LAYER M5 ;
        RECT 522.288 483.608 522.336 483.808 ;
    END
  END t_s[473]
  PIN t_s[474]
    DIRECTION OUTPUT ;
    USE SIGNAL ;
    PORT
      LAYER M5 ;
        RECT 522.432 483.608 522.480 483.808 ;
    END
  END t_s[474]
  PIN t_s[475]
    DIRECTION OUTPUT ;
    USE SIGNAL ;
    PORT
      LAYER M5 ;
        RECT 522.576 483.608 522.624 483.808 ;
    END
  END t_s[475]
  PIN t_s[476]
    DIRECTION OUTPUT ;
    USE SIGNAL ;
    PORT
      LAYER M5 ;
        RECT 522.720 483.608 522.768 483.808 ;
    END
  END t_s[476]
  PIN t_s[477]
    DIRECTION OUTPUT ;
    USE SIGNAL ;
    PORT
      LAYER M5 ;
        RECT 522.864 483.608 522.912 483.808 ;
    END
  END t_s[477]
  PIN t_s[478]
    DIRECTION OUTPUT ;
    USE SIGNAL ;
    PORT
      LAYER M5 ;
        RECT 523.008 483.608 523.056 483.808 ;
    END
  END t_s[478]
  PIN t_s[479]
    DIRECTION OUTPUT ;
    USE SIGNAL ;
    PORT
      LAYER M5 ;
        RECT 523.152 483.608 523.200 483.808 ;
    END
  END t_s[479]
  PIN t_s[480]
    DIRECTION OUTPUT ;
    USE SIGNAL ;
    PORT
      LAYER M5 ;
        RECT 523.296 483.608 523.344 483.808 ;
    END
  END t_s[480]
  PIN t_s[481]
    DIRECTION OUTPUT ;
    USE SIGNAL ;
    PORT
      LAYER M5 ;
        RECT 523.440 483.608 523.488 483.808 ;
    END
  END t_s[481]
  PIN t_s[482]
    DIRECTION OUTPUT ;
    USE SIGNAL ;
    PORT
      LAYER M5 ;
        RECT 523.584 483.608 523.632 483.808 ;
    END
  END t_s[482]
  PIN t_s[483]
    DIRECTION OUTPUT ;
    USE SIGNAL ;
    PORT
      LAYER M5 ;
        RECT 523.728 483.608 523.776 483.808 ;
    END
  END t_s[483]
  PIN t_s[484]
    DIRECTION OUTPUT ;
    USE SIGNAL ;
    PORT
      LAYER M5 ;
        RECT 523.872 483.608 523.920 483.808 ;
    END
  END t_s[484]
  PIN t_s[485]
    DIRECTION OUTPUT ;
    USE SIGNAL ;
    PORT
      LAYER M5 ;
        RECT 524.016 483.608 524.064 483.808 ;
    END
  END t_s[485]
  PIN t_s[486]
    DIRECTION OUTPUT ;
    USE SIGNAL ;
    PORT
      LAYER M5 ;
        RECT 524.160 483.608 524.208 483.808 ;
    END
  END t_s[486]
  PIN t_s[487]
    DIRECTION OUTPUT ;
    USE SIGNAL ;
    PORT
      LAYER M5 ;
        RECT 524.304 483.608 524.352 483.808 ;
    END
  END t_s[487]
  PIN t_s[488]
    DIRECTION OUTPUT ;
    USE SIGNAL ;
    PORT
      LAYER M5 ;
        RECT 524.448 483.608 524.496 483.808 ;
    END
  END t_s[488]
  PIN t_s[489]
    DIRECTION OUTPUT ;
    USE SIGNAL ;
    PORT
      LAYER M5 ;
        RECT 524.592 483.608 524.640 483.808 ;
    END
  END t_s[489]
  PIN t_s[490]
    DIRECTION OUTPUT ;
    USE SIGNAL ;
    PORT
      LAYER M5 ;
        RECT 524.736 483.608 524.784 483.808 ;
    END
  END t_s[490]
  PIN t_s[491]
    DIRECTION OUTPUT ;
    USE SIGNAL ;
    PORT
      LAYER M5 ;
        RECT 524.880 483.608 524.928 483.808 ;
    END
  END t_s[491]
  PIN t_s[492]
    DIRECTION OUTPUT ;
    USE SIGNAL ;
    PORT
      LAYER M5 ;
        RECT 525.024 483.608 525.072 483.808 ;
    END
  END t_s[492]
  PIN t_s[493]
    DIRECTION OUTPUT ;
    USE SIGNAL ;
    PORT
      LAYER M5 ;
        RECT 525.168 483.608 525.216 483.808 ;
    END
  END t_s[493]
  PIN t_s[494]
    DIRECTION OUTPUT ;
    USE SIGNAL ;
    PORT
      LAYER M5 ;
        RECT 525.312 483.608 525.360 483.808 ;
    END
  END t_s[494]
  PIN t_s[495]
    DIRECTION OUTPUT ;
    USE SIGNAL ;
    PORT
      LAYER M5 ;
        RECT 525.456 483.608 525.504 483.808 ;
    END
  END t_s[495]
  PIN t_s[496]
    DIRECTION OUTPUT ;
    USE SIGNAL ;
    PORT
      LAYER M5 ;
        RECT 525.600 483.608 525.648 483.808 ;
    END
  END t_s[496]
  PIN t_s[497]
    DIRECTION OUTPUT ;
    USE SIGNAL ;
    PORT
      LAYER M5 ;
        RECT 525.744 483.608 525.792 483.808 ;
    END
  END t_s[497]
  PIN t_s[498]
    DIRECTION OUTPUT ;
    USE SIGNAL ;
    PORT
      LAYER M5 ;
        RECT 525.888 483.608 525.936 483.808 ;
    END
  END t_s[498]
  PIN t_s[499]
    DIRECTION OUTPUT ;
    USE SIGNAL ;
    PORT
      LAYER M5 ;
        RECT 526.032 483.608 526.080 483.808 ;
    END
  END t_s[499]
  PIN t_s[500]
    DIRECTION OUTPUT ;
    USE SIGNAL ;
    PORT
      LAYER M5 ;
        RECT 526.176 483.608 526.224 483.808 ;
    END
  END t_s[500]
  PIN t_s[501]
    DIRECTION OUTPUT ;
    USE SIGNAL ;
    PORT
      LAYER M5 ;
        RECT 526.320 483.608 526.368 483.808 ;
    END
  END t_s[501]
  PIN t_s[502]
    DIRECTION OUTPUT ;
    USE SIGNAL ;
    PORT
      LAYER M5 ;
        RECT 526.464 483.608 526.512 483.808 ;
    END
  END t_s[502]
  PIN t_s[503]
    DIRECTION OUTPUT ;
    USE SIGNAL ;
    PORT
      LAYER M5 ;
        RECT 526.608 483.608 526.656 483.808 ;
    END
  END t_s[503]
  PIN t_s[504]
    DIRECTION OUTPUT ;
    USE SIGNAL ;
    PORT
      LAYER M5 ;
        RECT 526.752 483.608 526.800 483.808 ;
    END
  END t_s[504]
  PIN t_s[505]
    DIRECTION OUTPUT ;
    USE SIGNAL ;
    PORT
      LAYER M5 ;
        RECT 526.896 483.608 526.944 483.808 ;
    END
  END t_s[505]
  PIN t_s[506]
    DIRECTION OUTPUT ;
    USE SIGNAL ;
    PORT
      LAYER M5 ;
        RECT 527.040 483.608 527.088 483.808 ;
    END
  END t_s[506]
  PIN t_s[507]
    DIRECTION OUTPUT ;
    USE SIGNAL ;
    PORT
      LAYER M5 ;
        RECT 527.184 483.608 527.232 483.808 ;
    END
  END t_s[507]
  PIN t_s[508]
    DIRECTION OUTPUT ;
    USE SIGNAL ;
    PORT
      LAYER M5 ;
        RECT 527.328 483.608 527.376 483.808 ;
    END
  END t_s[508]
  PIN t_s[509]
    DIRECTION OUTPUT ;
    USE SIGNAL ;
    PORT
      LAYER M5 ;
        RECT 527.472 483.608 527.520 483.808 ;
    END
  END t_s[509]
  PIN t_s[510]
    DIRECTION OUTPUT ;
    USE SIGNAL ;
    PORT
      LAYER M5 ;
        RECT 527.616 483.608 527.664 483.808 ;
    END
  END t_s[510]
  PIN t_s[511]
    DIRECTION OUTPUT ;
    USE SIGNAL ;
    PORT
      LAYER M5 ;
        RECT 527.760 483.608 527.808 483.808 ;
    END
  END t_s[511]
  PIN t_s[512]
    DIRECTION OUTPUT ;
    USE SIGNAL ;
    PORT
      LAYER M5 ;
        RECT 527.904 483.608 527.952 483.808 ;
    END
  END t_s[512]
  PIN t_s[513]
    DIRECTION OUTPUT ;
    USE SIGNAL ;
    PORT
      LAYER M5 ;
        RECT 528.048 483.608 528.096 483.808 ;
    END
  END t_s[513]
  PIN t_s[514]
    DIRECTION OUTPUT ;
    USE SIGNAL ;
    PORT
      LAYER M5 ;
        RECT 528.192 483.608 528.240 483.808 ;
    END
  END t_s[514]
  PIN t_s[515]
    DIRECTION OUTPUT ;
    USE SIGNAL ;
    PORT
      LAYER M5 ;
        RECT 528.336 483.608 528.384 483.808 ;
    END
  END t_s[515]
  PIN t_s[516]
    DIRECTION OUTPUT ;
    USE SIGNAL ;
    PORT
      LAYER M5 ;
        RECT 528.480 483.608 528.528 483.808 ;
    END
  END t_s[516]
  PIN t_s[517]
    DIRECTION OUTPUT ;
    USE SIGNAL ;
    PORT
      LAYER M5 ;
        RECT 528.624 483.608 528.672 483.808 ;
    END
  END t_s[517]
  PIN t_s[518]
    DIRECTION OUTPUT ;
    USE SIGNAL ;
    PORT
      LAYER M5 ;
        RECT 528.768 483.608 528.816 483.808 ;
    END
  END t_s[518]
  PIN t_s[519]
    DIRECTION OUTPUT ;
    USE SIGNAL ;
    PORT
      LAYER M5 ;
        RECT 528.912 483.608 528.960 483.808 ;
    END
  END t_s[519]
  PIN t_s[520]
    DIRECTION OUTPUT ;
    USE SIGNAL ;
    PORT
      LAYER M5 ;
        RECT 529.056 483.608 529.104 483.808 ;
    END
  END t_s[520]
  PIN t_s[521]
    DIRECTION OUTPUT ;
    USE SIGNAL ;
    PORT
      LAYER M5 ;
        RECT 529.200 483.608 529.248 483.808 ;
    END
  END t_s[521]
  PIN t_s[522]
    DIRECTION OUTPUT ;
    USE SIGNAL ;
    PORT
      LAYER M5 ;
        RECT 529.344 483.608 529.392 483.808 ;
    END
  END t_s[522]
  PIN t_s[523]
    DIRECTION OUTPUT ;
    USE SIGNAL ;
    PORT
      LAYER M5 ;
        RECT 529.488 483.608 529.536 483.808 ;
    END
  END t_s[523]
  PIN t_s[524]
    DIRECTION OUTPUT ;
    USE SIGNAL ;
    PORT
      LAYER M5 ;
        RECT 529.632 483.608 529.680 483.808 ;
    END
  END t_s[524]
  PIN t_s[525]
    DIRECTION OUTPUT ;
    USE SIGNAL ;
    PORT
      LAYER M5 ;
        RECT 529.776 483.608 529.824 483.808 ;
    END
  END t_s[525]
  PIN t_s[526]
    DIRECTION OUTPUT ;
    USE SIGNAL ;
    PORT
      LAYER M5 ;
        RECT 529.920 483.608 529.968 483.808 ;
    END
  END t_s[526]
  PIN t_s[527]
    DIRECTION OUTPUT ;
    USE SIGNAL ;
    PORT
      LAYER M5 ;
        RECT 530.064 483.608 530.112 483.808 ;
    END
  END t_s[527]
  PIN t_s[528]
    DIRECTION OUTPUT ;
    USE SIGNAL ;
    PORT
      LAYER M5 ;
        RECT 530.208 483.608 530.256 483.808 ;
    END
  END t_s[528]
  PIN t_s[529]
    DIRECTION OUTPUT ;
    USE SIGNAL ;
    PORT
      LAYER M5 ;
        RECT 530.352 483.608 530.400 483.808 ;
    END
  END t_s[529]
  PIN t_s[530]
    DIRECTION OUTPUT ;
    USE SIGNAL ;
    PORT
      LAYER M5 ;
        RECT 530.496 483.608 530.544 483.808 ;
    END
  END t_s[530]
  PIN t_s[531]
    DIRECTION OUTPUT ;
    USE SIGNAL ;
    PORT
      LAYER M5 ;
        RECT 530.640 483.608 530.688 483.808 ;
    END
  END t_s[531]
  PIN t_s[532]
    DIRECTION OUTPUT ;
    USE SIGNAL ;
    PORT
      LAYER M5 ;
        RECT 530.784 483.608 530.832 483.808 ;
    END
  END t_s[532]
  PIN t_s[533]
    DIRECTION OUTPUT ;
    USE SIGNAL ;
    PORT
      LAYER M5 ;
        RECT 530.928 483.608 530.976 483.808 ;
    END
  END t_s[533]
  PIN t_s[534]
    DIRECTION OUTPUT ;
    USE SIGNAL ;
    PORT
      LAYER M5 ;
        RECT 531.072 483.608 531.120 483.808 ;
    END
  END t_s[534]
  PIN t_s[535]
    DIRECTION OUTPUT ;
    USE SIGNAL ;
    PORT
      LAYER M5 ;
        RECT 531.216 483.608 531.264 483.808 ;
    END
  END t_s[535]
  PIN t_s[536]
    DIRECTION OUTPUT ;
    USE SIGNAL ;
    PORT
      LAYER M5 ;
        RECT 531.360 483.608 531.408 483.808 ;
    END
  END t_s[536]
  PIN t_s[537]
    DIRECTION OUTPUT ;
    USE SIGNAL ;
    PORT
      LAYER M5 ;
        RECT 531.504 483.608 531.552 483.808 ;
    END
  END t_s[537]
  PIN t_s[538]
    DIRECTION OUTPUT ;
    USE SIGNAL ;
    PORT
      LAYER M5 ;
        RECT 531.648 483.608 531.696 483.808 ;
    END
  END t_s[538]
  PIN t_s[539]
    DIRECTION OUTPUT ;
    USE SIGNAL ;
    PORT
      LAYER M5 ;
        RECT 531.792 483.608 531.840 483.808 ;
    END
  END t_s[539]
  PIN t_s[540]
    DIRECTION OUTPUT ;
    USE SIGNAL ;
    PORT
      LAYER M5 ;
        RECT 531.936 483.608 531.984 483.808 ;
    END
  END t_s[540]
  PIN t_s[541]
    DIRECTION OUTPUT ;
    USE SIGNAL ;
    PORT
      LAYER M5 ;
        RECT 532.080 483.608 532.128 483.808 ;
    END
  END t_s[541]
  PIN t_s[542]
    DIRECTION OUTPUT ;
    USE SIGNAL ;
    PORT
      LAYER M5 ;
        RECT 532.224 483.608 532.272 483.808 ;
    END
  END t_s[542]
  PIN t_s[543]
    DIRECTION OUTPUT ;
    USE SIGNAL ;
    PORT
      LAYER M5 ;
        RECT 532.368 483.608 532.416 483.808 ;
    END
  END t_s[543]
  PIN t_s[544]
    DIRECTION OUTPUT ;
    USE SIGNAL ;
    PORT
      LAYER M5 ;
        RECT 532.512 483.608 532.560 483.808 ;
    END
  END t_s[544]
  PIN t_s[545]
    DIRECTION OUTPUT ;
    USE SIGNAL ;
    PORT
      LAYER M5 ;
        RECT 532.656 483.608 532.704 483.808 ;
    END
  END t_s[545]
  PIN t_s[546]
    DIRECTION OUTPUT ;
    USE SIGNAL ;
    PORT
      LAYER M5 ;
        RECT 532.800 483.608 532.848 483.808 ;
    END
  END t_s[546]
  PIN t_s[547]
    DIRECTION OUTPUT ;
    USE SIGNAL ;
    PORT
      LAYER M5 ;
        RECT 532.944 483.608 532.992 483.808 ;
    END
  END t_s[547]
  PIN t_s[548]
    DIRECTION OUTPUT ;
    USE SIGNAL ;
    PORT
      LAYER M5 ;
        RECT 533.088 483.608 533.136 483.808 ;
    END
  END t_s[548]
  PIN t_s[549]
    DIRECTION OUTPUT ;
    USE SIGNAL ;
    PORT
      LAYER M5 ;
        RECT 533.232 483.608 533.280 483.808 ;
    END
  END t_s[549]
  PIN t_s[550]
    DIRECTION OUTPUT ;
    USE SIGNAL ;
    PORT
      LAYER M5 ;
        RECT 533.376 483.608 533.424 483.808 ;
    END
  END t_s[550]
  PIN t_s[551]
    DIRECTION OUTPUT ;
    USE SIGNAL ;
    PORT
      LAYER M5 ;
        RECT 533.520 483.608 533.568 483.808 ;
    END
  END t_s[551]
  PIN t_s[552]
    DIRECTION OUTPUT ;
    USE SIGNAL ;
    PORT
      LAYER M5 ;
        RECT 533.664 483.608 533.712 483.808 ;
    END
  END t_s[552]
  PIN t_s[553]
    DIRECTION OUTPUT ;
    USE SIGNAL ;
    PORT
      LAYER M5 ;
        RECT 533.808 483.608 533.856 483.808 ;
    END
  END t_s[553]
  PIN t_s[554]
    DIRECTION OUTPUT ;
    USE SIGNAL ;
    PORT
      LAYER M5 ;
        RECT 533.952 483.608 534.000 483.808 ;
    END
  END t_s[554]
  PIN t_s[555]
    DIRECTION OUTPUT ;
    USE SIGNAL ;
    PORT
      LAYER M5 ;
        RECT 534.096 483.608 534.144 483.808 ;
    END
  END t_s[555]
  PIN t_s[556]
    DIRECTION OUTPUT ;
    USE SIGNAL ;
    PORT
      LAYER M5 ;
        RECT 534.240 483.608 534.288 483.808 ;
    END
  END t_s[556]
  PIN t_s[557]
    DIRECTION OUTPUT ;
    USE SIGNAL ;
    PORT
      LAYER M5 ;
        RECT 534.384 483.608 534.432 483.808 ;
    END
  END t_s[557]
  PIN t_s[558]
    DIRECTION OUTPUT ;
    USE SIGNAL ;
    PORT
      LAYER M5 ;
        RECT 534.528 483.608 534.576 483.808 ;
    END
  END t_s[558]
  PIN t_s[559]
    DIRECTION OUTPUT ;
    USE SIGNAL ;
    PORT
      LAYER M5 ;
        RECT 534.672 483.608 534.720 483.808 ;
    END
  END t_s[559]
  PIN t_s[560]
    DIRECTION OUTPUT ;
    USE SIGNAL ;
    PORT
      LAYER M5 ;
        RECT 534.816 483.608 534.864 483.808 ;
    END
  END t_s[560]
  PIN t_s[561]
    DIRECTION OUTPUT ;
    USE SIGNAL ;
    PORT
      LAYER M5 ;
        RECT 534.960 483.608 535.008 483.808 ;
    END
  END t_s[561]
  PIN t_s[562]
    DIRECTION OUTPUT ;
    USE SIGNAL ;
    PORT
      LAYER M5 ;
        RECT 535.104 483.608 535.152 483.808 ;
    END
  END t_s[562]
  PIN t_s[563]
    DIRECTION OUTPUT ;
    USE SIGNAL ;
    PORT
      LAYER M5 ;
        RECT 535.248 483.608 535.296 483.808 ;
    END
  END t_s[563]
  PIN t_s[564]
    DIRECTION OUTPUT ;
    USE SIGNAL ;
    PORT
      LAYER M5 ;
        RECT 535.392 483.608 535.440 483.808 ;
    END
  END t_s[564]
  PIN t_s[565]
    DIRECTION OUTPUT ;
    USE SIGNAL ;
    PORT
      LAYER M5 ;
        RECT 535.536 483.608 535.584 483.808 ;
    END
  END t_s[565]
  PIN t_s[566]
    DIRECTION OUTPUT ;
    USE SIGNAL ;
    PORT
      LAYER M5 ;
        RECT 535.680 483.608 535.728 483.808 ;
    END
  END t_s[566]
  PIN t_s[567]
    DIRECTION OUTPUT ;
    USE SIGNAL ;
    PORT
      LAYER M5 ;
        RECT 535.824 483.608 535.872 483.808 ;
    END
  END t_s[567]
  PIN t_s[568]
    DIRECTION OUTPUT ;
    USE SIGNAL ;
    PORT
      LAYER M5 ;
        RECT 535.968 483.608 536.016 483.808 ;
    END
  END t_s[568]
  PIN t_s[569]
    DIRECTION OUTPUT ;
    USE SIGNAL ;
    PORT
      LAYER M5 ;
        RECT 536.112 483.608 536.160 483.808 ;
    END
  END t_s[569]
  PIN t_s[570]
    DIRECTION OUTPUT ;
    USE SIGNAL ;
    PORT
      LAYER M5 ;
        RECT 536.256 483.608 536.304 483.808 ;
    END
  END t_s[570]
  PIN t_s[571]
    DIRECTION OUTPUT ;
    USE SIGNAL ;
    PORT
      LAYER M5 ;
        RECT 536.400 483.608 536.448 483.808 ;
    END
  END t_s[571]
  PIN t_s[572]
    DIRECTION OUTPUT ;
    USE SIGNAL ;
    PORT
      LAYER M5 ;
        RECT 536.544 483.608 536.592 483.808 ;
    END
  END t_s[572]
  PIN t_s[573]
    DIRECTION OUTPUT ;
    USE SIGNAL ;
    PORT
      LAYER M5 ;
        RECT 536.688 483.608 536.736 483.808 ;
    END
  END t_s[573]
  PIN t_s[574]
    DIRECTION OUTPUT ;
    USE SIGNAL ;
    PORT
      LAYER M5 ;
        RECT 536.832 483.608 536.880 483.808 ;
    END
  END t_s[574]
  PIN t_s[575]
    DIRECTION OUTPUT ;
    USE SIGNAL ;
    PORT
      LAYER M5 ;
        RECT 536.976 483.608 537.024 483.808 ;
    END
  END t_s[575]
  PIN t_s[576]
    DIRECTION OUTPUT ;
    USE SIGNAL ;
    PORT
      LAYER M5 ;
        RECT 537.120 483.608 537.168 483.808 ;
    END
  END t_s[576]
  PIN t_s[577]
    DIRECTION OUTPUT ;
    USE SIGNAL ;
    PORT
      LAYER M5 ;
        RECT 537.264 483.608 537.312 483.808 ;
    END
  END t_s[577]
  PIN t_s[578]
    DIRECTION OUTPUT ;
    USE SIGNAL ;
    PORT
      LAYER M5 ;
        RECT 537.408 483.608 537.456 483.808 ;
    END
  END t_s[578]
  PIN t_s[579]
    DIRECTION OUTPUT ;
    USE SIGNAL ;
    PORT
      LAYER M5 ;
        RECT 537.552 483.608 537.600 483.808 ;
    END
  END t_s[579]
  PIN t_s[580]
    DIRECTION OUTPUT ;
    USE SIGNAL ;
    PORT
      LAYER M5 ;
        RECT 537.696 483.608 537.744 483.808 ;
    END
  END t_s[580]
  PIN t_s[581]
    DIRECTION OUTPUT ;
    USE SIGNAL ;
    PORT
      LAYER M5 ;
        RECT 537.840 483.608 537.888 483.808 ;
    END
  END t_s[581]
  PIN t_s[582]
    DIRECTION OUTPUT ;
    USE SIGNAL ;
    PORT
      LAYER M5 ;
        RECT 537.984 483.608 538.032 483.808 ;
    END
  END t_s[582]
  PIN t_s[583]
    DIRECTION OUTPUT ;
    USE SIGNAL ;
    PORT
      LAYER M5 ;
        RECT 538.128 483.608 538.176 483.808 ;
    END
  END t_s[583]
  PIN t_s[584]
    DIRECTION OUTPUT ;
    USE SIGNAL ;
    PORT
      LAYER M5 ;
        RECT 538.272 483.608 538.320 483.808 ;
    END
  END t_s[584]
  PIN t_s[585]
    DIRECTION OUTPUT ;
    USE SIGNAL ;
    PORT
      LAYER M5 ;
        RECT 538.416 483.608 538.464 483.808 ;
    END
  END t_s[585]
  PIN t_s[586]
    DIRECTION OUTPUT ;
    USE SIGNAL ;
    PORT
      LAYER M5 ;
        RECT 538.560 483.608 538.608 483.808 ;
    END
  END t_s[586]
  PIN t_s[587]
    DIRECTION OUTPUT ;
    USE SIGNAL ;
    PORT
      LAYER M5 ;
        RECT 538.704 483.608 538.752 483.808 ;
    END
  END t_s[587]
  PIN t_s[588]
    DIRECTION OUTPUT ;
    USE SIGNAL ;
    PORT
      LAYER M5 ;
        RECT 538.848 483.608 538.896 483.808 ;
    END
  END t_s[588]
  PIN t_s[589]
    DIRECTION OUTPUT ;
    USE SIGNAL ;
    PORT
      LAYER M5 ;
        RECT 538.992 483.608 539.040 483.808 ;
    END
  END t_s[589]
  PIN t_s[590]
    DIRECTION OUTPUT ;
    USE SIGNAL ;
    PORT
      LAYER M5 ;
        RECT 539.136 483.608 539.184 483.808 ;
    END
  END t_s[590]
  PIN t_s[591]
    DIRECTION OUTPUT ;
    USE SIGNAL ;
    PORT
      LAYER M5 ;
        RECT 539.280 483.608 539.328 483.808 ;
    END
  END t_s[591]
  PIN t_s[592]
    DIRECTION OUTPUT ;
    USE SIGNAL ;
    PORT
      LAYER M5 ;
        RECT 539.424 483.608 539.472 483.808 ;
    END
  END t_s[592]
  PIN t_s[593]
    DIRECTION OUTPUT ;
    USE SIGNAL ;
    PORT
      LAYER M5 ;
        RECT 539.568 483.608 539.616 483.808 ;
    END
  END t_s[593]
  PIN t_s[594]
    DIRECTION OUTPUT ;
    USE SIGNAL ;
    PORT
      LAYER M5 ;
        RECT 539.712 483.608 539.760 483.808 ;
    END
  END t_s[594]
  PIN t_s[595]
    DIRECTION OUTPUT ;
    USE SIGNAL ;
    PORT
      LAYER M5 ;
        RECT 539.856 483.608 539.904 483.808 ;
    END
  END t_s[595]
  PIN t_s[596]
    DIRECTION OUTPUT ;
    USE SIGNAL ;
    PORT
      LAYER M5 ;
        RECT 540.000 483.608 540.048 483.808 ;
    END
  END t_s[596]
  PIN t_s[597]
    DIRECTION OUTPUT ;
    USE SIGNAL ;
    PORT
      LAYER M5 ;
        RECT 540.144 483.608 540.192 483.808 ;
    END
  END t_s[597]
  PIN t_s[598]
    DIRECTION OUTPUT ;
    USE SIGNAL ;
    PORT
      LAYER M5 ;
        RECT 540.288 483.608 540.336 483.808 ;
    END
  END t_s[598]
  PIN t_s[599]
    DIRECTION OUTPUT ;
    USE SIGNAL ;
    PORT
      LAYER M5 ;
        RECT 540.432 483.608 540.480 483.808 ;
    END
  END t_s[599]
  PIN t_s[600]
    DIRECTION OUTPUT ;
    USE SIGNAL ;
    PORT
      LAYER M5 ;
        RECT 540.576 483.608 540.624 483.808 ;
    END
  END t_s[600]
  PIN t_s[601]
    DIRECTION OUTPUT ;
    USE SIGNAL ;
    PORT
      LAYER M5 ;
        RECT 540.720 483.608 540.768 483.808 ;
    END
  END t_s[601]
  PIN t_s[602]
    DIRECTION OUTPUT ;
    USE SIGNAL ;
    PORT
      LAYER M5 ;
        RECT 540.864 483.608 540.912 483.808 ;
    END
  END t_s[602]
  PIN t_s[603]
    DIRECTION OUTPUT ;
    USE SIGNAL ;
    PORT
      LAYER M5 ;
        RECT 541.008 483.608 541.056 483.808 ;
    END
  END t_s[603]
  PIN t_s[604]
    DIRECTION OUTPUT ;
    USE SIGNAL ;
    PORT
      LAYER M5 ;
        RECT 541.152 483.608 541.200 483.808 ;
    END
  END t_s[604]
  PIN t_s[605]
    DIRECTION OUTPUT ;
    USE SIGNAL ;
    PORT
      LAYER M5 ;
        RECT 541.296 483.608 541.344 483.808 ;
    END
  END t_s[605]
  PIN t_s[606]
    DIRECTION OUTPUT ;
    USE SIGNAL ;
    PORT
      LAYER M5 ;
        RECT 541.440 483.608 541.488 483.808 ;
    END
  END t_s[606]
  PIN t_s[607]
    DIRECTION OUTPUT ;
    USE SIGNAL ;
    PORT
      LAYER M5 ;
        RECT 541.584 483.608 541.632 483.808 ;
    END
  END t_s[607]
  PIN t_s[608]
    DIRECTION OUTPUT ;
    USE SIGNAL ;
    PORT
      LAYER M5 ;
        RECT 541.728 483.608 541.776 483.808 ;
    END
  END t_s[608]
  PIN t_s[609]
    DIRECTION OUTPUT ;
    USE SIGNAL ;
    PORT
      LAYER M5 ;
        RECT 541.872 483.608 541.920 483.808 ;
    END
  END t_s[609]
  PIN t_s[610]
    DIRECTION OUTPUT ;
    USE SIGNAL ;
    PORT
      LAYER M5 ;
        RECT 542.016 483.608 542.064 483.808 ;
    END
  END t_s[610]
  PIN t_s[611]
    DIRECTION OUTPUT ;
    USE SIGNAL ;
    PORT
      LAYER M5 ;
        RECT 542.160 483.608 542.208 483.808 ;
    END
  END t_s[611]
  PIN t_s[612]
    DIRECTION OUTPUT ;
    USE SIGNAL ;
    PORT
      LAYER M5 ;
        RECT 542.304 483.608 542.352 483.808 ;
    END
  END t_s[612]
  PIN t_s[613]
    DIRECTION OUTPUT ;
    USE SIGNAL ;
    PORT
      LAYER M5 ;
        RECT 542.448 483.608 542.496 483.808 ;
    END
  END t_s[613]
  PIN t_s[614]
    DIRECTION OUTPUT ;
    USE SIGNAL ;
    PORT
      LAYER M5 ;
        RECT 542.592 483.608 542.640 483.808 ;
    END
  END t_s[614]
  PIN t_s[615]
    DIRECTION OUTPUT ;
    USE SIGNAL ;
    PORT
      LAYER M5 ;
        RECT 542.736 483.608 542.784 483.808 ;
    END
  END t_s[615]
  PIN t_s[616]
    DIRECTION OUTPUT ;
    USE SIGNAL ;
    PORT
      LAYER M5 ;
        RECT 542.880 483.608 542.928 483.808 ;
    END
  END t_s[616]
  PIN t_s[617]
    DIRECTION OUTPUT ;
    USE SIGNAL ;
    PORT
      LAYER M5 ;
        RECT 543.024 483.608 543.072 483.808 ;
    END
  END t_s[617]
  PIN t_s[618]
    DIRECTION OUTPUT ;
    USE SIGNAL ;
    PORT
      LAYER M5 ;
        RECT 543.168 483.608 543.216 483.808 ;
    END
  END t_s[618]
  PIN t_s[619]
    DIRECTION OUTPUT ;
    USE SIGNAL ;
    PORT
      LAYER M5 ;
        RECT 543.312 483.608 543.360 483.808 ;
    END
  END t_s[619]
  PIN t_s[620]
    DIRECTION OUTPUT ;
    USE SIGNAL ;
    PORT
      LAYER M5 ;
        RECT 543.456 483.608 543.504 483.808 ;
    END
  END t_s[620]
  PIN t_s[621]
    DIRECTION OUTPUT ;
    USE SIGNAL ;
    PORT
      LAYER M5 ;
        RECT 543.600 483.608 543.648 483.808 ;
    END
  END t_s[621]
  PIN t_s[622]
    DIRECTION OUTPUT ;
    USE SIGNAL ;
    PORT
      LAYER M5 ;
        RECT 543.744 483.608 543.792 483.808 ;
    END
  END t_s[622]
  PIN t_s[623]
    DIRECTION OUTPUT ;
    USE SIGNAL ;
    PORT
      LAYER M5 ;
        RECT 543.888 483.608 543.936 483.808 ;
    END
  END t_s[623]
  PIN t_s[624]
    DIRECTION OUTPUT ;
    USE SIGNAL ;
    PORT
      LAYER M5 ;
        RECT 544.032 483.608 544.080 483.808 ;
    END
  END t_s[624]
  PIN t_s[625]
    DIRECTION OUTPUT ;
    USE SIGNAL ;
    PORT
      LAYER M5 ;
        RECT 544.176 483.608 544.224 483.808 ;
    END
  END t_s[625]
  PIN t_s[626]
    DIRECTION OUTPUT ;
    USE SIGNAL ;
    PORT
      LAYER M5 ;
        RECT 544.320 483.608 544.368 483.808 ;
    END
  END t_s[626]
  PIN t_s[627]
    DIRECTION OUTPUT ;
    USE SIGNAL ;
    PORT
      LAYER M5 ;
        RECT 544.464 483.608 544.512 483.808 ;
    END
  END t_s[627]
  PIN t_s[628]
    DIRECTION OUTPUT ;
    USE SIGNAL ;
    PORT
      LAYER M5 ;
        RECT 544.608 483.608 544.656 483.808 ;
    END
  END t_s[628]
  PIN t_s[629]
    DIRECTION OUTPUT ;
    USE SIGNAL ;
    PORT
      LAYER M5 ;
        RECT 544.752 483.608 544.800 483.808 ;
    END
  END t_s[629]
  PIN t_s[630]
    DIRECTION OUTPUT ;
    USE SIGNAL ;
    PORT
      LAYER M5 ;
        RECT 544.896 483.608 544.944 483.808 ;
    END
  END t_s[630]
  PIN t_s[631]
    DIRECTION OUTPUT ;
    USE SIGNAL ;
    PORT
      LAYER M5 ;
        RECT 545.040 483.608 545.088 483.808 ;
    END
  END t_s[631]
  PIN t_s[632]
    DIRECTION OUTPUT ;
    USE SIGNAL ;
    PORT
      LAYER M5 ;
        RECT 545.184 483.608 545.232 483.808 ;
    END
  END t_s[632]
  PIN t_s[633]
    DIRECTION OUTPUT ;
    USE SIGNAL ;
    PORT
      LAYER M5 ;
        RECT 545.328 483.608 545.376 483.808 ;
    END
  END t_s[633]
  PIN t_s[634]
    DIRECTION OUTPUT ;
    USE SIGNAL ;
    PORT
      LAYER M5 ;
        RECT 545.472 483.608 545.520 483.808 ;
    END
  END t_s[634]
  PIN t_s[635]
    DIRECTION OUTPUT ;
    USE SIGNAL ;
    PORT
      LAYER M5 ;
        RECT 545.616 483.608 545.664 483.808 ;
    END
  END t_s[635]
  PIN t_s[636]
    DIRECTION OUTPUT ;
    USE SIGNAL ;
    PORT
      LAYER M5 ;
        RECT 545.760 483.608 545.808 483.808 ;
    END
  END t_s[636]
  PIN t_s[637]
    DIRECTION OUTPUT ;
    USE SIGNAL ;
    PORT
      LAYER M5 ;
        RECT 545.904 483.608 545.952 483.808 ;
    END
  END t_s[637]
  PIN t_s[638]
    DIRECTION OUTPUT ;
    USE SIGNAL ;
    PORT
      LAYER M5 ;
        RECT 546.048 483.608 546.096 483.808 ;
    END
  END t_s[638]
  PIN t_s[639]
    DIRECTION OUTPUT ;
    USE SIGNAL ;
    PORT
      LAYER M5 ;
        RECT 546.192 483.608 546.240 483.808 ;
    END
  END t_s[639]
  PIN t_s[640]
    DIRECTION OUTPUT ;
    USE SIGNAL ;
    PORT
      LAYER M5 ;
        RECT 546.336 483.608 546.384 483.808 ;
    END
  END t_s[640]
  PIN t_s[641]
    DIRECTION OUTPUT ;
    USE SIGNAL ;
    PORT
      LAYER M5 ;
        RECT 546.480 483.608 546.528 483.808 ;
    END
  END t_s[641]
  PIN t_s[642]
    DIRECTION OUTPUT ;
    USE SIGNAL ;
    PORT
      LAYER M5 ;
        RECT 546.624 483.608 546.672 483.808 ;
    END
  END t_s[642]
  PIN t_s[643]
    DIRECTION OUTPUT ;
    USE SIGNAL ;
    PORT
      LAYER M5 ;
        RECT 546.768 483.608 546.816 483.808 ;
    END
  END t_s[643]
  PIN t_s[644]
    DIRECTION OUTPUT ;
    USE SIGNAL ;
    PORT
      LAYER M5 ;
        RECT 546.912 483.608 546.960 483.808 ;
    END
  END t_s[644]
  PIN t_s[645]
    DIRECTION OUTPUT ;
    USE SIGNAL ;
    PORT
      LAYER M5 ;
        RECT 547.056 483.608 547.104 483.808 ;
    END
  END t_s[645]
  PIN t_s[646]
    DIRECTION OUTPUT ;
    USE SIGNAL ;
    PORT
      LAYER M5 ;
        RECT 547.200 483.608 547.248 483.808 ;
    END
  END t_s[646]
  PIN t_s[647]
    DIRECTION OUTPUT ;
    USE SIGNAL ;
    PORT
      LAYER M5 ;
        RECT 547.344 483.608 547.392 483.808 ;
    END
  END t_s[647]
  PIN t_s[648]
    DIRECTION OUTPUT ;
    USE SIGNAL ;
    PORT
      LAYER M5 ;
        RECT 547.488 483.608 547.536 483.808 ;
    END
  END t_s[648]
  PIN t_s[649]
    DIRECTION OUTPUT ;
    USE SIGNAL ;
    PORT
      LAYER M5 ;
        RECT 547.632 483.608 547.680 483.808 ;
    END
  END t_s[649]
  PIN t_s[650]
    DIRECTION OUTPUT ;
    USE SIGNAL ;
    PORT
      LAYER M5 ;
        RECT 547.776 483.608 547.824 483.808 ;
    END
  END t_s[650]
  PIN t_s[651]
    DIRECTION OUTPUT ;
    USE SIGNAL ;
    PORT
      LAYER M5 ;
        RECT 547.920 483.608 547.968 483.808 ;
    END
  END t_s[651]
  PIN t_s[652]
    DIRECTION OUTPUT ;
    USE SIGNAL ;
    PORT
      LAYER M5 ;
        RECT 548.064 483.608 548.112 483.808 ;
    END
  END t_s[652]
  PIN t_s[653]
    DIRECTION OUTPUT ;
    USE SIGNAL ;
    PORT
      LAYER M5 ;
        RECT 548.208 483.608 548.256 483.808 ;
    END
  END t_s[653]
  PIN t_s[654]
    DIRECTION OUTPUT ;
    USE SIGNAL ;
    PORT
      LAYER M5 ;
        RECT 548.352 483.608 548.400 483.808 ;
    END
  END t_s[654]
  PIN t_s[655]
    DIRECTION OUTPUT ;
    USE SIGNAL ;
    PORT
      LAYER M5 ;
        RECT 548.496 483.608 548.544 483.808 ;
    END
  END t_s[655]
  PIN t_s[656]
    DIRECTION OUTPUT ;
    USE SIGNAL ;
    PORT
      LAYER M5 ;
        RECT 548.640 483.608 548.688 483.808 ;
    END
  END t_s[656]
  PIN t_s[657]
    DIRECTION OUTPUT ;
    USE SIGNAL ;
    PORT
      LAYER M5 ;
        RECT 548.784 483.608 548.832 483.808 ;
    END
  END t_s[657]
  PIN t_s[658]
    DIRECTION OUTPUT ;
    USE SIGNAL ;
    PORT
      LAYER M5 ;
        RECT 548.928 483.608 548.976 483.808 ;
    END
  END t_s[658]
  PIN t_s[659]
    DIRECTION OUTPUT ;
    USE SIGNAL ;
    PORT
      LAYER M5 ;
        RECT 549.072 483.608 549.120 483.808 ;
    END
  END t_s[659]
  PIN t_s[660]
    DIRECTION OUTPUT ;
    USE SIGNAL ;
    PORT
      LAYER M5 ;
        RECT 549.216 483.608 549.264 483.808 ;
    END
  END t_s[660]
  PIN t_s[661]
    DIRECTION OUTPUT ;
    USE SIGNAL ;
    PORT
      LAYER M5 ;
        RECT 549.360 483.608 549.408 483.808 ;
    END
  END t_s[661]
  PIN t_s[662]
    DIRECTION OUTPUT ;
    USE SIGNAL ;
    PORT
      LAYER M5 ;
        RECT 549.504 483.608 549.552 483.808 ;
    END
  END t_s[662]
  PIN t_s[663]
    DIRECTION OUTPUT ;
    USE SIGNAL ;
    PORT
      LAYER M5 ;
        RECT 549.648 483.608 549.696 483.808 ;
    END
  END t_s[663]
  PIN t_s[664]
    DIRECTION OUTPUT ;
    USE SIGNAL ;
    PORT
      LAYER M5 ;
        RECT 549.792 483.608 549.840 483.808 ;
    END
  END t_s[664]
  PIN t_s[665]
    DIRECTION OUTPUT ;
    USE SIGNAL ;
    PORT
      LAYER M5 ;
        RECT 549.936 483.608 549.984 483.808 ;
    END
  END t_s[665]
  PIN t_s[666]
    DIRECTION OUTPUT ;
    USE SIGNAL ;
    PORT
      LAYER M5 ;
        RECT 550.080 483.608 550.128 483.808 ;
    END
  END t_s[666]
  PIN t_s[667]
    DIRECTION OUTPUT ;
    USE SIGNAL ;
    PORT
      LAYER M5 ;
        RECT 550.224 483.608 550.272 483.808 ;
    END
  END t_s[667]
  PIN t_s[668]
    DIRECTION OUTPUT ;
    USE SIGNAL ;
    PORT
      LAYER M5 ;
        RECT 550.368 483.608 550.416 483.808 ;
    END
  END t_s[668]
  PIN t_s[669]
    DIRECTION OUTPUT ;
    USE SIGNAL ;
    PORT
      LAYER M5 ;
        RECT 550.512 483.608 550.560 483.808 ;
    END
  END t_s[669]
  PIN t_s[670]
    DIRECTION OUTPUT ;
    USE SIGNAL ;
    PORT
      LAYER M5 ;
        RECT 550.656 483.608 550.704 483.808 ;
    END
  END t_s[670]
  PIN t_s[671]
    DIRECTION OUTPUT ;
    USE SIGNAL ;
    PORT
      LAYER M5 ;
        RECT 550.800 483.608 550.848 483.808 ;
    END
  END t_s[671]
  PIN t_s[672]
    DIRECTION OUTPUT ;
    USE SIGNAL ;
    PORT
      LAYER M5 ;
        RECT 550.944 483.608 550.992 483.808 ;
    END
  END t_s[672]
  PIN t_s[673]
    DIRECTION OUTPUT ;
    USE SIGNAL ;
    PORT
      LAYER M5 ;
        RECT 551.088 483.608 551.136 483.808 ;
    END
  END t_s[673]
  PIN t_s[674]
    DIRECTION OUTPUT ;
    USE SIGNAL ;
    PORT
      LAYER M5 ;
        RECT 551.232 483.608 551.280 483.808 ;
    END
  END t_s[674]
  PIN t_s[675]
    DIRECTION OUTPUT ;
    USE SIGNAL ;
    PORT
      LAYER M5 ;
        RECT 551.376 483.608 551.424 483.808 ;
    END
  END t_s[675]
  PIN t_s[676]
    DIRECTION OUTPUT ;
    USE SIGNAL ;
    PORT
      LAYER M5 ;
        RECT 551.520 483.608 551.568 483.808 ;
    END
  END t_s[676]
  PIN t_s[677]
    DIRECTION OUTPUT ;
    USE SIGNAL ;
    PORT
      LAYER M5 ;
        RECT 551.664 483.608 551.712 483.808 ;
    END
  END t_s[677]
  PIN t_s[678]
    DIRECTION OUTPUT ;
    USE SIGNAL ;
    PORT
      LAYER M5 ;
        RECT 551.808 483.608 551.856 483.808 ;
    END
  END t_s[678]
  PIN t_s[679]
    DIRECTION OUTPUT ;
    USE SIGNAL ;
    PORT
      LAYER M5 ;
        RECT 551.952 483.608 552.000 483.808 ;
    END
  END t_s[679]
  PIN t_s[680]
    DIRECTION OUTPUT ;
    USE SIGNAL ;
    PORT
      LAYER M5 ;
        RECT 552.096 483.608 552.144 483.808 ;
    END
  END t_s[680]
  PIN t_s[681]
    DIRECTION OUTPUT ;
    USE SIGNAL ;
    PORT
      LAYER M5 ;
        RECT 552.240 483.608 552.288 483.808 ;
    END
  END t_s[681]
  PIN t_s[682]
    DIRECTION OUTPUT ;
    USE SIGNAL ;
    PORT
      LAYER M5 ;
        RECT 552.384 483.608 552.432 483.808 ;
    END
  END t_s[682]
  PIN t_s[683]
    DIRECTION OUTPUT ;
    USE SIGNAL ;
    PORT
      LAYER M5 ;
        RECT 552.528 483.608 552.576 483.808 ;
    END
  END t_s[683]
  PIN t_s[684]
    DIRECTION OUTPUT ;
    USE SIGNAL ;
    PORT
      LAYER M5 ;
        RECT 552.672 483.608 552.720 483.808 ;
    END
  END t_s[684]
  PIN t_s[685]
    DIRECTION OUTPUT ;
    USE SIGNAL ;
    PORT
      LAYER M5 ;
        RECT 552.816 483.608 552.864 483.808 ;
    END
  END t_s[685]
  PIN t_s[686]
    DIRECTION OUTPUT ;
    USE SIGNAL ;
    PORT
      LAYER M5 ;
        RECT 552.960 483.608 553.008 483.808 ;
    END
  END t_s[686]
  PIN t_s[687]
    DIRECTION OUTPUT ;
    USE SIGNAL ;
    PORT
      LAYER M5 ;
        RECT 553.104 483.608 553.152 483.808 ;
    END
  END t_s[687]
  PIN t_s[688]
    DIRECTION OUTPUT ;
    USE SIGNAL ;
    PORT
      LAYER M5 ;
        RECT 553.248 483.608 553.296 483.808 ;
    END
  END t_s[688]
  PIN t_s[689]
    DIRECTION OUTPUT ;
    USE SIGNAL ;
    PORT
      LAYER M5 ;
        RECT 553.392 483.608 553.440 483.808 ;
    END
  END t_s[689]
  PIN t_s[690]
    DIRECTION OUTPUT ;
    USE SIGNAL ;
    PORT
      LAYER M5 ;
        RECT 553.536 483.608 553.584 483.808 ;
    END
  END t_s[690]
  PIN t_s[691]
    DIRECTION OUTPUT ;
    USE SIGNAL ;
    PORT
      LAYER M5 ;
        RECT 553.680 483.608 553.728 483.808 ;
    END
  END t_s[691]
  PIN t_s[692]
    DIRECTION OUTPUT ;
    USE SIGNAL ;
    PORT
      LAYER M5 ;
        RECT 553.824 483.608 553.872 483.808 ;
    END
  END t_s[692]
  PIN t_s[693]
    DIRECTION OUTPUT ;
    USE SIGNAL ;
    PORT
      LAYER M5 ;
        RECT 553.968 483.608 554.016 483.808 ;
    END
  END t_s[693]
  PIN t_s[694]
    DIRECTION OUTPUT ;
    USE SIGNAL ;
    PORT
      LAYER M5 ;
        RECT 554.112 483.608 554.160 483.808 ;
    END
  END t_s[694]
  PIN t_s[695]
    DIRECTION OUTPUT ;
    USE SIGNAL ;
    PORT
      LAYER M5 ;
        RECT 554.256 483.608 554.304 483.808 ;
    END
  END t_s[695]
  PIN t_s[696]
    DIRECTION OUTPUT ;
    USE SIGNAL ;
    PORT
      LAYER M5 ;
        RECT 554.400 483.608 554.448 483.808 ;
    END
  END t_s[696]
  PIN t_s[697]
    DIRECTION OUTPUT ;
    USE SIGNAL ;
    PORT
      LAYER M5 ;
        RECT 554.544 483.608 554.592 483.808 ;
    END
  END t_s[697]
  PIN t_s[698]
    DIRECTION OUTPUT ;
    USE SIGNAL ;
    PORT
      LAYER M5 ;
        RECT 554.688 483.608 554.736 483.808 ;
    END
  END t_s[698]
  PIN t_s[699]
    DIRECTION OUTPUT ;
    USE SIGNAL ;
    PORT
      LAYER M5 ;
        RECT 554.832 483.608 554.880 483.808 ;
    END
  END t_s[699]
  PIN t_s[700]
    DIRECTION OUTPUT ;
    USE SIGNAL ;
    PORT
      LAYER M5 ;
        RECT 554.976 483.608 555.024 483.808 ;
    END
  END t_s[700]
  PIN t_s[701]
    DIRECTION OUTPUT ;
    USE SIGNAL ;
    PORT
      LAYER M5 ;
        RECT 555.120 483.608 555.168 483.808 ;
    END
  END t_s[701]
  PIN t_s[702]
    DIRECTION OUTPUT ;
    USE SIGNAL ;
    PORT
      LAYER M5 ;
        RECT 555.264 483.608 555.312 483.808 ;
    END
  END t_s[702]
  PIN t_s[703]
    DIRECTION OUTPUT ;
    USE SIGNAL ;
    PORT
      LAYER M5 ;
        RECT 555.408 483.608 555.456 483.808 ;
    END
  END t_s[703]
  PIN t_s[704]
    DIRECTION OUTPUT ;
    USE SIGNAL ;
    PORT
      LAYER M5 ;
        RECT 555.552 483.608 555.600 483.808 ;
    END
  END t_s[704]
  PIN t_s[705]
    DIRECTION OUTPUT ;
    USE SIGNAL ;
    PORT
      LAYER M5 ;
        RECT 555.696 483.608 555.744 483.808 ;
    END
  END t_s[705]
  PIN t_s[706]
    DIRECTION OUTPUT ;
    USE SIGNAL ;
    PORT
      LAYER M5 ;
        RECT 555.840 483.608 555.888 483.808 ;
    END
  END t_s[706]
  PIN t_s[707]
    DIRECTION OUTPUT ;
    USE SIGNAL ;
    PORT
      LAYER M5 ;
        RECT 555.984 483.608 556.032 483.808 ;
    END
  END t_s[707]
  PIN t_s[708]
    DIRECTION OUTPUT ;
    USE SIGNAL ;
    PORT
      LAYER M5 ;
        RECT 556.128 483.608 556.176 483.808 ;
    END
  END t_s[708]
  PIN t_s[709]
    DIRECTION OUTPUT ;
    USE SIGNAL ;
    PORT
      LAYER M5 ;
        RECT 556.272 483.608 556.320 483.808 ;
    END
  END t_s[709]
  PIN t_s[710]
    DIRECTION OUTPUT ;
    USE SIGNAL ;
    PORT
      LAYER M5 ;
        RECT 556.416 483.608 556.464 483.808 ;
    END
  END t_s[710]
  PIN t_s[711]
    DIRECTION OUTPUT ;
    USE SIGNAL ;
    PORT
      LAYER M5 ;
        RECT 556.560 483.608 556.608 483.808 ;
    END
  END t_s[711]
  PIN t_s[712]
    DIRECTION OUTPUT ;
    USE SIGNAL ;
    PORT
      LAYER M5 ;
        RECT 556.704 483.608 556.752 483.808 ;
    END
  END t_s[712]
  PIN t_s[713]
    DIRECTION OUTPUT ;
    USE SIGNAL ;
    PORT
      LAYER M5 ;
        RECT 556.848 483.608 556.896 483.808 ;
    END
  END t_s[713]
  PIN t_s[714]
    DIRECTION OUTPUT ;
    USE SIGNAL ;
    PORT
      LAYER M5 ;
        RECT 556.992 483.608 557.040 483.808 ;
    END
  END t_s[714]
  PIN t_s[715]
    DIRECTION OUTPUT ;
    USE SIGNAL ;
    PORT
      LAYER M5 ;
        RECT 557.136 483.608 557.184 483.808 ;
    END
  END t_s[715]
  PIN t_s[716]
    DIRECTION OUTPUT ;
    USE SIGNAL ;
    PORT
      LAYER M5 ;
        RECT 557.280 483.608 557.328 483.808 ;
    END
  END t_s[716]
  PIN t_s[717]
    DIRECTION OUTPUT ;
    USE SIGNAL ;
    PORT
      LAYER M5 ;
        RECT 557.424 483.608 557.472 483.808 ;
    END
  END t_s[717]
  PIN t_s[718]
    DIRECTION OUTPUT ;
    USE SIGNAL ;
    PORT
      LAYER M5 ;
        RECT 557.568 483.608 557.616 483.808 ;
    END
  END t_s[718]
  PIN t_s[719]
    DIRECTION OUTPUT ;
    USE SIGNAL ;
    PORT
      LAYER M5 ;
        RECT 557.712 483.608 557.760 483.808 ;
    END
  END t_s[719]
  PIN t_s[720]
    DIRECTION OUTPUT ;
    USE SIGNAL ;
    PORT
      LAYER M5 ;
        RECT 557.856 483.608 557.904 483.808 ;
    END
  END t_s[720]
  PIN t_s[721]
    DIRECTION OUTPUT ;
    USE SIGNAL ;
    PORT
      LAYER M5 ;
        RECT 558.000 483.608 558.048 483.808 ;
    END
  END t_s[721]
  PIN t_s[722]
    DIRECTION OUTPUT ;
    USE SIGNAL ;
    PORT
      LAYER M5 ;
        RECT 558.144 483.608 558.192 483.808 ;
    END
  END t_s[722]
  PIN t_s[723]
    DIRECTION OUTPUT ;
    USE SIGNAL ;
    PORT
      LAYER M5 ;
        RECT 558.288 483.608 558.336 483.808 ;
    END
  END t_s[723]
  PIN t_s[724]
    DIRECTION OUTPUT ;
    USE SIGNAL ;
    PORT
      LAYER M5 ;
        RECT 558.432 483.608 558.480 483.808 ;
    END
  END t_s[724]
  PIN t_s[725]
    DIRECTION OUTPUT ;
    USE SIGNAL ;
    PORT
      LAYER M5 ;
        RECT 558.576 483.608 558.624 483.808 ;
    END
  END t_s[725]
  PIN t_s[726]
    DIRECTION OUTPUT ;
    USE SIGNAL ;
    PORT
      LAYER M5 ;
        RECT 558.720 483.608 558.768 483.808 ;
    END
  END t_s[726]
  PIN t_s[727]
    DIRECTION OUTPUT ;
    USE SIGNAL ;
    PORT
      LAYER M5 ;
        RECT 558.864 483.608 558.912 483.808 ;
    END
  END t_s[727]
  PIN t_s[728]
    DIRECTION OUTPUT ;
    USE SIGNAL ;
    PORT
      LAYER M5 ;
        RECT 559.008 483.608 559.056 483.808 ;
    END
  END t_s[728]
  PIN t_s[729]
    DIRECTION OUTPUT ;
    USE SIGNAL ;
    PORT
      LAYER M5 ;
        RECT 559.152 483.608 559.200 483.808 ;
    END
  END t_s[729]
  PIN t_s[730]
    DIRECTION OUTPUT ;
    USE SIGNAL ;
    PORT
      LAYER M5 ;
        RECT 559.296 483.608 559.344 483.808 ;
    END
  END t_s[730]
  PIN t_s[731]
    DIRECTION OUTPUT ;
    USE SIGNAL ;
    PORT
      LAYER M5 ;
        RECT 559.440 483.608 559.488 483.808 ;
    END
  END t_s[731]
  PIN t_s[732]
    DIRECTION OUTPUT ;
    USE SIGNAL ;
    PORT
      LAYER M5 ;
        RECT 559.584 483.608 559.632 483.808 ;
    END
  END t_s[732]
  PIN t_s[733]
    DIRECTION OUTPUT ;
    USE SIGNAL ;
    PORT
      LAYER M5 ;
        RECT 559.728 483.608 559.776 483.808 ;
    END
  END t_s[733]
  PIN t_s[734]
    DIRECTION OUTPUT ;
    USE SIGNAL ;
    PORT
      LAYER M5 ;
        RECT 559.872 483.608 559.920 483.808 ;
    END
  END t_s[734]
  PIN t_s[735]
    DIRECTION OUTPUT ;
    USE SIGNAL ;
    PORT
      LAYER M5 ;
        RECT 560.016 483.608 560.064 483.808 ;
    END
  END t_s[735]
  PIN t_s[736]
    DIRECTION OUTPUT ;
    USE SIGNAL ;
    PORT
      LAYER M5 ;
        RECT 560.160 483.608 560.208 483.808 ;
    END
  END t_s[736]
  PIN t_s[737]
    DIRECTION OUTPUT ;
    USE SIGNAL ;
    PORT
      LAYER M5 ;
        RECT 560.304 483.608 560.352 483.808 ;
    END
  END t_s[737]
  PIN t_s[738]
    DIRECTION OUTPUT ;
    USE SIGNAL ;
    PORT
      LAYER M5 ;
        RECT 560.448 483.608 560.496 483.808 ;
    END
  END t_s[738]
  PIN t_s[739]
    DIRECTION OUTPUT ;
    USE SIGNAL ;
    PORT
      LAYER M5 ;
        RECT 560.592 483.608 560.640 483.808 ;
    END
  END t_s[739]
  PIN t_s[740]
    DIRECTION OUTPUT ;
    USE SIGNAL ;
    PORT
      LAYER M5 ;
        RECT 560.736 483.608 560.784 483.808 ;
    END
  END t_s[740]
  PIN t_s[741]
    DIRECTION OUTPUT ;
    USE SIGNAL ;
    PORT
      LAYER M5 ;
        RECT 560.880 483.608 560.928 483.808 ;
    END
  END t_s[741]
  PIN t_s[742]
    DIRECTION OUTPUT ;
    USE SIGNAL ;
    PORT
      LAYER M5 ;
        RECT 561.024 483.608 561.072 483.808 ;
    END
  END t_s[742]
  PIN t_s[743]
    DIRECTION OUTPUT ;
    USE SIGNAL ;
    PORT
      LAYER M5 ;
        RECT 561.168 483.608 561.216 483.808 ;
    END
  END t_s[743]
  PIN t_s[744]
    DIRECTION OUTPUT ;
    USE SIGNAL ;
    PORT
      LAYER M5 ;
        RECT 561.312 483.608 561.360 483.808 ;
    END
  END t_s[744]
  PIN t_s[745]
    DIRECTION OUTPUT ;
    USE SIGNAL ;
    PORT
      LAYER M5 ;
        RECT 561.456 483.608 561.504 483.808 ;
    END
  END t_s[745]
  PIN t_s[746]
    DIRECTION OUTPUT ;
    USE SIGNAL ;
    PORT
      LAYER M5 ;
        RECT 561.600 483.608 561.648 483.808 ;
    END
  END t_s[746]
  PIN t_s[747]
    DIRECTION OUTPUT ;
    USE SIGNAL ;
    PORT
      LAYER M5 ;
        RECT 561.744 483.608 561.792 483.808 ;
    END
  END t_s[747]
  PIN t_s[748]
    DIRECTION OUTPUT ;
    USE SIGNAL ;
    PORT
      LAYER M5 ;
        RECT 561.888 483.608 561.936 483.808 ;
    END
  END t_s[748]
  PIN t_s[749]
    DIRECTION OUTPUT ;
    USE SIGNAL ;
    PORT
      LAYER M5 ;
        RECT 562.032 483.608 562.080 483.808 ;
    END
  END t_s[749]
  PIN t_s[750]
    DIRECTION OUTPUT ;
    USE SIGNAL ;
    PORT
      LAYER M5 ;
        RECT 562.176 483.608 562.224 483.808 ;
    END
  END t_s[750]
  PIN t_s[751]
    DIRECTION OUTPUT ;
    USE SIGNAL ;
    PORT
      LAYER M5 ;
        RECT 562.320 483.608 562.368 483.808 ;
    END
  END t_s[751]
  PIN t_s[752]
    DIRECTION OUTPUT ;
    USE SIGNAL ;
    PORT
      LAYER M5 ;
        RECT 562.464 483.608 562.512 483.808 ;
    END
  END t_s[752]
  PIN t_s[753]
    DIRECTION OUTPUT ;
    USE SIGNAL ;
    PORT
      LAYER M5 ;
        RECT 562.608 483.608 562.656 483.808 ;
    END
  END t_s[753]
  PIN t_s[754]
    DIRECTION OUTPUT ;
    USE SIGNAL ;
    PORT
      LAYER M5 ;
        RECT 562.752 483.608 562.800 483.808 ;
    END
  END t_s[754]
  PIN t_s[755]
    DIRECTION OUTPUT ;
    USE SIGNAL ;
    PORT
      LAYER M5 ;
        RECT 562.896 483.608 562.944 483.808 ;
    END
  END t_s[755]
  PIN t_s[756]
    DIRECTION OUTPUT ;
    USE SIGNAL ;
    PORT
      LAYER M5 ;
        RECT 563.040 483.608 563.088 483.808 ;
    END
  END t_s[756]
  PIN t_s[757]
    DIRECTION OUTPUT ;
    USE SIGNAL ;
    PORT
      LAYER M5 ;
        RECT 563.184 483.608 563.232 483.808 ;
    END
  END t_s[757]
  PIN t_s[758]
    DIRECTION OUTPUT ;
    USE SIGNAL ;
    PORT
      LAYER M5 ;
        RECT 563.328 483.608 563.376 483.808 ;
    END
  END t_s[758]
  PIN t_s[759]
    DIRECTION OUTPUT ;
    USE SIGNAL ;
    PORT
      LAYER M5 ;
        RECT 563.472 483.608 563.520 483.808 ;
    END
  END t_s[759]
  PIN t_s[760]
    DIRECTION OUTPUT ;
    USE SIGNAL ;
    PORT
      LAYER M5 ;
        RECT 563.616 483.608 563.664 483.808 ;
    END
  END t_s[760]
  PIN t_s[761]
    DIRECTION OUTPUT ;
    USE SIGNAL ;
    PORT
      LAYER M5 ;
        RECT 563.760 483.608 563.808 483.808 ;
    END
  END t_s[761]
  PIN t_s[762]
    DIRECTION OUTPUT ;
    USE SIGNAL ;
    PORT
      LAYER M5 ;
        RECT 563.904 483.608 563.952 483.808 ;
    END
  END t_s[762]
  PIN t_s[763]
    DIRECTION OUTPUT ;
    USE SIGNAL ;
    PORT
      LAYER M5 ;
        RECT 564.048 483.608 564.096 483.808 ;
    END
  END t_s[763]
  PIN t_s[764]
    DIRECTION OUTPUT ;
    USE SIGNAL ;
    PORT
      LAYER M5 ;
        RECT 564.192 483.608 564.240 483.808 ;
    END
  END t_s[764]
  PIN t_s[765]
    DIRECTION OUTPUT ;
    USE SIGNAL ;
    PORT
      LAYER M5 ;
        RECT 564.336 483.608 564.384 483.808 ;
    END
  END t_s[765]
  PIN t_s[766]
    DIRECTION OUTPUT ;
    USE SIGNAL ;
    PORT
      LAYER M5 ;
        RECT 564.480 483.608 564.528 483.808 ;
    END
  END t_s[766]
  PIN t_s[767]
    DIRECTION OUTPUT ;
    USE SIGNAL ;
    PORT
      LAYER M5 ;
        RECT 564.624 483.608 564.672 483.808 ;
    END
  END t_s[767]
  PIN t_s[768]
    DIRECTION OUTPUT ;
    USE SIGNAL ;
    PORT
      LAYER M5 ;
        RECT 564.768 483.608 564.816 483.808 ;
    END
  END t_s[768]
  PIN t_s[769]
    DIRECTION OUTPUT ;
    USE SIGNAL ;
    PORT
      LAYER M5 ;
        RECT 564.912 483.608 564.960 483.808 ;
    END
  END t_s[769]
  PIN t_s[770]
    DIRECTION OUTPUT ;
    USE SIGNAL ;
    PORT
      LAYER M5 ;
        RECT 565.056 483.608 565.104 483.808 ;
    END
  END t_s[770]
  PIN t_s[771]
    DIRECTION OUTPUT ;
    USE SIGNAL ;
    PORT
      LAYER M5 ;
        RECT 565.200 483.608 565.248 483.808 ;
    END
  END t_s[771]
  PIN t_s[772]
    DIRECTION OUTPUT ;
    USE SIGNAL ;
    PORT
      LAYER M5 ;
        RECT 565.344 483.608 565.392 483.808 ;
    END
  END t_s[772]
  PIN t_s[773]
    DIRECTION OUTPUT ;
    USE SIGNAL ;
    PORT
      LAYER M5 ;
        RECT 565.488 483.608 565.536 483.808 ;
    END
  END t_s[773]
  PIN t_s[774]
    DIRECTION OUTPUT ;
    USE SIGNAL ;
    PORT
      LAYER M5 ;
        RECT 565.632 483.608 565.680 483.808 ;
    END
  END t_s[774]
  PIN t_s[775]
    DIRECTION OUTPUT ;
    USE SIGNAL ;
    PORT
      LAYER M5 ;
        RECT 565.776 483.608 565.824 483.808 ;
    END
  END t_s[775]
  PIN t_s[776]
    DIRECTION OUTPUT ;
    USE SIGNAL ;
    PORT
      LAYER M5 ;
        RECT 565.920 483.608 565.968 483.808 ;
    END
  END t_s[776]
  PIN t_s[777]
    DIRECTION OUTPUT ;
    USE SIGNAL ;
    PORT
      LAYER M5 ;
        RECT 566.064 483.608 566.112 483.808 ;
    END
  END t_s[777]
  PIN t_s[778]
    DIRECTION OUTPUT ;
    USE SIGNAL ;
    PORT
      LAYER M5 ;
        RECT 566.208 483.608 566.256 483.808 ;
    END
  END t_s[778]
  PIN t_s[779]
    DIRECTION OUTPUT ;
    USE SIGNAL ;
    PORT
      LAYER M5 ;
        RECT 566.352 483.608 566.400 483.808 ;
    END
  END t_s[779]
  PIN t_s[780]
    DIRECTION OUTPUT ;
    USE SIGNAL ;
    PORT
      LAYER M5 ;
        RECT 566.496 483.608 566.544 483.808 ;
    END
  END t_s[780]
  PIN t_s[781]
    DIRECTION OUTPUT ;
    USE SIGNAL ;
    PORT
      LAYER M5 ;
        RECT 566.640 483.608 566.688 483.808 ;
    END
  END t_s[781]
  PIN t_s[782]
    DIRECTION OUTPUT ;
    USE SIGNAL ;
    PORT
      LAYER M5 ;
        RECT 566.784 483.608 566.832 483.808 ;
    END
  END t_s[782]
  PIN t_s[783]
    DIRECTION OUTPUT ;
    USE SIGNAL ;
    PORT
      LAYER M5 ;
        RECT 566.928 483.608 566.976 483.808 ;
    END
  END t_s[783]
  PIN t_s[784]
    DIRECTION OUTPUT ;
    USE SIGNAL ;
    PORT
      LAYER M5 ;
        RECT 567.072 483.608 567.120 483.808 ;
    END
  END t_s[784]
  PIN t_s[785]
    DIRECTION OUTPUT ;
    USE SIGNAL ;
    PORT
      LAYER M5 ;
        RECT 567.216 483.608 567.264 483.808 ;
    END
  END t_s[785]
  PIN t_s[786]
    DIRECTION OUTPUT ;
    USE SIGNAL ;
    PORT
      LAYER M5 ;
        RECT 567.360 483.608 567.408 483.808 ;
    END
  END t_s[786]
  PIN t_s[787]
    DIRECTION OUTPUT ;
    USE SIGNAL ;
    PORT
      LAYER M5 ;
        RECT 567.504 483.608 567.552 483.808 ;
    END
  END t_s[787]
  PIN t_s[788]
    DIRECTION OUTPUT ;
    USE SIGNAL ;
    PORT
      LAYER M5 ;
        RECT 567.648 483.608 567.696 483.808 ;
    END
  END t_s[788]
  PIN t_s[789]
    DIRECTION OUTPUT ;
    USE SIGNAL ;
    PORT
      LAYER M5 ;
        RECT 567.792 483.608 567.840 483.808 ;
    END
  END t_s[789]
  PIN t_s[790]
    DIRECTION OUTPUT ;
    USE SIGNAL ;
    PORT
      LAYER M5 ;
        RECT 567.936 483.608 567.984 483.808 ;
    END
  END t_s[790]
  PIN t_s[791]
    DIRECTION OUTPUT ;
    USE SIGNAL ;
    PORT
      LAYER M5 ;
        RECT 568.080 483.608 568.128 483.808 ;
    END
  END t_s[791]
  PIN t_s[792]
    DIRECTION OUTPUT ;
    USE SIGNAL ;
    PORT
      LAYER M5 ;
        RECT 568.224 483.608 568.272 483.808 ;
    END
  END t_s[792]
  PIN t_s[793]
    DIRECTION OUTPUT ;
    USE SIGNAL ;
    PORT
      LAYER M5 ;
        RECT 568.368 483.608 568.416 483.808 ;
    END
  END t_s[793]
  PIN t_s[794]
    DIRECTION OUTPUT ;
    USE SIGNAL ;
    PORT
      LAYER M5 ;
        RECT 568.512 483.608 568.560 483.808 ;
    END
  END t_s[794]
  PIN t_s[795]
    DIRECTION OUTPUT ;
    USE SIGNAL ;
    PORT
      LAYER M5 ;
        RECT 568.656 483.608 568.704 483.808 ;
    END
  END t_s[795]
  PIN t_s[796]
    DIRECTION OUTPUT ;
    USE SIGNAL ;
    PORT
      LAYER M5 ;
        RECT 568.800 483.608 568.848 483.808 ;
    END
  END t_s[796]
  PIN t_s[797]
    DIRECTION OUTPUT ;
    USE SIGNAL ;
    PORT
      LAYER M5 ;
        RECT 568.944 483.608 568.992 483.808 ;
    END
  END t_s[797]
  PIN t_s[798]
    DIRECTION OUTPUT ;
    USE SIGNAL ;
    PORT
      LAYER M5 ;
        RECT 569.088 483.608 569.136 483.808 ;
    END
  END t_s[798]
  PIN t_s[799]
    DIRECTION OUTPUT ;
    USE SIGNAL ;
    PORT
      LAYER M5 ;
        RECT 569.232 483.608 569.280 483.808 ;
    END
  END t_s[799]
  PIN t_s[800]
    DIRECTION OUTPUT ;
    USE SIGNAL ;
    PORT
      LAYER M5 ;
        RECT 569.376 483.608 569.424 483.808 ;
    END
  END t_s[800]
  PIN t_s[801]
    DIRECTION OUTPUT ;
    USE SIGNAL ;
    PORT
      LAYER M5 ;
        RECT 569.520 483.608 569.568 483.808 ;
    END
  END t_s[801]
  PIN t_s[802]
    DIRECTION OUTPUT ;
    USE SIGNAL ;
    PORT
      LAYER M5 ;
        RECT 569.664 483.608 569.712 483.808 ;
    END
  END t_s[802]
  PIN t_s[803]
    DIRECTION OUTPUT ;
    USE SIGNAL ;
    PORT
      LAYER M5 ;
        RECT 569.808 483.608 569.856 483.808 ;
    END
  END t_s[803]
  PIN t_s[804]
    DIRECTION OUTPUT ;
    USE SIGNAL ;
    PORT
      LAYER M5 ;
        RECT 569.952 483.608 570.000 483.808 ;
    END
  END t_s[804]
  PIN t_s[805]
    DIRECTION OUTPUT ;
    USE SIGNAL ;
    PORT
      LAYER M5 ;
        RECT 570.096 483.608 570.144 483.808 ;
    END
  END t_s[805]
  PIN t_s[806]
    DIRECTION OUTPUT ;
    USE SIGNAL ;
    PORT
      LAYER M5 ;
        RECT 570.240 483.608 570.288 483.808 ;
    END
  END t_s[806]
  PIN t_s[807]
    DIRECTION OUTPUT ;
    USE SIGNAL ;
    PORT
      LAYER M5 ;
        RECT 570.384 483.608 570.432 483.808 ;
    END
  END t_s[807]
  PIN t_s[808]
    DIRECTION OUTPUT ;
    USE SIGNAL ;
    PORT
      LAYER M5 ;
        RECT 570.528 483.608 570.576 483.808 ;
    END
  END t_s[808]
  PIN t_s[809]
    DIRECTION OUTPUT ;
    USE SIGNAL ;
    PORT
      LAYER M5 ;
        RECT 570.672 483.608 570.720 483.808 ;
    END
  END t_s[809]
  PIN t_s[810]
    DIRECTION OUTPUT ;
    USE SIGNAL ;
    PORT
      LAYER M5 ;
        RECT 570.816 483.608 570.864 483.808 ;
    END
  END t_s[810]
  PIN t_s[811]
    DIRECTION OUTPUT ;
    USE SIGNAL ;
    PORT
      LAYER M5 ;
        RECT 570.960 483.608 571.008 483.808 ;
    END
  END t_s[811]
  PIN t_s[812]
    DIRECTION OUTPUT ;
    USE SIGNAL ;
    PORT
      LAYER M5 ;
        RECT 571.104 483.608 571.152 483.808 ;
    END
  END t_s[812]
  PIN t_s[813]
    DIRECTION OUTPUT ;
    USE SIGNAL ;
    PORT
      LAYER M5 ;
        RECT 571.248 483.608 571.296 483.808 ;
    END
  END t_s[813]
  PIN t_s[814]
    DIRECTION OUTPUT ;
    USE SIGNAL ;
    PORT
      LAYER M5 ;
        RECT 571.392 483.608 571.440 483.808 ;
    END
  END t_s[814]
  PIN t_s[815]
    DIRECTION OUTPUT ;
    USE SIGNAL ;
    PORT
      LAYER M5 ;
        RECT 571.536 483.608 571.584 483.808 ;
    END
  END t_s[815]
  PIN t_s[816]
    DIRECTION OUTPUT ;
    USE SIGNAL ;
    PORT
      LAYER M5 ;
        RECT 571.680 483.608 571.728 483.808 ;
    END
  END t_s[816]
  PIN t_s[817]
    DIRECTION OUTPUT ;
    USE SIGNAL ;
    PORT
      LAYER M5 ;
        RECT 571.824 483.608 571.872 483.808 ;
    END
  END t_s[817]
  PIN t_s[818]
    DIRECTION OUTPUT ;
    USE SIGNAL ;
    PORT
      LAYER M5 ;
        RECT 571.968 483.608 572.016 483.808 ;
    END
  END t_s[818]
  PIN t_s[819]
    DIRECTION OUTPUT ;
    USE SIGNAL ;
    PORT
      LAYER M5 ;
        RECT 572.112 483.608 572.160 483.808 ;
    END
  END t_s[819]
  PIN t_s[820]
    DIRECTION OUTPUT ;
    USE SIGNAL ;
    PORT
      LAYER M5 ;
        RECT 572.256 483.608 572.304 483.808 ;
    END
  END t_s[820]
  PIN t_s[821]
    DIRECTION OUTPUT ;
    USE SIGNAL ;
    PORT
      LAYER M5 ;
        RECT 572.400 483.608 572.448 483.808 ;
    END
  END t_s[821]
  PIN t_s[822]
    DIRECTION OUTPUT ;
    USE SIGNAL ;
    PORT
      LAYER M5 ;
        RECT 572.544 483.608 572.592 483.808 ;
    END
  END t_s[822]
  PIN t_s[823]
    DIRECTION OUTPUT ;
    USE SIGNAL ;
    PORT
      LAYER M5 ;
        RECT 572.688 483.608 572.736 483.808 ;
    END
  END t_s[823]
  PIN t_s[824]
    DIRECTION OUTPUT ;
    USE SIGNAL ;
    PORT
      LAYER M5 ;
        RECT 572.832 483.608 572.880 483.808 ;
    END
  END t_s[824]
  PIN t_s[825]
    DIRECTION OUTPUT ;
    USE SIGNAL ;
    PORT
      LAYER M5 ;
        RECT 572.976 483.608 573.024 483.808 ;
    END
  END t_s[825]
  PIN t_s[826]
    DIRECTION OUTPUT ;
    USE SIGNAL ;
    PORT
      LAYER M5 ;
        RECT 573.120 483.608 573.168 483.808 ;
    END
  END t_s[826]
  PIN t_s[827]
    DIRECTION OUTPUT ;
    USE SIGNAL ;
    PORT
      LAYER M5 ;
        RECT 573.264 483.608 573.312 483.808 ;
    END
  END t_s[827]
  PIN t_s[828]
    DIRECTION OUTPUT ;
    USE SIGNAL ;
    PORT
      LAYER M5 ;
        RECT 573.408 483.608 573.456 483.808 ;
    END
  END t_s[828]
  PIN t_s[829]
    DIRECTION OUTPUT ;
    USE SIGNAL ;
    PORT
      LAYER M5 ;
        RECT 573.552 483.608 573.600 483.808 ;
    END
  END t_s[829]
  PIN t_s[830]
    DIRECTION OUTPUT ;
    USE SIGNAL ;
    PORT
      LAYER M5 ;
        RECT 573.696 483.608 573.744 483.808 ;
    END
  END t_s[830]
  PIN t_s[831]
    DIRECTION OUTPUT ;
    USE SIGNAL ;
    PORT
      LAYER M5 ;
        RECT 573.840 483.608 573.888 483.808 ;
    END
  END t_s[831]
  PIN t_s[832]
    DIRECTION OUTPUT ;
    USE SIGNAL ;
    PORT
      LAYER M5 ;
        RECT 573.984 483.608 574.032 483.808 ;
    END
  END t_s[832]
  PIN t_s[833]
    DIRECTION OUTPUT ;
    USE SIGNAL ;
    PORT
      LAYER M5 ;
        RECT 574.128 483.608 574.176 483.808 ;
    END
  END t_s[833]
  PIN t_s[834]
    DIRECTION OUTPUT ;
    USE SIGNAL ;
    PORT
      LAYER M5 ;
        RECT 574.272 483.608 574.320 483.808 ;
    END
  END t_s[834]
  PIN t_s[835]
    DIRECTION OUTPUT ;
    USE SIGNAL ;
    PORT
      LAYER M5 ;
        RECT 574.416 483.608 574.464 483.808 ;
    END
  END t_s[835]
  PIN t_s[836]
    DIRECTION OUTPUT ;
    USE SIGNAL ;
    PORT
      LAYER M5 ;
        RECT 574.560 483.608 574.608 483.808 ;
    END
  END t_s[836]
  PIN t_s[837]
    DIRECTION OUTPUT ;
    USE SIGNAL ;
    PORT
      LAYER M5 ;
        RECT 574.704 483.608 574.752 483.808 ;
    END
  END t_s[837]
  PIN t_s[838]
    DIRECTION OUTPUT ;
    USE SIGNAL ;
    PORT
      LAYER M5 ;
        RECT 574.848 483.608 574.896 483.808 ;
    END
  END t_s[838]
  PIN t_s[839]
    DIRECTION OUTPUT ;
    USE SIGNAL ;
    PORT
      LAYER M5 ;
        RECT 574.992 483.608 575.040 483.808 ;
    END
  END t_s[839]
  PIN t_s[840]
    DIRECTION OUTPUT ;
    USE SIGNAL ;
    PORT
      LAYER M5 ;
        RECT 575.136 483.608 575.184 483.808 ;
    END
  END t_s[840]
  PIN t_s[841]
    DIRECTION OUTPUT ;
    USE SIGNAL ;
    PORT
      LAYER M5 ;
        RECT 575.280 483.608 575.328 483.808 ;
    END
  END t_s[841]
  PIN t_s[842]
    DIRECTION OUTPUT ;
    USE SIGNAL ;
    PORT
      LAYER M5 ;
        RECT 575.424 483.608 575.472 483.808 ;
    END
  END t_s[842]
  PIN t_s[843]
    DIRECTION OUTPUT ;
    USE SIGNAL ;
    PORT
      LAYER M5 ;
        RECT 575.568 483.608 575.616 483.808 ;
    END
  END t_s[843]
  PIN t_s[844]
    DIRECTION OUTPUT ;
    USE SIGNAL ;
    PORT
      LAYER M5 ;
        RECT 575.712 483.608 575.760 483.808 ;
    END
  END t_s[844]
  PIN t_s[845]
    DIRECTION OUTPUT ;
    USE SIGNAL ;
    PORT
      LAYER M5 ;
        RECT 575.856 483.608 575.904 483.808 ;
    END
  END t_s[845]
  PIN t_s[846]
    DIRECTION OUTPUT ;
    USE SIGNAL ;
    PORT
      LAYER M5 ;
        RECT 576.000 483.608 576.048 483.808 ;
    END
  END t_s[846]
  PIN t_s[847]
    DIRECTION OUTPUT ;
    USE SIGNAL ;
    PORT
      LAYER M5 ;
        RECT 576.144 483.608 576.192 483.808 ;
    END
  END t_s[847]
  PIN t_s[848]
    DIRECTION OUTPUT ;
    USE SIGNAL ;
    PORT
      LAYER M5 ;
        RECT 576.288 483.608 576.336 483.808 ;
    END
  END t_s[848]
  PIN t_s[849]
    DIRECTION OUTPUT ;
    USE SIGNAL ;
    PORT
      LAYER M5 ;
        RECT 576.432 483.608 576.480 483.808 ;
    END
  END t_s[849]
  PIN t_s[850]
    DIRECTION OUTPUT ;
    USE SIGNAL ;
    PORT
      LAYER M5 ;
        RECT 576.576 483.608 576.624 483.808 ;
    END
  END t_s[850]
  PIN t_s[851]
    DIRECTION OUTPUT ;
    USE SIGNAL ;
    PORT
      LAYER M5 ;
        RECT 576.720 483.608 576.768 483.808 ;
    END
  END t_s[851]
  PIN t_s[852]
    DIRECTION OUTPUT ;
    USE SIGNAL ;
    PORT
      LAYER M5 ;
        RECT 576.864 483.608 576.912 483.808 ;
    END
  END t_s[852]
  PIN t_s[853]
    DIRECTION OUTPUT ;
    USE SIGNAL ;
    PORT
      LAYER M5 ;
        RECT 577.008 483.608 577.056 483.808 ;
    END
  END t_s[853]
  PIN t_s[854]
    DIRECTION OUTPUT ;
    USE SIGNAL ;
    PORT
      LAYER M5 ;
        RECT 577.152 483.608 577.200 483.808 ;
    END
  END t_s[854]
  PIN t_s[855]
    DIRECTION OUTPUT ;
    USE SIGNAL ;
    PORT
      LAYER M5 ;
        RECT 577.296 483.608 577.344 483.808 ;
    END
  END t_s[855]
  PIN t_s[856]
    DIRECTION OUTPUT ;
    USE SIGNAL ;
    PORT
      LAYER M5 ;
        RECT 577.440 483.608 577.488 483.808 ;
    END
  END t_s[856]
  PIN t_s[857]
    DIRECTION OUTPUT ;
    USE SIGNAL ;
    PORT
      LAYER M5 ;
        RECT 577.584 483.608 577.632 483.808 ;
    END
  END t_s[857]
  PIN t_s[858]
    DIRECTION OUTPUT ;
    USE SIGNAL ;
    PORT
      LAYER M5 ;
        RECT 577.728 483.608 577.776 483.808 ;
    END
  END t_s[858]
  PIN t_s[859]
    DIRECTION OUTPUT ;
    USE SIGNAL ;
    PORT
      LAYER M5 ;
        RECT 577.872 483.608 577.920 483.808 ;
    END
  END t_s[859]
  PIN t_s[860]
    DIRECTION OUTPUT ;
    USE SIGNAL ;
    PORT
      LAYER M5 ;
        RECT 578.016 483.608 578.064 483.808 ;
    END
  END t_s[860]
  PIN t_s[861]
    DIRECTION OUTPUT ;
    USE SIGNAL ;
    PORT
      LAYER M5 ;
        RECT 578.160 483.608 578.208 483.808 ;
    END
  END t_s[861]
  PIN t_s[862]
    DIRECTION OUTPUT ;
    USE SIGNAL ;
    PORT
      LAYER M5 ;
        RECT 578.304 483.608 578.352 483.808 ;
    END
  END t_s[862]
  PIN t_s[863]
    DIRECTION OUTPUT ;
    USE SIGNAL ;
    PORT
      LAYER M5 ;
        RECT 578.448 483.608 578.496 483.808 ;
    END
  END t_s[863]
  PIN t_s[864]
    DIRECTION OUTPUT ;
    USE SIGNAL ;
    PORT
      LAYER M5 ;
        RECT 578.592 483.608 578.640 483.808 ;
    END
  END t_s[864]
  PIN f_c[0]
    DIRECTION INPUT ;
    USE SIGNAL ;
    PORT
      LAYER M5 ;
        RECT 578.736 483.608 578.784 483.808 ;
    END
  END f_c[0]
  PIN f_c[1]
    DIRECTION INPUT ;
    USE SIGNAL ;
    PORT
      LAYER M5 ;
        RECT 578.880 483.608 578.928 483.808 ;
    END
  END f_c[1]
  PIN f_c[2]
    DIRECTION INPUT ;
    USE SIGNAL ;
    PORT
      LAYER M5 ;
        RECT 579.024 483.608 579.072 483.808 ;
    END
  END f_c[2]
  PIN f_c[3]
    DIRECTION INPUT ;
    USE SIGNAL ;
    PORT
      LAYER M5 ;
        RECT 579.168 483.608 579.216 483.808 ;
    END
  END f_c[3]
  PIN f_c[4]
    DIRECTION INPUT ;
    USE SIGNAL ;
    PORT
      LAYER M5 ;
        RECT 579.312 483.608 579.360 483.808 ;
    END
  END f_c[4]
  PIN f_c[5]
    DIRECTION INPUT ;
    USE SIGNAL ;
    PORT
      LAYER M5 ;
        RECT 579.456 483.608 579.504 483.808 ;
    END
  END f_c[5]
  PIN f_c[6]
    DIRECTION INPUT ;
    USE SIGNAL ;
    PORT
      LAYER M5 ;
        RECT 579.600 483.608 579.648 483.808 ;
    END
  END f_c[6]
  PIN f_c[7]
    DIRECTION INPUT ;
    USE SIGNAL ;
    PORT
      LAYER M5 ;
        RECT 579.744 483.608 579.792 483.808 ;
    END
  END f_c[7]
  PIN f_c[8]
    DIRECTION INPUT ;
    USE SIGNAL ;
    PORT
      LAYER M5 ;
        RECT 579.888 483.608 579.936 483.808 ;
    END
  END f_c[8]
  PIN f_c[9]
    DIRECTION INPUT ;
    USE SIGNAL ;
    PORT
      LAYER M5 ;
        RECT 580.032 483.608 580.080 483.808 ;
    END
  END f_c[9]
  PIN f_c[10]
    DIRECTION INPUT ;
    USE SIGNAL ;
    PORT
      LAYER M5 ;
        RECT 580.176 483.608 580.224 483.808 ;
    END
  END f_c[10]
  PIN f_c[11]
    DIRECTION INPUT ;
    USE SIGNAL ;
    PORT
      LAYER M5 ;
        RECT 580.320 483.608 580.368 483.808 ;
    END
  END f_c[11]
  PIN f_c[12]
    DIRECTION INPUT ;
    USE SIGNAL ;
    PORT
      LAYER M5 ;
        RECT 580.464 483.608 580.512 483.808 ;
    END
  END f_c[12]
  PIN f_c[13]
    DIRECTION INPUT ;
    USE SIGNAL ;
    PORT
      LAYER M5 ;
        RECT 580.608 483.608 580.656 483.808 ;
    END
  END f_c[13]
  PIN f_c[14]
    DIRECTION INPUT ;
    USE SIGNAL ;
    PORT
      LAYER M5 ;
        RECT 580.752 483.608 580.800 483.808 ;
    END
  END f_c[14]
  PIN f_c[15]
    DIRECTION INPUT ;
    USE SIGNAL ;
    PORT
      LAYER M5 ;
        RECT 580.896 483.608 580.944 483.808 ;
    END
  END f_c[15]
  PIN f_c[16]
    DIRECTION INPUT ;
    USE SIGNAL ;
    PORT
      LAYER M5 ;
        RECT 581.040 483.608 581.088 483.808 ;
    END
  END f_c[16]
  PIN f_c[17]
    DIRECTION INPUT ;
    USE SIGNAL ;
    PORT
      LAYER M5 ;
        RECT 581.184 483.608 581.232 483.808 ;
    END
  END f_c[17]
  PIN f_c[18]
    DIRECTION INPUT ;
    USE SIGNAL ;
    PORT
      LAYER M5 ;
        RECT 581.328 483.608 581.376 483.808 ;
    END
  END f_c[18]
  PIN f_c[19]
    DIRECTION INPUT ;
    USE SIGNAL ;
    PORT
      LAYER M5 ;
        RECT 581.472 483.608 581.520 483.808 ;
    END
  END f_c[19]
  PIN f_c[20]
    DIRECTION INPUT ;
    USE SIGNAL ;
    PORT
      LAYER M5 ;
        RECT 581.616 483.608 581.664 483.808 ;
    END
  END f_c[20]
  PIN f_c[21]
    DIRECTION INPUT ;
    USE SIGNAL ;
    PORT
      LAYER M5 ;
        RECT 581.760 483.608 581.808 483.808 ;
    END
  END f_c[21]
  PIN f_c[22]
    DIRECTION INPUT ;
    USE SIGNAL ;
    PORT
      LAYER M5 ;
        RECT 581.904 483.608 581.952 483.808 ;
    END
  END f_c[22]
  PIN f_c[23]
    DIRECTION INPUT ;
    USE SIGNAL ;
    PORT
      LAYER M5 ;
        RECT 582.048 483.608 582.096 483.808 ;
    END
  END f_c[23]
  PIN f_c[24]
    DIRECTION INPUT ;
    USE SIGNAL ;
    PORT
      LAYER M5 ;
        RECT 582.192 483.608 582.240 483.808 ;
    END
  END f_c[24]
  PIN f_c[25]
    DIRECTION INPUT ;
    USE SIGNAL ;
    PORT
      LAYER M5 ;
        RECT 582.336 483.608 582.384 483.808 ;
    END
  END f_c[25]
  PIN f_c[26]
    DIRECTION INPUT ;
    USE SIGNAL ;
    PORT
      LAYER M5 ;
        RECT 582.480 483.608 582.528 483.808 ;
    END
  END f_c[26]
  PIN f_c[27]
    DIRECTION INPUT ;
    USE SIGNAL ;
    PORT
      LAYER M5 ;
        RECT 582.624 483.608 582.672 483.808 ;
    END
  END f_c[27]
  PIN f_c[28]
    DIRECTION INPUT ;
    USE SIGNAL ;
    PORT
      LAYER M5 ;
        RECT 582.768 483.608 582.816 483.808 ;
    END
  END f_c[28]
  PIN f_c[29]
    DIRECTION INPUT ;
    USE SIGNAL ;
    PORT
      LAYER M5 ;
        RECT 582.912 483.608 582.960 483.808 ;
    END
  END f_c[29]
  PIN f_c[30]
    DIRECTION INPUT ;
    USE SIGNAL ;
    PORT
      LAYER M5 ;
        RECT 583.056 483.608 583.104 483.808 ;
    END
  END f_c[30]
  PIN f_c[31]
    DIRECTION INPUT ;
    USE SIGNAL ;
    PORT
      LAYER M5 ;
        RECT 583.200 483.608 583.248 483.808 ;
    END
  END f_c[31]
  PIN f_c[32]
    DIRECTION INPUT ;
    USE SIGNAL ;
    PORT
      LAYER M5 ;
        RECT 583.344 483.608 583.392 483.808 ;
    END
  END f_c[32]
  PIN f_c[33]
    DIRECTION INPUT ;
    USE SIGNAL ;
    PORT
      LAYER M5 ;
        RECT 583.488 483.608 583.536 483.808 ;
    END
  END f_c[33]
  PIN f_c[34]
    DIRECTION INPUT ;
    USE SIGNAL ;
    PORT
      LAYER M5 ;
        RECT 583.632 483.608 583.680 483.808 ;
    END
  END f_c[34]
  PIN f_c[35]
    DIRECTION INPUT ;
    USE SIGNAL ;
    PORT
      LAYER M5 ;
        RECT 583.776 483.608 583.824 483.808 ;
    END
  END f_c[35]
  PIN f_c[36]
    DIRECTION INPUT ;
    USE SIGNAL ;
    PORT
      LAYER M5 ;
        RECT 583.920 483.608 583.968 483.808 ;
    END
  END f_c[36]
  PIN f_c[37]
    DIRECTION INPUT ;
    USE SIGNAL ;
    PORT
      LAYER M5 ;
        RECT 584.064 483.608 584.112 483.808 ;
    END
  END f_c[37]
  PIN f_c[38]
    DIRECTION INPUT ;
    USE SIGNAL ;
    PORT
      LAYER M5 ;
        RECT 584.208 483.608 584.256 483.808 ;
    END
  END f_c[38]
  PIN f_c[39]
    DIRECTION INPUT ;
    USE SIGNAL ;
    PORT
      LAYER M5 ;
        RECT 584.352 483.608 584.400 483.808 ;
    END
  END f_c[39]
  PIN f_c[40]
    DIRECTION INPUT ;
    USE SIGNAL ;
    PORT
      LAYER M5 ;
        RECT 584.496 483.608 584.544 483.808 ;
    END
  END f_c[40]
  PIN f_c[41]
    DIRECTION INPUT ;
    USE SIGNAL ;
    PORT
      LAYER M5 ;
        RECT 584.640 483.608 584.688 483.808 ;
    END
  END f_c[41]
  PIN f_c[42]
    DIRECTION INPUT ;
    USE SIGNAL ;
    PORT
      LAYER M5 ;
        RECT 584.784 483.608 584.832 483.808 ;
    END
  END f_c[42]
  PIN f_c[43]
    DIRECTION INPUT ;
    USE SIGNAL ;
    PORT
      LAYER M5 ;
        RECT 584.928 483.608 584.976 483.808 ;
    END
  END f_c[43]
  PIN f_c[44]
    DIRECTION INPUT ;
    USE SIGNAL ;
    PORT
      LAYER M5 ;
        RECT 585.072 483.608 585.120 483.808 ;
    END
  END f_c[44]
  PIN f_c[45]
    DIRECTION INPUT ;
    USE SIGNAL ;
    PORT
      LAYER M5 ;
        RECT 585.216 483.608 585.264 483.808 ;
    END
  END f_c[45]
  PIN f_c[46]
    DIRECTION INPUT ;
    USE SIGNAL ;
    PORT
      LAYER M5 ;
        RECT 585.360 483.608 585.408 483.808 ;
    END
  END f_c[46]
  PIN f_c[47]
    DIRECTION INPUT ;
    USE SIGNAL ;
    PORT
      LAYER M5 ;
        RECT 585.504 483.608 585.552 483.808 ;
    END
  END f_c[47]
  PIN f_c[48]
    DIRECTION INPUT ;
    USE SIGNAL ;
    PORT
      LAYER M5 ;
        RECT 585.648 483.608 585.696 483.808 ;
    END
  END f_c[48]
  PIN f_c[49]
    DIRECTION INPUT ;
    USE SIGNAL ;
    PORT
      LAYER M5 ;
        RECT 585.792 483.608 585.840 483.808 ;
    END
  END f_c[49]
  PIN f_c[50]
    DIRECTION INPUT ;
    USE SIGNAL ;
    PORT
      LAYER M5 ;
        RECT 585.936 483.608 585.984 483.808 ;
    END
  END f_c[50]
  PIN f_c[51]
    DIRECTION INPUT ;
    USE SIGNAL ;
    PORT
      LAYER M5 ;
        RECT 586.080 483.608 586.128 483.808 ;
    END
  END f_c[51]
  PIN f_c[52]
    DIRECTION INPUT ;
    USE SIGNAL ;
    PORT
      LAYER M5 ;
        RECT 586.224 483.608 586.272 483.808 ;
    END
  END f_c[52]
  PIN f_c[53]
    DIRECTION INPUT ;
    USE SIGNAL ;
    PORT
      LAYER M5 ;
        RECT 586.368 483.608 586.416 483.808 ;
    END
  END f_c[53]
  PIN f_c[54]
    DIRECTION INPUT ;
    USE SIGNAL ;
    PORT
      LAYER M5 ;
        RECT 586.512 483.608 586.560 483.808 ;
    END
  END f_c[54]
  PIN f_c[55]
    DIRECTION INPUT ;
    USE SIGNAL ;
    PORT
      LAYER M5 ;
        RECT 586.656 483.608 586.704 483.808 ;
    END
  END f_c[55]
  PIN f_c[56]
    DIRECTION INPUT ;
    USE SIGNAL ;
    PORT
      LAYER M5 ;
        RECT 586.800 483.608 586.848 483.808 ;
    END
  END f_c[56]
  PIN f_c[57]
    DIRECTION INPUT ;
    USE SIGNAL ;
    PORT
      LAYER M5 ;
        RECT 586.944 483.608 586.992 483.808 ;
    END
  END f_c[57]
  PIN f_c[58]
    DIRECTION INPUT ;
    USE SIGNAL ;
    PORT
      LAYER M5 ;
        RECT 587.088 483.608 587.136 483.808 ;
    END
  END f_c[58]
  PIN f_c[59]
    DIRECTION INPUT ;
    USE SIGNAL ;
    PORT
      LAYER M5 ;
        RECT 587.232 483.608 587.280 483.808 ;
    END
  END f_c[59]
  PIN f_c[60]
    DIRECTION INPUT ;
    USE SIGNAL ;
    PORT
      LAYER M5 ;
        RECT 587.376 483.608 587.424 483.808 ;
    END
  END f_c[60]
  PIN f_c[61]
    DIRECTION INPUT ;
    USE SIGNAL ;
    PORT
      LAYER M5 ;
        RECT 587.520 483.608 587.568 483.808 ;
    END
  END f_c[61]
  PIN f_c[62]
    DIRECTION INPUT ;
    USE SIGNAL ;
    PORT
      LAYER M5 ;
        RECT 587.664 483.608 587.712 483.808 ;
    END
  END f_c[62]
  PIN f_c[63]
    DIRECTION INPUT ;
    USE SIGNAL ;
    PORT
      LAYER M5 ;
        RECT 587.808 483.608 587.856 483.808 ;
    END
  END f_c[63]
  PIN f_c[64]
    DIRECTION INPUT ;
    USE SIGNAL ;
    PORT
      LAYER M5 ;
        RECT 587.952 483.608 588.000 483.808 ;
    END
  END f_c[64]
  PIN f_c[65]
    DIRECTION INPUT ;
    USE SIGNAL ;
    PORT
      LAYER M5 ;
        RECT 588.096 483.608 588.144 483.808 ;
    END
  END f_c[65]
  PIN f_cr
    DIRECTION INPUT ;
    USE SIGNAL ;
    PORT
      LAYER M5 ;
        RECT 588.240 483.608 588.288 483.808 ;
    END
  END f_cr
  PIN lane[0]
    DIRECTION INPUT ;
    USE SIGNAL ;
    PORT
      LAYER M5 ;
        RECT 648.000 483.608 648.048 483.808 ;
    END
  END lane[0]
  PIN lane[1]
    DIRECTION INPUT ;
    USE SIGNAL ;
    PORT
      LAYER M5 ;
        RECT 648.384 483.608 648.432 483.808 ;
    END
  END lane[1]
  PIN lane[2]
    DIRECTION INPUT ;
    USE SIGNAL ;
    PORT
      LAYER M5 ;
        RECT 648.768 483.608 648.816 483.808 ;
    END
  END lane[2]
  PIN lane[3]
    DIRECTION INPUT ;
    USE SIGNAL ;
    PORT
      LAYER M5 ;
        RECT 649.152 483.608 649.200 483.808 ;
    END
  END lane[3]
  PIN lane[4]
    DIRECTION INPUT ;
    USE SIGNAL ;
    PORT
      LAYER M5 ;
        RECT 649.536 483.608 649.584 483.808 ;
    END
  END lane[4]
  PIN lane[5]
    DIRECTION INPUT ;
    USE SIGNAL ;
    PORT
      LAYER M5 ;
        RECT 649.920 483.608 649.968 483.808 ;
    END
  END lane[5]
  PIN lane[6]
    DIRECTION INPUT ;
    USE SIGNAL ;
    PORT
      LAYER M5 ;
        RECT 650.304 483.608 650.352 483.808 ;
    END
  END lane[6]
  PIN lane[7]
    DIRECTION INPUT ;
    USE SIGNAL ;
    PORT
      LAYER M5 ;
        RECT 650.688 483.608 650.736 483.808 ;
    END
  END lane[7]
  PIN lane[8]
    DIRECTION INPUT ;
    USE SIGNAL ;
    PORT
      LAYER M5 ;
        RECT 651.072 483.608 651.120 483.808 ;
    END
  END lane[8]
  PIN lane[9]
    DIRECTION INPUT ;
    USE SIGNAL ;
    PORT
      LAYER M5 ;
        RECT 651.456 483.608 651.504 483.808 ;
    END
  END lane[9]
  PIN lane[10]
    DIRECTION INPUT ;
    USE SIGNAL ;
    PORT
      LAYER M5 ;
        RECT 651.840 483.608 651.888 483.808 ;
    END
  END lane[10]
  PIN lane[11]
    DIRECTION INPUT ;
    USE SIGNAL ;
    PORT
      LAYER M5 ;
        RECT 652.224 483.608 652.272 483.808 ;
    END
  END lane[11]
  PIN lane[12]
    DIRECTION INPUT ;
    USE SIGNAL ;
    PORT
      LAYER M5 ;
        RECT 652.608 483.608 652.656 483.808 ;
    END
  END lane[12]
  PIN lane[13]
    DIRECTION INPUT ;
    USE SIGNAL ;
    PORT
      LAYER M5 ;
        RECT 652.992 483.608 653.040 483.808 ;
    END
  END lane[13]
  PIN lane[14]
    DIRECTION INPUT ;
    USE SIGNAL ;
    PORT
      LAYER M5 ;
        RECT 653.376 483.608 653.424 483.808 ;
    END
  END lane[14]
  PIN lane[15]
    DIRECTION INPUT ;
    USE SIGNAL ;
    PORT
      LAYER M5 ;
        RECT 653.760 483.608 653.808 483.808 ;
    END
  END lane[15]
  PIN lane[16]
    DIRECTION INPUT ;
    USE SIGNAL ;
    PORT
      LAYER M5 ;
        RECT 654.144 483.608 654.192 483.808 ;
    END
  END lane[16]
  PIN lane[17]
    DIRECTION INPUT ;
    USE SIGNAL ;
    PORT
      LAYER M5 ;
        RECT 654.528 483.608 654.576 483.808 ;
    END
  END lane[17]
  PIN lane[18]
    DIRECTION INPUT ;
    USE SIGNAL ;
    PORT
      LAYER M5 ;
        RECT 654.912 483.608 654.960 483.808 ;
    END
  END lane[18]
  PIN lane[19]
    DIRECTION INPUT ;
    USE SIGNAL ;
    PORT
      LAYER M5 ;
        RECT 655.296 483.608 655.344 483.808 ;
    END
  END lane[19]
  PIN lane[20]
    DIRECTION INPUT ;
    USE SIGNAL ;
    PORT
      LAYER M5 ;
        RECT 655.680 483.608 655.728 483.808 ;
    END
  END lane[20]
  PIN lane[21]
    DIRECTION INPUT ;
    USE SIGNAL ;
    PORT
      LAYER M5 ;
        RECT 656.064 483.608 656.112 483.808 ;
    END
  END lane[21]
  PIN lane[22]
    DIRECTION INPUT ;
    USE SIGNAL ;
    PORT
      LAYER M5 ;
        RECT 656.448 483.608 656.496 483.808 ;
    END
  END lane[22]
  PIN lane[23]
    DIRECTION INPUT ;
    USE SIGNAL ;
    PORT
      LAYER M5 ;
        RECT 656.832 483.608 656.880 483.808 ;
    END
  END lane[23]
  PIN lane[24]
    DIRECTION INPUT ;
    USE SIGNAL ;
    PORT
      LAYER M5 ;
        RECT 657.216 483.608 657.264 483.808 ;
    END
  END lane[24]
  PIN lane[25]
    DIRECTION INPUT ;
    USE SIGNAL ;
    PORT
      LAYER M5 ;
        RECT 657.600 483.608 657.648 483.808 ;
    END
  END lane[25]
  PIN lane[26]
    DIRECTION INPUT ;
    USE SIGNAL ;
    PORT
      LAYER M5 ;
        RECT 657.984 483.608 658.032 483.808 ;
    END
  END lane[26]
  PIN lane[27]
    DIRECTION INPUT ;
    USE SIGNAL ;
    PORT
      LAYER M5 ;
        RECT 658.368 483.608 658.416 483.808 ;
    END
  END lane[27]
  PIN lane[28]
    DIRECTION INPUT ;
    USE SIGNAL ;
    PORT
      LAYER M5 ;
        RECT 658.752 483.608 658.800 483.808 ;
    END
  END lane[28]
  PIN lane[29]
    DIRECTION INPUT ;
    USE SIGNAL ;
    PORT
      LAYER M5 ;
        RECT 659.136 483.608 659.184 483.808 ;
    END
  END lane[29]
  PIN lane[30]
    DIRECTION INPUT ;
    USE SIGNAL ;
    PORT
      LAYER M5 ;
        RECT 659.520 483.608 659.568 483.808 ;
    END
  END lane[30]
  PIN lane[31]
    DIRECTION INPUT ;
    USE SIGNAL ;
    PORT
      LAYER M5 ;
        RECT 659.904 483.608 659.952 483.808 ;
    END
  END lane[31]
  PIN lane[32]
    DIRECTION INPUT ;
    USE SIGNAL ;
    PORT
      LAYER M5 ;
        RECT 660.288 483.608 660.336 483.808 ;
    END
  END lane[32]
  PIN lane[33]
    DIRECTION INPUT ;
    USE SIGNAL ;
    PORT
      LAYER M5 ;
        RECT 660.672 483.608 660.720 483.808 ;
    END
  END lane[33]
  PIN lane[34]
    DIRECTION INPUT ;
    USE SIGNAL ;
    PORT
      LAYER M5 ;
        RECT 661.056 483.608 661.104 483.808 ;
    END
  END lane[34]
  PIN lane[35]
    DIRECTION INPUT ;
    USE SIGNAL ;
    PORT
      LAYER M5 ;
        RECT 661.440 483.608 661.488 483.808 ;
    END
  END lane[35]
  PIN lane[36]
    DIRECTION INPUT ;
    USE SIGNAL ;
    PORT
      LAYER M5 ;
        RECT 661.824 483.608 661.872 483.808 ;
    END
  END lane[36]
  PIN lane[37]
    DIRECTION INPUT ;
    USE SIGNAL ;
    PORT
      LAYER M5 ;
        RECT 662.208 483.608 662.256 483.808 ;
    END
  END lane[37]
  PIN lane[38]
    DIRECTION INPUT ;
    USE SIGNAL ;
    PORT
      LAYER M5 ;
        RECT 662.592 483.608 662.640 483.808 ;
    END
  END lane[38]
  PIN lane[39]
    DIRECTION INPUT ;
    USE SIGNAL ;
    PORT
      LAYER M5 ;
        RECT 662.976 483.608 663.024 483.808 ;
    END
  END lane[39]
  PIN lane[40]
    DIRECTION INPUT ;
    USE SIGNAL ;
    PORT
      LAYER M5 ;
        RECT 663.360 483.608 663.408 483.808 ;
    END
  END lane[40]
  PIN lane[41]
    DIRECTION INPUT ;
    USE SIGNAL ;
    PORT
      LAYER M5 ;
        RECT 663.744 483.608 663.792 483.808 ;
    END
  END lane[41]
  PIN lane[42]
    DIRECTION INPUT ;
    USE SIGNAL ;
    PORT
      LAYER M5 ;
        RECT 664.128 483.608 664.176 483.808 ;
    END
  END lane[42]
  PIN lane[43]
    DIRECTION INPUT ;
    USE SIGNAL ;
    PORT
      LAYER M5 ;
        RECT 664.512 483.608 664.560 483.808 ;
    END
  END lane[43]
  PIN lane[44]
    DIRECTION INPUT ;
    USE SIGNAL ;
    PORT
      LAYER M5 ;
        RECT 664.896 483.608 664.944 483.808 ;
    END
  END lane[44]
  PIN lane[45]
    DIRECTION INPUT ;
    USE SIGNAL ;
    PORT
      LAYER M5 ;
        RECT 665.280 483.608 665.328 483.808 ;
    END
  END lane[45]
  PIN lane[46]
    DIRECTION INPUT ;
    USE SIGNAL ;
    PORT
      LAYER M5 ;
        RECT 665.664 483.608 665.712 483.808 ;
    END
  END lane[46]
  PIN lane[47]
    DIRECTION INPUT ;
    USE SIGNAL ;
    PORT
      LAYER M5 ;
        RECT 666.048 483.608 666.096 483.808 ;
    END
  END lane[47]
  PIN lane[48]
    DIRECTION INPUT ;
    USE SIGNAL ;
    PORT
      LAYER M5 ;
        RECT 666.432 483.608 666.480 483.808 ;
    END
  END lane[48]
  PIN lane[49]
    DIRECTION INPUT ;
    USE SIGNAL ;
    PORT
      LAYER M5 ;
        RECT 666.816 483.608 666.864 483.808 ;
    END
  END lane[49]
  PIN lane[50]
    DIRECTION INPUT ;
    USE SIGNAL ;
    PORT
      LAYER M5 ;
        RECT 667.200 483.608 667.248 483.808 ;
    END
  END lane[50]
  PIN lane[51]
    DIRECTION INPUT ;
    USE SIGNAL ;
    PORT
      LAYER M5 ;
        RECT 667.584 483.608 667.632 483.808 ;
    END
  END lane[51]
  PIN lane[52]
    DIRECTION INPUT ;
    USE SIGNAL ;
    PORT
      LAYER M5 ;
        RECT 667.968 483.608 668.016 483.808 ;
    END
  END lane[52]
  PIN lane[53]
    DIRECTION INPUT ;
    USE SIGNAL ;
    PORT
      LAYER M5 ;
        RECT 668.352 483.608 668.400 483.808 ;
    END
  END lane[53]
  PIN lane[54]
    DIRECTION INPUT ;
    USE SIGNAL ;
    PORT
      LAYER M5 ;
        RECT 668.736 483.608 668.784 483.808 ;
    END
  END lane[54]
  PIN lane[55]
    DIRECTION INPUT ;
    USE SIGNAL ;
    PORT
      LAYER M5 ;
        RECT 669.120 483.608 669.168 483.808 ;
    END
  END lane[55]
  PIN lane[56]
    DIRECTION INPUT ;
    USE SIGNAL ;
    PORT
      LAYER M5 ;
        RECT 669.504 483.608 669.552 483.808 ;
    END
  END lane[56]
  PIN lane[57]
    DIRECTION INPUT ;
    USE SIGNAL ;
    PORT
      LAYER M5 ;
        RECT 669.888 483.608 669.936 483.808 ;
    END
  END lane[57]
  PIN lane[58]
    DIRECTION INPUT ;
    USE SIGNAL ;
    PORT
      LAYER M5 ;
        RECT 670.272 483.608 670.320 483.808 ;
    END
  END lane[58]
  PIN lane[59]
    DIRECTION INPUT ;
    USE SIGNAL ;
    PORT
      LAYER M5 ;
        RECT 670.656 483.608 670.704 483.808 ;
    END
  END lane[59]
  PIN lane[60]
    DIRECTION INPUT ;
    USE SIGNAL ;
    PORT
      LAYER M5 ;
        RECT 671.040 483.608 671.088 483.808 ;
    END
  END lane[60]
  PIN lane[61]
    DIRECTION INPUT ;
    USE SIGNAL ;
    PORT
      LAYER M5 ;
        RECT 671.424 483.608 671.472 483.808 ;
    END
  END lane[61]
  PIN lane[62]
    DIRECTION INPUT ;
    USE SIGNAL ;
    PORT
      LAYER M5 ;
        RECT 671.808 483.608 671.856 483.808 ;
    END
  END lane[62]
  PIN lane[63]
    DIRECTION INPUT ;
    USE SIGNAL ;
    PORT
      LAYER M5 ;
        RECT 672.192 483.608 672.240 483.808 ;
    END
  END lane[63]
  PIN lane[64]
    DIRECTION INPUT ;
    USE SIGNAL ;
    PORT
      LAYER M5 ;
        RECT 672.576 483.608 672.624 483.808 ;
    END
  END lane[64]
  PIN lane[65]
    DIRECTION INPUT ;
    USE SIGNAL ;
    PORT
      LAYER M5 ;
        RECT 672.960 483.608 673.008 483.808 ;
    END
  END lane[65]
  PIN lane[66]
    DIRECTION INPUT ;
    USE SIGNAL ;
    PORT
      LAYER M5 ;
        RECT 673.344 483.608 673.392 483.808 ;
    END
  END lane[66]
  PIN lane[67]
    DIRECTION INPUT ;
    USE SIGNAL ;
    PORT
      LAYER M5 ;
        RECT 673.728 483.608 673.776 483.808 ;
    END
  END lane[67]
  PIN lane[68]
    DIRECTION INPUT ;
    USE SIGNAL ;
    PORT
      LAYER M5 ;
        RECT 674.112 483.608 674.160 483.808 ;
    END
  END lane[68]
  PIN lane[69]
    DIRECTION INPUT ;
    USE SIGNAL ;
    PORT
      LAYER M5 ;
        RECT 674.496 483.608 674.544 483.808 ;
    END
  END lane[69]
  PIN lane[70]
    DIRECTION INPUT ;
    USE SIGNAL ;
    PORT
      LAYER M5 ;
        RECT 674.880 483.608 674.928 483.808 ;
    END
  END lane[70]
  PIN lane[71]
    DIRECTION INPUT ;
    USE SIGNAL ;
    PORT
      LAYER M5 ;
        RECT 675.264 483.608 675.312 483.808 ;
    END
  END lane[71]
  PIN lane[72]
    DIRECTION INPUT ;
    USE SIGNAL ;
    PORT
      LAYER M5 ;
        RECT 675.648 483.608 675.696 483.808 ;
    END
  END lane[72]
  PIN lane[73]
    DIRECTION INPUT ;
    USE SIGNAL ;
    PORT
      LAYER M5 ;
        RECT 676.032 483.608 676.080 483.808 ;
    END
  END lane[73]
  PIN lane[74]
    DIRECTION INPUT ;
    USE SIGNAL ;
    PORT
      LAYER M5 ;
        RECT 676.416 483.608 676.464 483.808 ;
    END
  END lane[74]
  PIN lane[75]
    DIRECTION INPUT ;
    USE SIGNAL ;
    PORT
      LAYER M5 ;
        RECT 676.800 483.608 676.848 483.808 ;
    END
  END lane[75]
  PIN lane[76]
    DIRECTION INPUT ;
    USE SIGNAL ;
    PORT
      LAYER M5 ;
        RECT 677.184 483.608 677.232 483.808 ;
    END
  END lane[76]
  PIN lane[77]
    DIRECTION INPUT ;
    USE SIGNAL ;
    PORT
      LAYER M5 ;
        RECT 677.568 483.608 677.616 483.808 ;
    END
  END lane[77]
  PIN lane[78]
    DIRECTION INPUT ;
    USE SIGNAL ;
    PORT
      LAYER M5 ;
        RECT 677.952 483.608 678.000 483.808 ;
    END
  END lane[78]
  PIN lane[79]
    DIRECTION INPUT ;
    USE SIGNAL ;
    PORT
      LAYER M5 ;
        RECT 678.336 483.608 678.384 483.808 ;
    END
  END lane[79]
  PIN lane[80]
    DIRECTION INPUT ;
    USE SIGNAL ;
    PORT
      LAYER M5 ;
        RECT 678.720 483.608 678.768 483.808 ;
    END
  END lane[80]
  PIN lane[81]
    DIRECTION INPUT ;
    USE SIGNAL ;
    PORT
      LAYER M5 ;
        RECT 679.104 483.608 679.152 483.808 ;
    END
  END lane[81]
  PIN lane[82]
    DIRECTION INPUT ;
    USE SIGNAL ;
    PORT
      LAYER M5 ;
        RECT 679.488 483.608 679.536 483.808 ;
    END
  END lane[82]
  PIN lane[83]
    DIRECTION INPUT ;
    USE SIGNAL ;
    PORT
      LAYER M5 ;
        RECT 679.872 483.608 679.920 483.808 ;
    END
  END lane[83]
  PIN lane[84]
    DIRECTION INPUT ;
    USE SIGNAL ;
    PORT
      LAYER M5 ;
        RECT 680.256 483.608 680.304 483.808 ;
    END
  END lane[84]
  PIN lane[85]
    DIRECTION INPUT ;
    USE SIGNAL ;
    PORT
      LAYER M5 ;
        RECT 680.640 483.608 680.688 483.808 ;
    END
  END lane[85]
  PIN lane[86]
    DIRECTION INPUT ;
    USE SIGNAL ;
    PORT
      LAYER M5 ;
        RECT 681.024 483.608 681.072 483.808 ;
    END
  END lane[86]
  PIN lane[87]
    DIRECTION INPUT ;
    USE SIGNAL ;
    PORT
      LAYER M5 ;
        RECT 681.408 483.608 681.456 483.808 ;
    END
  END lane[87]
  PIN lane[88]
    DIRECTION INPUT ;
    USE SIGNAL ;
    PORT
      LAYER M5 ;
        RECT 681.792 483.608 681.840 483.808 ;
    END
  END lane[88]
  PIN lane[89]
    DIRECTION INPUT ;
    USE SIGNAL ;
    PORT
      LAYER M5 ;
        RECT 682.176 483.608 682.224 483.808 ;
    END
  END lane[89]
  PIN lane[90]
    DIRECTION INPUT ;
    USE SIGNAL ;
    PORT
      LAYER M5 ;
        RECT 682.560 483.608 682.608 483.808 ;
    END
  END lane[90]
  PIN lane[91]
    DIRECTION INPUT ;
    USE SIGNAL ;
    PORT
      LAYER M5 ;
        RECT 682.944 483.608 682.992 483.808 ;
    END
  END lane[91]
  PIN lane[92]
    DIRECTION INPUT ;
    USE SIGNAL ;
    PORT
      LAYER M5 ;
        RECT 683.328 483.608 683.376 483.808 ;
    END
  END lane[92]
  PIN lane[93]
    DIRECTION INPUT ;
    USE SIGNAL ;
    PORT
      LAYER M5 ;
        RECT 683.712 483.608 683.760 483.808 ;
    END
  END lane[93]
  PIN lane[94]
    DIRECTION INPUT ;
    USE SIGNAL ;
    PORT
      LAYER M5 ;
        RECT 684.096 483.608 684.144 483.808 ;
    END
  END lane[94]
  PIN lane[95]
    DIRECTION INPUT ;
    USE SIGNAL ;
    PORT
      LAYER M5 ;
        RECT 684.480 483.608 684.528 483.808 ;
    END
  END lane[95]
  PIN lane[96]
    DIRECTION INPUT ;
    USE SIGNAL ;
    PORT
      LAYER M5 ;
        RECT 684.864 483.608 684.912 483.808 ;
    END
  END lane[96]
  PIN lane[97]
    DIRECTION INPUT ;
    USE SIGNAL ;
    PORT
      LAYER M5 ;
        RECT 685.248 483.608 685.296 483.808 ;
    END
  END lane[97]
  PIN lane[98]
    DIRECTION INPUT ;
    USE SIGNAL ;
    PORT
      LAYER M5 ;
        RECT 685.632 483.608 685.680 483.808 ;
    END
  END lane[98]
  PIN lane[99]
    DIRECTION INPUT ;
    USE SIGNAL ;
    PORT
      LAYER M5 ;
        RECT 686.016 483.608 686.064 483.808 ;
    END
  END lane[99]
  PIN lane[100]
    DIRECTION INPUT ;
    USE SIGNAL ;
    PORT
      LAYER M5 ;
        RECT 686.400 483.608 686.448 483.808 ;
    END
  END lane[100]
  PIN lane[101]
    DIRECTION INPUT ;
    USE SIGNAL ;
    PORT
      LAYER M5 ;
        RECT 686.784 483.608 686.832 483.808 ;
    END
  END lane[101]
  PIN lane[102]
    DIRECTION INPUT ;
    USE SIGNAL ;
    PORT
      LAYER M5 ;
        RECT 687.168 483.608 687.216 483.808 ;
    END
  END lane[102]
  PIN lane[103]
    DIRECTION INPUT ;
    USE SIGNAL ;
    PORT
      LAYER M5 ;
        RECT 687.552 483.608 687.600 483.808 ;
    END
  END lane[103]
  PIN lane[104]
    DIRECTION INPUT ;
    USE SIGNAL ;
    PORT
      LAYER M5 ;
        RECT 687.936 483.608 687.984 483.808 ;
    END
  END lane[104]
  PIN lane[105]
    DIRECTION INPUT ;
    USE SIGNAL ;
    PORT
      LAYER M5 ;
        RECT 688.320 483.608 688.368 483.808 ;
    END
  END lane[105]
  PIN lane[106]
    DIRECTION INPUT ;
    USE SIGNAL ;
    PORT
      LAYER M5 ;
        RECT 688.704 483.608 688.752 483.808 ;
    END
  END lane[106]
  PIN lane[107]
    DIRECTION INPUT ;
    USE SIGNAL ;
    PORT
      LAYER M5 ;
        RECT 689.088 483.608 689.136 483.808 ;
    END
  END lane[107]
  PIN lane[108]
    DIRECTION INPUT ;
    USE SIGNAL ;
    PORT
      LAYER M5 ;
        RECT 689.472 483.608 689.520 483.808 ;
    END
  END lane[108]
  PIN lane[109]
    DIRECTION INPUT ;
    USE SIGNAL ;
    PORT
      LAYER M5 ;
        RECT 689.856 483.608 689.904 483.808 ;
    END
  END lane[109]
  PIN lane[110]
    DIRECTION INPUT ;
    USE SIGNAL ;
    PORT
      LAYER M5 ;
        RECT 690.240 483.608 690.288 483.808 ;
    END
  END lane[110]
  PIN lane[111]
    DIRECTION INPUT ;
    USE SIGNAL ;
    PORT
      LAYER M5 ;
        RECT 690.624 483.608 690.672 483.808 ;
    END
  END lane[111]
  PIN lane[112]
    DIRECTION INPUT ;
    USE SIGNAL ;
    PORT
      LAYER M5 ;
        RECT 691.008 483.608 691.056 483.808 ;
    END
  END lane[112]
  PIN lane[113]
    DIRECTION INPUT ;
    USE SIGNAL ;
    PORT
      LAYER M5 ;
        RECT 691.392 483.608 691.440 483.808 ;
    END
  END lane[113]
  PIN lane[114]
    DIRECTION INPUT ;
    USE SIGNAL ;
    PORT
      LAYER M5 ;
        RECT 691.776 483.608 691.824 483.808 ;
    END
  END lane[114]
  PIN lane[115]
    DIRECTION INPUT ;
    USE SIGNAL ;
    PORT
      LAYER M5 ;
        RECT 692.160 483.608 692.208 483.808 ;
    END
  END lane[115]
  PIN lane[116]
    DIRECTION INPUT ;
    USE SIGNAL ;
    PORT
      LAYER M5 ;
        RECT 692.544 483.608 692.592 483.808 ;
    END
  END lane[116]
  PIN lane[117]
    DIRECTION INPUT ;
    USE SIGNAL ;
    PORT
      LAYER M5 ;
        RECT 692.928 483.608 692.976 483.808 ;
    END
  END lane[117]
  PIN lane[118]
    DIRECTION INPUT ;
    USE SIGNAL ;
    PORT
      LAYER M5 ;
        RECT 693.312 483.608 693.360 483.808 ;
    END
  END lane[118]
  PIN lane[119]
    DIRECTION INPUT ;
    USE SIGNAL ;
    PORT
      LAYER M5 ;
        RECT 693.696 483.608 693.744 483.808 ;
    END
  END lane[119]
  PIN lane[120]
    DIRECTION INPUT ;
    USE SIGNAL ;
    PORT
      LAYER M5 ;
        RECT 694.080 483.608 694.128 483.808 ;
    END
  END lane[120]
  PIN lane[121]
    DIRECTION INPUT ;
    USE SIGNAL ;
    PORT
      LAYER M5 ;
        RECT 694.464 483.608 694.512 483.808 ;
    END
  END lane[121]
  PIN lane[122]
    DIRECTION INPUT ;
    USE SIGNAL ;
    PORT
      LAYER M5 ;
        RECT 694.848 483.608 694.896 483.808 ;
    END
  END lane[122]
  PIN lane[123]
    DIRECTION INPUT ;
    USE SIGNAL ;
    PORT
      LAYER M5 ;
        RECT 695.232 483.608 695.280 483.808 ;
    END
  END lane[123]
  PIN lane[124]
    DIRECTION INPUT ;
    USE SIGNAL ;
    PORT
      LAYER M5 ;
        RECT 695.616 483.608 695.664 483.808 ;
    END
  END lane[124]
  PIN lane[125]
    DIRECTION INPUT ;
    USE SIGNAL ;
    PORT
      LAYER M5 ;
        RECT 696.000 483.608 696.048 483.808 ;
    END
  END lane[125]
  PIN lane[126]
    DIRECTION INPUT ;
    USE SIGNAL ;
    PORT
      LAYER M5 ;
        RECT 696.384 483.608 696.432 483.808 ;
    END
  END lane[126]
  PIN lane[127]
    DIRECTION INPUT ;
    USE SIGNAL ;
    PORT
      LAYER M5 ;
        RECT 696.768 483.608 696.816 483.808 ;
    END
  END lane[127]
  PIN lane[128]
    DIRECTION INPUT ;
    USE SIGNAL ;
    PORT
      LAYER M5 ;
        RECT 697.152 483.608 697.200 483.808 ;
    END
  END lane[128]
  PIN lane[129]
    DIRECTION INPUT ;
    USE SIGNAL ;
    PORT
      LAYER M5 ;
        RECT 697.536 483.608 697.584 483.808 ;
    END
  END lane[129]
  PIN lane[130]
    DIRECTION INPUT ;
    USE SIGNAL ;
    PORT
      LAYER M5 ;
        RECT 697.920 483.608 697.968 483.808 ;
    END
  END lane[130]
  PIN lane[131]
    DIRECTION INPUT ;
    USE SIGNAL ;
    PORT
      LAYER M5 ;
        RECT 698.304 483.608 698.352 483.808 ;
    END
  END lane[131]
  PIN lane[132]
    DIRECTION INPUT ;
    USE SIGNAL ;
    PORT
      LAYER M5 ;
        RECT 698.688 483.608 698.736 483.808 ;
    END
  END lane[132]
  PIN lane[133]
    DIRECTION INPUT ;
    USE SIGNAL ;
    PORT
      LAYER M5 ;
        RECT 699.072 483.608 699.120 483.808 ;
    END
  END lane[133]
  PIN lane[134]
    DIRECTION INPUT ;
    USE SIGNAL ;
    PORT
      LAYER M5 ;
        RECT 699.456 483.608 699.504 483.808 ;
    END
  END lane[134]
  PIN lane[135]
    DIRECTION INPUT ;
    USE SIGNAL ;
    PORT
      LAYER M5 ;
        RECT 699.840 483.608 699.888 483.808 ;
    END
  END lane[135]
  PIN lane[136]
    DIRECTION INPUT ;
    USE SIGNAL ;
    PORT
      LAYER M5 ;
        RECT 700.224 483.608 700.272 483.808 ;
    END
  END lane[136]
  PIN lane[137]
    DIRECTION INPUT ;
    USE SIGNAL ;
    PORT
      LAYER M5 ;
        RECT 700.608 483.608 700.656 483.808 ;
    END
  END lane[137]
  PIN lane[138]
    DIRECTION INPUT ;
    USE SIGNAL ;
    PORT
      LAYER M5 ;
        RECT 700.992 483.608 701.040 483.808 ;
    END
  END lane[138]
  PIN lane[139]
    DIRECTION INPUT ;
    USE SIGNAL ;
    PORT
      LAYER M5 ;
        RECT 701.376 483.608 701.424 483.808 ;
    END
  END lane[139]
  PIN lane[140]
    DIRECTION INPUT ;
    USE SIGNAL ;
    PORT
      LAYER M5 ;
        RECT 701.760 483.608 701.808 483.808 ;
    END
  END lane[140]
  PIN lane[141]
    DIRECTION INPUT ;
    USE SIGNAL ;
    PORT
      LAYER M5 ;
        RECT 702.144 483.608 702.192 483.808 ;
    END
  END lane[141]
  PIN lane[142]
    DIRECTION INPUT ;
    USE SIGNAL ;
    PORT
      LAYER M5 ;
        RECT 702.528 483.608 702.576 483.808 ;
    END
  END lane[142]
  PIN lane[143]
    DIRECTION INPUT ;
    USE SIGNAL ;
    PORT
      LAYER M5 ;
        RECT 702.912 483.608 702.960 483.808 ;
    END
  END lane[143]
  PIN lane[144]
    DIRECTION INPUT ;
    USE SIGNAL ;
    PORT
      LAYER M5 ;
        RECT 703.296 483.608 703.344 483.808 ;
    END
  END lane[144]
  PIN lane[145]
    DIRECTION INPUT ;
    USE SIGNAL ;
    PORT
      LAYER M5 ;
        RECT 703.680 483.608 703.728 483.808 ;
    END
  END lane[145]
  PIN lane[146]
    DIRECTION INPUT ;
    USE SIGNAL ;
    PORT
      LAYER M5 ;
        RECT 704.064 483.608 704.112 483.808 ;
    END
  END lane[146]
  PIN lane[147]
    DIRECTION INPUT ;
    USE SIGNAL ;
    PORT
      LAYER M5 ;
        RECT 704.448 483.608 704.496 483.808 ;
    END
  END lane[147]
  PIN lane[148]
    DIRECTION INPUT ;
    USE SIGNAL ;
    PORT
      LAYER M5 ;
        RECT 704.832 483.608 704.880 483.808 ;
    END
  END lane[148]
  PIN lane[149]
    DIRECTION INPUT ;
    USE SIGNAL ;
    PORT
      LAYER M5 ;
        RECT 705.216 483.608 705.264 483.808 ;
    END
  END lane[149]
  PIN lane[150]
    DIRECTION INPUT ;
    USE SIGNAL ;
    PORT
      LAYER M5 ;
        RECT 705.600 483.608 705.648 483.808 ;
    END
  END lane[150]
  PIN lane[151]
    DIRECTION INPUT ;
    USE SIGNAL ;
    PORT
      LAYER M5 ;
        RECT 705.984 483.608 706.032 483.808 ;
    END
  END lane[151]
  PIN lane[152]
    DIRECTION INPUT ;
    USE SIGNAL ;
    PORT
      LAYER M5 ;
        RECT 706.368 483.608 706.416 483.808 ;
    END
  END lane[152]
  PIN lane[153]
    DIRECTION INPUT ;
    USE SIGNAL ;
    PORT
      LAYER M5 ;
        RECT 706.752 483.608 706.800 483.808 ;
    END
  END lane[153]
  PIN lane[154]
    DIRECTION INPUT ;
    USE SIGNAL ;
    PORT
      LAYER M5 ;
        RECT 707.136 483.608 707.184 483.808 ;
    END
  END lane[154]
  PIN lane[155]
    DIRECTION INPUT ;
    USE SIGNAL ;
    PORT
      LAYER M5 ;
        RECT 707.520 483.608 707.568 483.808 ;
    END
  END lane[155]
  PIN lane[156]
    DIRECTION INPUT ;
    USE SIGNAL ;
    PORT
      LAYER M5 ;
        RECT 707.904 483.608 707.952 483.808 ;
    END
  END lane[156]
  PIN lane[157]
    DIRECTION INPUT ;
    USE SIGNAL ;
    PORT
      LAYER M5 ;
        RECT 708.288 483.608 708.336 483.808 ;
    END
  END lane[157]
  PIN lane[158]
    DIRECTION INPUT ;
    USE SIGNAL ;
    PORT
      LAYER M5 ;
        RECT 708.672 483.608 708.720 483.808 ;
    END
  END lane[158]
  PIN lane[159]
    DIRECTION INPUT ;
    USE SIGNAL ;
    PORT
      LAYER M5 ;
        RECT 709.056 483.608 709.104 483.808 ;
    END
  END lane[159]
  PIN lane[160]
    DIRECTION INPUT ;
    USE SIGNAL ;
    PORT
      LAYER M5 ;
        RECT 709.440 483.608 709.488 483.808 ;
    END
  END lane[160]
  PIN lane[161]
    DIRECTION INPUT ;
    USE SIGNAL ;
    PORT
      LAYER M5 ;
        RECT 709.824 483.608 709.872 483.808 ;
    END
  END lane[161]
  PIN lane[162]
    DIRECTION INPUT ;
    USE SIGNAL ;
    PORT
      LAYER M5 ;
        RECT 710.208 483.608 710.256 483.808 ;
    END
  END lane[162]
  PIN lane[163]
    DIRECTION INPUT ;
    USE SIGNAL ;
    PORT
      LAYER M5 ;
        RECT 710.592 483.608 710.640 483.808 ;
    END
  END lane[163]
  PIN lane[164]
    DIRECTION INPUT ;
    USE SIGNAL ;
    PORT
      LAYER M5 ;
        RECT 710.976 483.608 711.024 483.808 ;
    END
  END lane[164]
  PIN lane[165]
    DIRECTION INPUT ;
    USE SIGNAL ;
    PORT
      LAYER M5 ;
        RECT 711.360 483.608 711.408 483.808 ;
    END
  END lane[165]
  PIN lane[166]
    DIRECTION INPUT ;
    USE SIGNAL ;
    PORT
      LAYER M5 ;
        RECT 711.744 483.608 711.792 483.808 ;
    END
  END lane[166]
  PIN lane[167]
    DIRECTION INPUT ;
    USE SIGNAL ;
    PORT
      LAYER M5 ;
        RECT 712.128 483.608 712.176 483.808 ;
    END
  END lane[167]
  PIN lane[168]
    DIRECTION INPUT ;
    USE SIGNAL ;
    PORT
      LAYER M5 ;
        RECT 712.512 483.608 712.560 483.808 ;
    END
  END lane[168]
  PIN lane[169]
    DIRECTION INPUT ;
    USE SIGNAL ;
    PORT
      LAYER M5 ;
        RECT 712.896 483.608 712.944 483.808 ;
    END
  END lane[169]
  PIN lane[170]
    DIRECTION INPUT ;
    USE SIGNAL ;
    PORT
      LAYER M5 ;
        RECT 713.280 483.608 713.328 483.808 ;
    END
  END lane[170]
  PIN lane[171]
    DIRECTION INPUT ;
    USE SIGNAL ;
    PORT
      LAYER M5 ;
        RECT 713.664 483.608 713.712 483.808 ;
    END
  END lane[171]
  PIN lane[172]
    DIRECTION INPUT ;
    USE SIGNAL ;
    PORT
      LAYER M5 ;
        RECT 714.048 483.608 714.096 483.808 ;
    END
  END lane[172]
  PIN lane[173]
    DIRECTION INPUT ;
    USE SIGNAL ;
    PORT
      LAYER M5 ;
        RECT 714.432 483.608 714.480 483.808 ;
    END
  END lane[173]
  PIN lane[174]
    DIRECTION INPUT ;
    USE SIGNAL ;
    PORT
      LAYER M5 ;
        RECT 714.816 483.608 714.864 483.808 ;
    END
  END lane[174]
  PIN lane[175]
    DIRECTION INPUT ;
    USE SIGNAL ;
    PORT
      LAYER M5 ;
        RECT 715.200 483.608 715.248 483.808 ;
    END
  END lane[175]
  PIN lane[176]
    DIRECTION INPUT ;
    USE SIGNAL ;
    PORT
      LAYER M5 ;
        RECT 715.584 483.608 715.632 483.808 ;
    END
  END lane[176]
  PIN lane[177]
    DIRECTION INPUT ;
    USE SIGNAL ;
    PORT
      LAYER M5 ;
        RECT 715.968 483.608 716.016 483.808 ;
    END
  END lane[177]
  PIN lane[178]
    DIRECTION INPUT ;
    USE SIGNAL ;
    PORT
      LAYER M5 ;
        RECT 716.352 483.608 716.400 483.808 ;
    END
  END lane[178]
  PIN lane[179]
    DIRECTION INPUT ;
    USE SIGNAL ;
    PORT
      LAYER M5 ;
        RECT 716.736 483.608 716.784 483.808 ;
    END
  END lane[179]
  PIN lane[180]
    DIRECTION INPUT ;
    USE SIGNAL ;
    PORT
      LAYER M5 ;
        RECT 717.120 483.608 717.168 483.808 ;
    END
  END lane[180]
  PIN lane[181]
    DIRECTION INPUT ;
    USE SIGNAL ;
    PORT
      LAYER M5 ;
        RECT 717.504 483.608 717.552 483.808 ;
    END
  END lane[181]
  PIN lane[182]
    DIRECTION INPUT ;
    USE SIGNAL ;
    PORT
      LAYER M5 ;
        RECT 717.888 483.608 717.936 483.808 ;
    END
  END lane[182]
  PIN lane[183]
    DIRECTION INPUT ;
    USE SIGNAL ;
    PORT
      LAYER M5 ;
        RECT 718.272 483.608 718.320 483.808 ;
    END
  END lane[183]
  PIN lane[184]
    DIRECTION INPUT ;
    USE SIGNAL ;
    PORT
      LAYER M5 ;
        RECT 718.656 483.608 718.704 483.808 ;
    END
  END lane[184]
  PIN lane[185]
    DIRECTION INPUT ;
    USE SIGNAL ;
    PORT
      LAYER M5 ;
        RECT 719.040 483.608 719.088 483.808 ;
    END
  END lane[185]
  PIN lane[186]
    DIRECTION INPUT ;
    USE SIGNAL ;
    PORT
      LAYER M5 ;
        RECT 719.424 483.608 719.472 483.808 ;
    END
  END lane[186]
  PIN lane[187]
    DIRECTION INPUT ;
    USE SIGNAL ;
    PORT
      LAYER M5 ;
        RECT 719.808 483.608 719.856 483.808 ;
    END
  END lane[187]
  PIN lane[188]
    DIRECTION INPUT ;
    USE SIGNAL ;
    PORT
      LAYER M5 ;
        RECT 720.192 483.608 720.240 483.808 ;
    END
  END lane[188]
  PIN lane[189]
    DIRECTION INPUT ;
    USE SIGNAL ;
    PORT
      LAYER M5 ;
        RECT 720.576 483.608 720.624 483.808 ;
    END
  END lane[189]
  PIN lane[190]
    DIRECTION INPUT ;
    USE SIGNAL ;
    PORT
      LAYER M5 ;
        RECT 720.960 483.608 721.008 483.808 ;
    END
  END lane[190]
  PIN lane[191]
    DIRECTION INPUT ;
    USE SIGNAL ;
    PORT
      LAYER M5 ;
        RECT 721.344 483.608 721.392 483.808 ;
    END
  END lane[191]
  PIN lane[192]
    DIRECTION INPUT ;
    USE SIGNAL ;
    PORT
      LAYER M5 ;
        RECT 721.728 483.608 721.776 483.808 ;
    END
  END lane[192]
  PIN lane[193]
    DIRECTION INPUT ;
    USE SIGNAL ;
    PORT
      LAYER M5 ;
        RECT 722.112 483.608 722.160 483.808 ;
    END
  END lane[193]
  PIN lane[194]
    DIRECTION INPUT ;
    USE SIGNAL ;
    PORT
      LAYER M5 ;
        RECT 722.496 483.608 722.544 483.808 ;
    END
  END lane[194]
  PIN lane[195]
    DIRECTION INPUT ;
    USE SIGNAL ;
    PORT
      LAYER M5 ;
        RECT 722.880 483.608 722.928 483.808 ;
    END
  END lane[195]
  PIN lane[196]
    DIRECTION INPUT ;
    USE SIGNAL ;
    PORT
      LAYER M5 ;
        RECT 723.264 483.608 723.312 483.808 ;
    END
  END lane[196]
  PIN lane[197]
    DIRECTION INPUT ;
    USE SIGNAL ;
    PORT
      LAYER M5 ;
        RECT 723.648 483.608 723.696 483.808 ;
    END
  END lane[197]
  PIN lane[198]
    DIRECTION INPUT ;
    USE SIGNAL ;
    PORT
      LAYER M5 ;
        RECT 724.032 483.608 724.080 483.808 ;
    END
  END lane[198]
  PIN lane[199]
    DIRECTION INPUT ;
    USE SIGNAL ;
    PORT
      LAYER M5 ;
        RECT 724.416 483.608 724.464 483.808 ;
    END
  END lane[199]
  PIN lane[200]
    DIRECTION INPUT ;
    USE SIGNAL ;
    PORT
      LAYER M5 ;
        RECT 724.800 483.608 724.848 483.808 ;
    END
  END lane[200]
  PIN lane[201]
    DIRECTION INPUT ;
    USE SIGNAL ;
    PORT
      LAYER M5 ;
        RECT 725.184 483.608 725.232 483.808 ;
    END
  END lane[201]
  PIN lane[202]
    DIRECTION INPUT ;
    USE SIGNAL ;
    PORT
      LAYER M5 ;
        RECT 725.568 483.608 725.616 483.808 ;
    END
  END lane[202]
  PIN lane[203]
    DIRECTION INPUT ;
    USE SIGNAL ;
    PORT
      LAYER M5 ;
        RECT 725.952 483.608 726.000 483.808 ;
    END
  END lane[203]
  PIN lane[204]
    DIRECTION INPUT ;
    USE SIGNAL ;
    PORT
      LAYER M5 ;
        RECT 726.336 483.608 726.384 483.808 ;
    END
  END lane[204]
  PIN lane[205]
    DIRECTION INPUT ;
    USE SIGNAL ;
    PORT
      LAYER M5 ;
        RECT 726.720 483.608 726.768 483.808 ;
    END
  END lane[205]
  PIN lane[206]
    DIRECTION INPUT ;
    USE SIGNAL ;
    PORT
      LAYER M5 ;
        RECT 727.104 483.608 727.152 483.808 ;
    END
  END lane[206]
  PIN lane[207]
    DIRECTION INPUT ;
    USE SIGNAL ;
    PORT
      LAYER M5 ;
        RECT 727.488 483.608 727.536 483.808 ;
    END
  END lane[207]
  PIN lane[208]
    DIRECTION INPUT ;
    USE SIGNAL ;
    PORT
      LAYER M5 ;
        RECT 727.872 483.608 727.920 483.808 ;
    END
  END lane[208]
  PIN lane[209]
    DIRECTION INPUT ;
    USE SIGNAL ;
    PORT
      LAYER M5 ;
        RECT 728.256 483.608 728.304 483.808 ;
    END
  END lane[209]
  PIN lane[210]
    DIRECTION INPUT ;
    USE SIGNAL ;
    PORT
      LAYER M5 ;
        RECT 728.640 483.608 728.688 483.808 ;
    END
  END lane[210]
  PIN lane[211]
    DIRECTION INPUT ;
    USE SIGNAL ;
    PORT
      LAYER M5 ;
        RECT 729.024 483.608 729.072 483.808 ;
    END
  END lane[211]
  PIN lane[212]
    DIRECTION INPUT ;
    USE SIGNAL ;
    PORT
      LAYER M5 ;
        RECT 729.408 483.608 729.456 483.808 ;
    END
  END lane[212]
  PIN lane[213]
    DIRECTION INPUT ;
    USE SIGNAL ;
    PORT
      LAYER M5 ;
        RECT 729.792 483.608 729.840 483.808 ;
    END
  END lane[213]
  PIN lane[214]
    DIRECTION INPUT ;
    USE SIGNAL ;
    PORT
      LAYER M5 ;
        RECT 730.176 483.608 730.224 483.808 ;
    END
  END lane[214]
  PIN lane[215]
    DIRECTION INPUT ;
    USE SIGNAL ;
    PORT
      LAYER M5 ;
        RECT 730.560 483.608 730.608 483.808 ;
    END
  END lane[215]
  PIN lane[216]
    DIRECTION INPUT ;
    USE SIGNAL ;
    PORT
      LAYER M5 ;
        RECT 730.944 483.608 730.992 483.808 ;
    END
  END lane[216]
  PIN lane[217]
    DIRECTION INPUT ;
    USE SIGNAL ;
    PORT
      LAYER M5 ;
        RECT 731.328 483.608 731.376 483.808 ;
    END
  END lane[217]
  PIN lane[218]
    DIRECTION INPUT ;
    USE SIGNAL ;
    PORT
      LAYER M5 ;
        RECT 731.712 483.608 731.760 483.808 ;
    END
  END lane[218]
  PIN lane[219]
    DIRECTION INPUT ;
    USE SIGNAL ;
    PORT
      LAYER M5 ;
        RECT 732.096 483.608 732.144 483.808 ;
    END
  END lane[219]
  PIN lane[220]
    DIRECTION INPUT ;
    USE SIGNAL ;
    PORT
      LAYER M5 ;
        RECT 732.480 483.608 732.528 483.808 ;
    END
  END lane[220]
  PIN lane[221]
    DIRECTION INPUT ;
    USE SIGNAL ;
    PORT
      LAYER M5 ;
        RECT 732.864 483.608 732.912 483.808 ;
    END
  END lane[221]
  PIN lane[222]
    DIRECTION INPUT ;
    USE SIGNAL ;
    PORT
      LAYER M5 ;
        RECT 733.248 483.608 733.296 483.808 ;
    END
  END lane[222]
  PIN lane[223]
    DIRECTION INPUT ;
    USE SIGNAL ;
    PORT
      LAYER M5 ;
        RECT 733.632 483.608 733.680 483.808 ;
    END
  END lane[223]
  PIN lane[224]
    DIRECTION INPUT ;
    USE SIGNAL ;
    PORT
      LAYER M5 ;
        RECT 734.016 483.608 734.064 483.808 ;
    END
  END lane[224]
  PIN lane[225]
    DIRECTION INPUT ;
    USE SIGNAL ;
    PORT
      LAYER M5 ;
        RECT 734.400 483.608 734.448 483.808 ;
    END
  END lane[225]
  PIN lane[226]
    DIRECTION INPUT ;
    USE SIGNAL ;
    PORT
      LAYER M5 ;
        RECT 734.784 483.608 734.832 483.808 ;
    END
  END lane[226]
  PIN lane[227]
    DIRECTION INPUT ;
    USE SIGNAL ;
    PORT
      LAYER M5 ;
        RECT 735.168 483.608 735.216 483.808 ;
    END
  END lane[227]
  PIN lane[228]
    DIRECTION INPUT ;
    USE SIGNAL ;
    PORT
      LAYER M5 ;
        RECT 735.552 483.608 735.600 483.808 ;
    END
  END lane[228]
  PIN lane[229]
    DIRECTION INPUT ;
    USE SIGNAL ;
    PORT
      LAYER M5 ;
        RECT 735.936 483.608 735.984 483.808 ;
    END
  END lane[229]
  PIN lane[230]
    DIRECTION INPUT ;
    USE SIGNAL ;
    PORT
      LAYER M5 ;
        RECT 736.320 483.608 736.368 483.808 ;
    END
  END lane[230]
  PIN lane[231]
    DIRECTION INPUT ;
    USE SIGNAL ;
    PORT
      LAYER M5 ;
        RECT 736.704 483.608 736.752 483.808 ;
    END
  END lane[231]
  PIN lane[232]
    DIRECTION INPUT ;
    USE SIGNAL ;
    PORT
      LAYER M5 ;
        RECT 737.088 483.608 737.136 483.808 ;
    END
  END lane[232]
  PIN lane[233]
    DIRECTION INPUT ;
    USE SIGNAL ;
    PORT
      LAYER M5 ;
        RECT 737.472 483.608 737.520 483.808 ;
    END
  END lane[233]
  PIN lane[234]
    DIRECTION INPUT ;
    USE SIGNAL ;
    PORT
      LAYER M5 ;
        RECT 737.856 483.608 737.904 483.808 ;
    END
  END lane[234]
  PIN lane[235]
    DIRECTION INPUT ;
    USE SIGNAL ;
    PORT
      LAYER M5 ;
        RECT 738.240 483.608 738.288 483.808 ;
    END
  END lane[235]
  PIN lane[236]
    DIRECTION INPUT ;
    USE SIGNAL ;
    PORT
      LAYER M5 ;
        RECT 738.624 483.608 738.672 483.808 ;
    END
  END lane[236]
  PIN lane[237]
    DIRECTION INPUT ;
    USE SIGNAL ;
    PORT
      LAYER M5 ;
        RECT 739.008 483.608 739.056 483.808 ;
    END
  END lane[237]
  PIN lane[238]
    DIRECTION INPUT ;
    USE SIGNAL ;
    PORT
      LAYER M5 ;
        RECT 739.392 483.608 739.440 483.808 ;
    END
  END lane[238]
  PIN lane[239]
    DIRECTION INPUT ;
    USE SIGNAL ;
    PORT
      LAYER M5 ;
        RECT 739.776 483.608 739.824 483.808 ;
    END
  END lane[239]
  PIN lane[240]
    DIRECTION INPUT ;
    USE SIGNAL ;
    PORT
      LAYER M5 ;
        RECT 740.160 483.608 740.208 483.808 ;
    END
  END lane[240]
  PIN lane[241]
    DIRECTION INPUT ;
    USE SIGNAL ;
    PORT
      LAYER M5 ;
        RECT 740.544 483.608 740.592 483.808 ;
    END
  END lane[241]
  PIN lane[242]
    DIRECTION INPUT ;
    USE SIGNAL ;
    PORT
      LAYER M5 ;
        RECT 740.928 483.608 740.976 483.808 ;
    END
  END lane[242]
  PIN lane[243]
    DIRECTION INPUT ;
    USE SIGNAL ;
    PORT
      LAYER M5 ;
        RECT 741.312 483.608 741.360 483.808 ;
    END
  END lane[243]
  PIN lane[244]
    DIRECTION INPUT ;
    USE SIGNAL ;
    PORT
      LAYER M5 ;
        RECT 741.696 483.608 741.744 483.808 ;
    END
  END lane[244]
  PIN lane[245]
    DIRECTION INPUT ;
    USE SIGNAL ;
    PORT
      LAYER M5 ;
        RECT 742.080 483.608 742.128 483.808 ;
    END
  END lane[245]
  PIN lane[246]
    DIRECTION INPUT ;
    USE SIGNAL ;
    PORT
      LAYER M5 ;
        RECT 742.464 483.608 742.512 483.808 ;
    END
  END lane[246]
  PIN lane[247]
    DIRECTION INPUT ;
    USE SIGNAL ;
    PORT
      LAYER M5 ;
        RECT 742.848 483.608 742.896 483.808 ;
    END
  END lane[247]
  PIN lane[248]
    DIRECTION INPUT ;
    USE SIGNAL ;
    PORT
      LAYER M5 ;
        RECT 743.232 483.608 743.280 483.808 ;
    END
  END lane[248]
  PIN lane[249]
    DIRECTION INPUT ;
    USE SIGNAL ;
    PORT
      LAYER M5 ;
        RECT 743.616 483.608 743.664 483.808 ;
    END
  END lane[249]
  PIN lane[250]
    DIRECTION INPUT ;
    USE SIGNAL ;
    PORT
      LAYER M5 ;
        RECT 744.000 483.608 744.048 483.808 ;
    END
  END lane[250]
  PIN lane[251]
    DIRECTION INPUT ;
    USE SIGNAL ;
    PORT
      LAYER M5 ;
        RECT 744.384 483.608 744.432 483.808 ;
    END
  END lane[251]
  PIN lane[252]
    DIRECTION INPUT ;
    USE SIGNAL ;
    PORT
      LAYER M5 ;
        RECT 744.768 483.608 744.816 483.808 ;
    END
  END lane[252]
  PIN lane[253]
    DIRECTION INPUT ;
    USE SIGNAL ;
    PORT
      LAYER M5 ;
        RECT 745.152 483.608 745.200 483.808 ;
    END
  END lane[253]
  PIN lane[254]
    DIRECTION INPUT ;
    USE SIGNAL ;
    PORT
      LAYER M5 ;
        RECT 745.536 483.608 745.584 483.808 ;
    END
  END lane[254]
  PIN lane[255]
    DIRECTION INPUT ;
    USE SIGNAL ;
    PORT
      LAYER M5 ;
        RECT 745.920 483.608 745.968 483.808 ;
    END
  END lane[255]
  PIN lane[256]
    DIRECTION INPUT ;
    USE SIGNAL ;
    PORT
      LAYER M5 ;
        RECT 746.304 483.608 746.352 483.808 ;
    END
  END lane[256]
  PIN lane[257]
    DIRECTION INPUT ;
    USE SIGNAL ;
    PORT
      LAYER M5 ;
        RECT 746.688 483.608 746.736 483.808 ;
    END
  END lane[257]
  PIN lane[258]
    DIRECTION INPUT ;
    USE SIGNAL ;
    PORT
      LAYER M5 ;
        RECT 747.072 483.608 747.120 483.808 ;
    END
  END lane[258]
  PIN lane[259]
    DIRECTION INPUT ;
    USE SIGNAL ;
    PORT
      LAYER M5 ;
        RECT 747.456 483.608 747.504 483.808 ;
    END
  END lane[259]
  PIN lane[260]
    DIRECTION INPUT ;
    USE SIGNAL ;
    PORT
      LAYER M5 ;
        RECT 747.840 483.608 747.888 483.808 ;
    END
  END lane[260]
  PIN lane[261]
    DIRECTION INPUT ;
    USE SIGNAL ;
    PORT
      LAYER M5 ;
        RECT 748.224 483.608 748.272 483.808 ;
    END
  END lane[261]
  PIN lane[262]
    DIRECTION INPUT ;
    USE SIGNAL ;
    PORT
      LAYER M5 ;
        RECT 748.608 483.608 748.656 483.808 ;
    END
  END lane[262]
  PIN lane[263]
    DIRECTION INPUT ;
    USE SIGNAL ;
    PORT
      LAYER M5 ;
        RECT 748.992 483.608 749.040 483.808 ;
    END
  END lane[263]
  PIN lane[264]
    DIRECTION INPUT ;
    USE SIGNAL ;
    PORT
      LAYER M5 ;
        RECT 749.376 483.608 749.424 483.808 ;
    END
  END lane[264]
  PIN lane[265]
    DIRECTION INPUT ;
    USE SIGNAL ;
    PORT
      LAYER M5 ;
        RECT 749.760 483.608 749.808 483.808 ;
    END
  END lane[265]
  PIN lane[266]
    DIRECTION INPUT ;
    USE SIGNAL ;
    PORT
      LAYER M5 ;
        RECT 750.144 483.608 750.192 483.808 ;
    END
  END lane[266]
  PIN lane[267]
    DIRECTION INPUT ;
    USE SIGNAL ;
    PORT
      LAYER M5 ;
        RECT 750.528 483.608 750.576 483.808 ;
    END
  END lane[267]
  PIN lane[268]
    DIRECTION INPUT ;
    USE SIGNAL ;
    PORT
      LAYER M5 ;
        RECT 750.912 483.608 750.960 483.808 ;
    END
  END lane[268]
  PIN lane[269]
    DIRECTION INPUT ;
    USE SIGNAL ;
    PORT
      LAYER M5 ;
        RECT 751.296 483.608 751.344 483.808 ;
    END
  END lane[269]
  PIN lane[270]
    DIRECTION INPUT ;
    USE SIGNAL ;
    PORT
      LAYER M5 ;
        RECT 751.680 483.608 751.728 483.808 ;
    END
  END lane[270]
  PIN lane[271]
    DIRECTION INPUT ;
    USE SIGNAL ;
    PORT
      LAYER M5 ;
        RECT 752.064 483.608 752.112 483.808 ;
    END
  END lane[271]
  PIN lane[272]
    DIRECTION INPUT ;
    USE SIGNAL ;
    PORT
      LAYER M5 ;
        RECT 752.448 483.608 752.496 483.808 ;
    END
  END lane[272]
  PIN lane[273]
    DIRECTION INPUT ;
    USE SIGNAL ;
    PORT
      LAYER M5 ;
        RECT 752.832 483.608 752.880 483.808 ;
    END
  END lane[273]
  PIN lane[274]
    DIRECTION INPUT ;
    USE SIGNAL ;
    PORT
      LAYER M5 ;
        RECT 753.216 483.608 753.264 483.808 ;
    END
  END lane[274]
  PIN lane[275]
    DIRECTION INPUT ;
    USE SIGNAL ;
    PORT
      LAYER M5 ;
        RECT 753.600 483.608 753.648 483.808 ;
    END
  END lane[275]
  PIN lane[276]
    DIRECTION INPUT ;
    USE SIGNAL ;
    PORT
      LAYER M5 ;
        RECT 753.984 483.608 754.032 483.808 ;
    END
  END lane[276]
  PIN lane[277]
    DIRECTION INPUT ;
    USE SIGNAL ;
    PORT
      LAYER M5 ;
        RECT 754.368 483.608 754.416 483.808 ;
    END
  END lane[277]
  PIN lane[278]
    DIRECTION INPUT ;
    USE SIGNAL ;
    PORT
      LAYER M5 ;
        RECT 754.752 483.608 754.800 483.808 ;
    END
  END lane[278]
  PIN lane[279]
    DIRECTION INPUT ;
    USE SIGNAL ;
    PORT
      LAYER M5 ;
        RECT 755.136 483.608 755.184 483.808 ;
    END
  END lane[279]
  PIN lane[280]
    DIRECTION INPUT ;
    USE SIGNAL ;
    PORT
      LAYER M5 ;
        RECT 755.520 483.608 755.568 483.808 ;
    END
  END lane[280]
  PIN lane[281]
    DIRECTION INPUT ;
    USE SIGNAL ;
    PORT
      LAYER M5 ;
        RECT 755.904 483.608 755.952 483.808 ;
    END
  END lane[281]
  PIN lane[282]
    DIRECTION INPUT ;
    USE SIGNAL ;
    PORT
      LAYER M5 ;
        RECT 756.288 483.608 756.336 483.808 ;
    END
  END lane[282]
  PIN lane[283]
    DIRECTION INPUT ;
    USE SIGNAL ;
    PORT
      LAYER M5 ;
        RECT 756.672 483.608 756.720 483.808 ;
    END
  END lane[283]
  PIN lane[284]
    DIRECTION INPUT ;
    USE SIGNAL ;
    PORT
      LAYER M5 ;
        RECT 757.056 483.608 757.104 483.808 ;
    END
  END lane[284]
  PIN lane[285]
    DIRECTION INPUT ;
    USE SIGNAL ;
    PORT
      LAYER M5 ;
        RECT 757.440 483.608 757.488 483.808 ;
    END
  END lane[285]
  PIN lane[286]
    DIRECTION INPUT ;
    USE SIGNAL ;
    PORT
      LAYER M5 ;
        RECT 757.824 483.608 757.872 483.808 ;
    END
  END lane[286]
  PIN lane[287]
    DIRECTION INPUT ;
    USE SIGNAL ;
    PORT
      LAYER M5 ;
        RECT 758.208 483.608 758.256 483.808 ;
    END
  END lane[287]
  PIN lane[288]
    DIRECTION INPUT ;
    USE SIGNAL ;
    PORT
      LAYER M5 ;
        RECT 758.592 483.608 758.640 483.808 ;
    END
  END lane[288]
  PIN lane[289]
    DIRECTION INPUT ;
    USE SIGNAL ;
    PORT
      LAYER M5 ;
        RECT 758.976 483.608 759.024 483.808 ;
    END
  END lane[289]
  PIN lane[290]
    DIRECTION INPUT ;
    USE SIGNAL ;
    PORT
      LAYER M5 ;
        RECT 759.360 483.608 759.408 483.808 ;
    END
  END lane[290]
  PIN lane[291]
    DIRECTION INPUT ;
    USE SIGNAL ;
    PORT
      LAYER M5 ;
        RECT 759.744 483.608 759.792 483.808 ;
    END
  END lane[291]
  PIN lane[292]
    DIRECTION INPUT ;
    USE SIGNAL ;
    PORT
      LAYER M5 ;
        RECT 760.128 483.608 760.176 483.808 ;
    END
  END lane[292]
  PIN lane[293]
    DIRECTION INPUT ;
    USE SIGNAL ;
    PORT
      LAYER M5 ;
        RECT 760.512 483.608 760.560 483.808 ;
    END
  END lane[293]
  PIN lane[294]
    DIRECTION INPUT ;
    USE SIGNAL ;
    PORT
      LAYER M5 ;
        RECT 760.896 483.608 760.944 483.808 ;
    END
  END lane[294]
  PIN lane[295]
    DIRECTION INPUT ;
    USE SIGNAL ;
    PORT
      LAYER M5 ;
        RECT 761.280 483.608 761.328 483.808 ;
    END
  END lane[295]
  PIN lane[296]
    DIRECTION INPUT ;
    USE SIGNAL ;
    PORT
      LAYER M5 ;
        RECT 761.664 483.608 761.712 483.808 ;
    END
  END lane[296]
  PIN lane[297]
    DIRECTION INPUT ;
    USE SIGNAL ;
    PORT
      LAYER M5 ;
        RECT 762.048 483.608 762.096 483.808 ;
    END
  END lane[297]
  PIN lane[298]
    DIRECTION INPUT ;
    USE SIGNAL ;
    PORT
      LAYER M5 ;
        RECT 762.432 483.608 762.480 483.808 ;
    END
  END lane[298]
  PIN lane[299]
    DIRECTION INPUT ;
    USE SIGNAL ;
    PORT
      LAYER M5 ;
        RECT 762.816 483.608 762.864 483.808 ;
    END
  END lane[299]
  PIN lane[300]
    DIRECTION INPUT ;
    USE SIGNAL ;
    PORT
      LAYER M5 ;
        RECT 763.200 483.608 763.248 483.808 ;
    END
  END lane[300]
  PIN lane[301]
    DIRECTION INPUT ;
    USE SIGNAL ;
    PORT
      LAYER M5 ;
        RECT 763.584 483.608 763.632 483.808 ;
    END
  END lane[301]
  PIN lane[302]
    DIRECTION INPUT ;
    USE SIGNAL ;
    PORT
      LAYER M5 ;
        RECT 763.968 483.608 764.016 483.808 ;
    END
  END lane[302]
  PIN lane[303]
    DIRECTION INPUT ;
    USE SIGNAL ;
    PORT
      LAYER M5 ;
        RECT 764.352 483.608 764.400 483.808 ;
    END
  END lane[303]
  PIN lane[304]
    DIRECTION INPUT ;
    USE SIGNAL ;
    PORT
      LAYER M5 ;
        RECT 764.736 483.608 764.784 483.808 ;
    END
  END lane[304]
  PIN lane[305]
    DIRECTION INPUT ;
    USE SIGNAL ;
    PORT
      LAYER M5 ;
        RECT 765.120 483.608 765.168 483.808 ;
    END
  END lane[305]
  PIN lane[306]
    DIRECTION INPUT ;
    USE SIGNAL ;
    PORT
      LAYER M5 ;
        RECT 765.504 483.608 765.552 483.808 ;
    END
  END lane[306]
  PIN lane[307]
    DIRECTION INPUT ;
    USE SIGNAL ;
    PORT
      LAYER M5 ;
        RECT 765.888 483.608 765.936 483.808 ;
    END
  END lane[307]
  PIN lane[308]
    DIRECTION INPUT ;
    USE SIGNAL ;
    PORT
      LAYER M5 ;
        RECT 766.272 483.608 766.320 483.808 ;
    END
  END lane[308]
  PIN lane[309]
    DIRECTION INPUT ;
    USE SIGNAL ;
    PORT
      LAYER M5 ;
        RECT 766.656 483.608 766.704 483.808 ;
    END
  END lane[309]
  PIN lane[310]
    DIRECTION INPUT ;
    USE SIGNAL ;
    PORT
      LAYER M5 ;
        RECT 767.040 483.608 767.088 483.808 ;
    END
  END lane[310]
  PIN lane[311]
    DIRECTION INPUT ;
    USE SIGNAL ;
    PORT
      LAYER M5 ;
        RECT 767.424 483.608 767.472 483.808 ;
    END
  END lane[311]
  PIN lane[312]
    DIRECTION INPUT ;
    USE SIGNAL ;
    PORT
      LAYER M5 ;
        RECT 767.808 483.608 767.856 483.808 ;
    END
  END lane[312]
  PIN lane[313]
    DIRECTION INPUT ;
    USE SIGNAL ;
    PORT
      LAYER M5 ;
        RECT 768.192 483.608 768.240 483.808 ;
    END
  END lane[313]
  PIN lane[314]
    DIRECTION INPUT ;
    USE SIGNAL ;
    PORT
      LAYER M5 ;
        RECT 768.576 483.608 768.624 483.808 ;
    END
  END lane[314]
  PIN lane[315]
    DIRECTION INPUT ;
    USE SIGNAL ;
    PORT
      LAYER M5 ;
        RECT 768.960 483.608 769.008 483.808 ;
    END
  END lane[315]
  PIN lane[316]
    DIRECTION INPUT ;
    USE SIGNAL ;
    PORT
      LAYER M5 ;
        RECT 769.344 483.608 769.392 483.808 ;
    END
  END lane[316]
  PIN lane[317]
    DIRECTION INPUT ;
    USE SIGNAL ;
    PORT
      LAYER M5 ;
        RECT 769.728 483.608 769.776 483.808 ;
    END
  END lane[317]
  PIN lane[318]
    DIRECTION INPUT ;
    USE SIGNAL ;
    PORT
      LAYER M5 ;
        RECT 770.112 483.608 770.160 483.808 ;
    END
  END lane[318]
  PIN lane[319]
    DIRECTION INPUT ;
    USE SIGNAL ;
    PORT
      LAYER M5 ;
        RECT 770.496 483.608 770.544 483.808 ;
    END
  END lane[319]
  PIN lane[320]
    DIRECTION INPUT ;
    USE SIGNAL ;
    PORT
      LAYER M5 ;
        RECT 770.880 483.608 770.928 483.808 ;
    END
  END lane[320]
  PIN lane[321]
    DIRECTION INPUT ;
    USE SIGNAL ;
    PORT
      LAYER M5 ;
        RECT 771.264 483.608 771.312 483.808 ;
    END
  END lane[321]
  PIN lane[322]
    DIRECTION INPUT ;
    USE SIGNAL ;
    PORT
      LAYER M5 ;
        RECT 771.648 483.608 771.696 483.808 ;
    END
  END lane[322]
  PIN lane[323]
    DIRECTION INPUT ;
    USE SIGNAL ;
    PORT
      LAYER M5 ;
        RECT 772.032 483.608 772.080 483.808 ;
    END
  END lane[323]
  PIN lane[324]
    DIRECTION INPUT ;
    USE SIGNAL ;
    PORT
      LAYER M5 ;
        RECT 772.416 483.608 772.464 483.808 ;
    END
  END lane[324]
  PIN lane[325]
    DIRECTION INPUT ;
    USE SIGNAL ;
    PORT
      LAYER M5 ;
        RECT 772.800 483.608 772.848 483.808 ;
    END
  END lane[325]
  PIN lane[326]
    DIRECTION INPUT ;
    USE SIGNAL ;
    PORT
      LAYER M5 ;
        RECT 773.184 483.608 773.232 483.808 ;
    END
  END lane[326]
  PIN lane[327]
    DIRECTION INPUT ;
    USE SIGNAL ;
    PORT
      LAYER M5 ;
        RECT 773.568 483.608 773.616 483.808 ;
    END
  END lane[327]
  PIN lane[328]
    DIRECTION INPUT ;
    USE SIGNAL ;
    PORT
      LAYER M5 ;
        RECT 773.952 483.608 774.000 483.808 ;
    END
  END lane[328]
  PIN lane[329]
    DIRECTION INPUT ;
    USE SIGNAL ;
    PORT
      LAYER M5 ;
        RECT 774.336 483.608 774.384 483.808 ;
    END
  END lane[329]
  PIN lane[330]
    DIRECTION INPUT ;
    USE SIGNAL ;
    PORT
      LAYER M5 ;
        RECT 774.720 483.608 774.768 483.808 ;
    END
  END lane[330]
  PIN lane[331]
    DIRECTION INPUT ;
    USE SIGNAL ;
    PORT
      LAYER M5 ;
        RECT 775.104 483.608 775.152 483.808 ;
    END
  END lane[331]
  PIN lane[332]
    DIRECTION INPUT ;
    USE SIGNAL ;
    PORT
      LAYER M5 ;
        RECT 775.488 483.608 775.536 483.808 ;
    END
  END lane[332]
  PIN lane[333]
    DIRECTION INPUT ;
    USE SIGNAL ;
    PORT
      LAYER M5 ;
        RECT 775.872 483.608 775.920 483.808 ;
    END
  END lane[333]
  PIN lane[334]
    DIRECTION INPUT ;
    USE SIGNAL ;
    PORT
      LAYER M5 ;
        RECT 776.256 483.608 776.304 483.808 ;
    END
  END lane[334]
  PIN lane[335]
    DIRECTION INPUT ;
    USE SIGNAL ;
    PORT
      LAYER M5 ;
        RECT 776.640 483.608 776.688 483.808 ;
    END
  END lane[335]
  PIN lane[336]
    DIRECTION INPUT ;
    USE SIGNAL ;
    PORT
      LAYER M5 ;
        RECT 777.024 483.608 777.072 483.808 ;
    END
  END lane[336]
  PIN lane[337]
    DIRECTION INPUT ;
    USE SIGNAL ;
    PORT
      LAYER M5 ;
        RECT 777.408 483.608 777.456 483.808 ;
    END
  END lane[337]
  PIN lane[338]
    DIRECTION INPUT ;
    USE SIGNAL ;
    PORT
      LAYER M5 ;
        RECT 777.792 483.608 777.840 483.808 ;
    END
  END lane[338]
  PIN lane[339]
    DIRECTION INPUT ;
    USE SIGNAL ;
    PORT
      LAYER M5 ;
        RECT 778.176 483.608 778.224 483.808 ;
    END
  END lane[339]
  PIN lane[340]
    DIRECTION INPUT ;
    USE SIGNAL ;
    PORT
      LAYER M5 ;
        RECT 778.560 483.608 778.608 483.808 ;
    END
  END lane[340]
  PIN lane[341]
    DIRECTION INPUT ;
    USE SIGNAL ;
    PORT
      LAYER M5 ;
        RECT 778.944 483.608 778.992 483.808 ;
    END
  END lane[341]
  PIN lane[342]
    DIRECTION INPUT ;
    USE SIGNAL ;
    PORT
      LAYER M5 ;
        RECT 779.328 483.608 779.376 483.808 ;
    END
  END lane[342]
  PIN lane[343]
    DIRECTION INPUT ;
    USE SIGNAL ;
    PORT
      LAYER M5 ;
        RECT 779.712 483.608 779.760 483.808 ;
    END
  END lane[343]
  PIN lane[344]
    DIRECTION INPUT ;
    USE SIGNAL ;
    PORT
      LAYER M5 ;
        RECT 780.096 483.608 780.144 483.808 ;
    END
  END lane[344]
  PIN lane[345]
    DIRECTION INPUT ;
    USE SIGNAL ;
    PORT
      LAYER M5 ;
        RECT 780.480 483.608 780.528 483.808 ;
    END
  END lane[345]
  PIN lane[346]
    DIRECTION INPUT ;
    USE SIGNAL ;
    PORT
      LAYER M5 ;
        RECT 780.864 483.608 780.912 483.808 ;
    END
  END lane[346]
  PIN lane[347]
    DIRECTION INPUT ;
    USE SIGNAL ;
    PORT
      LAYER M5 ;
        RECT 781.248 483.608 781.296 483.808 ;
    END
  END lane[347]
  PIN lane[348]
    DIRECTION INPUT ;
    USE SIGNAL ;
    PORT
      LAYER M5 ;
        RECT 781.632 483.608 781.680 483.808 ;
    END
  END lane[348]
  PIN lane[349]
    DIRECTION INPUT ;
    USE SIGNAL ;
    PORT
      LAYER M5 ;
        RECT 782.016 483.608 782.064 483.808 ;
    END
  END lane[349]
  PIN lane[350]
    DIRECTION INPUT ;
    USE SIGNAL ;
    PORT
      LAYER M5 ;
        RECT 782.400 483.608 782.448 483.808 ;
    END
  END lane[350]
  PIN lane[351]
    DIRECTION INPUT ;
    USE SIGNAL ;
    PORT
      LAYER M5 ;
        RECT 782.784 483.608 782.832 483.808 ;
    END
  END lane[351]
  PIN lane[352]
    DIRECTION INPUT ;
    USE SIGNAL ;
    PORT
      LAYER M5 ;
        RECT 783.168 483.608 783.216 483.808 ;
    END
  END lane[352]
  PIN lane[353]
    DIRECTION INPUT ;
    USE SIGNAL ;
    PORT
      LAYER M5 ;
        RECT 783.552 483.608 783.600 483.808 ;
    END
  END lane[353]
  PIN lane[354]
    DIRECTION INPUT ;
    USE SIGNAL ;
    PORT
      LAYER M5 ;
        RECT 783.936 483.608 783.984 483.808 ;
    END
  END lane[354]
  PIN lane[355]
    DIRECTION INPUT ;
    USE SIGNAL ;
    PORT
      LAYER M5 ;
        RECT 784.320 483.608 784.368 483.808 ;
    END
  END lane[355]
  PIN lane[356]
    DIRECTION INPUT ;
    USE SIGNAL ;
    PORT
      LAYER M5 ;
        RECT 784.704 483.608 784.752 483.808 ;
    END
  END lane[356]
  PIN lane[357]
    DIRECTION INPUT ;
    USE SIGNAL ;
    PORT
      LAYER M5 ;
        RECT 785.088 483.608 785.136 483.808 ;
    END
  END lane[357]
  PIN lane[358]
    DIRECTION INPUT ;
    USE SIGNAL ;
    PORT
      LAYER M5 ;
        RECT 785.472 483.608 785.520 483.808 ;
    END
  END lane[358]
  PIN lane[359]
    DIRECTION INPUT ;
    USE SIGNAL ;
    PORT
      LAYER M5 ;
        RECT 785.856 483.608 785.904 483.808 ;
    END
  END lane[359]
  PIN lane[360]
    DIRECTION INPUT ;
    USE SIGNAL ;
    PORT
      LAYER M5 ;
        RECT 786.240 483.608 786.288 483.808 ;
    END
  END lane[360]
  PIN lane[361]
    DIRECTION INPUT ;
    USE SIGNAL ;
    PORT
      LAYER M5 ;
        RECT 786.624 483.608 786.672 483.808 ;
    END
  END lane[361]
  PIN lane[362]
    DIRECTION INPUT ;
    USE SIGNAL ;
    PORT
      LAYER M5 ;
        RECT 787.008 483.608 787.056 483.808 ;
    END
  END lane[362]
  PIN lane[363]
    DIRECTION INPUT ;
    USE SIGNAL ;
    PORT
      LAYER M5 ;
        RECT 787.392 483.608 787.440 483.808 ;
    END
  END lane[363]
  PIN lane[364]
    DIRECTION INPUT ;
    USE SIGNAL ;
    PORT
      LAYER M5 ;
        RECT 787.776 483.608 787.824 483.808 ;
    END
  END lane[364]
  PIN lane[365]
    DIRECTION INPUT ;
    USE SIGNAL ;
    PORT
      LAYER M5 ;
        RECT 788.160 483.608 788.208 483.808 ;
    END
  END lane[365]
  PIN lane[366]
    DIRECTION INPUT ;
    USE SIGNAL ;
    PORT
      LAYER M5 ;
        RECT 788.544 483.608 788.592 483.808 ;
    END
  END lane[366]
  PIN lane[367]
    DIRECTION INPUT ;
    USE SIGNAL ;
    PORT
      LAYER M5 ;
        RECT 788.928 483.608 788.976 483.808 ;
    END
  END lane[367]
  PIN lane[368]
    DIRECTION INPUT ;
    USE SIGNAL ;
    PORT
      LAYER M5 ;
        RECT 789.312 483.608 789.360 483.808 ;
    END
  END lane[368]
  PIN lane[369]
    DIRECTION INPUT ;
    USE SIGNAL ;
    PORT
      LAYER M5 ;
        RECT 789.696 483.608 789.744 483.808 ;
    END
  END lane[369]
  PIN lane[370]
    DIRECTION INPUT ;
    USE SIGNAL ;
    PORT
      LAYER M5 ;
        RECT 790.080 483.608 790.128 483.808 ;
    END
  END lane[370]
  PIN lane[371]
    DIRECTION INPUT ;
    USE SIGNAL ;
    PORT
      LAYER M5 ;
        RECT 790.464 483.608 790.512 483.808 ;
    END
  END lane[371]
  PIN lane[372]
    DIRECTION INPUT ;
    USE SIGNAL ;
    PORT
      LAYER M5 ;
        RECT 790.848 483.608 790.896 483.808 ;
    END
  END lane[372]
  PIN lane[373]
    DIRECTION INPUT ;
    USE SIGNAL ;
    PORT
      LAYER M5 ;
        RECT 791.232 483.608 791.280 483.808 ;
    END
  END lane[373]
  PIN lane[374]
    DIRECTION INPUT ;
    USE SIGNAL ;
    PORT
      LAYER M5 ;
        RECT 791.616 483.608 791.664 483.808 ;
    END
  END lane[374]
  PIN lane[375]
    DIRECTION INPUT ;
    USE SIGNAL ;
    PORT
      LAYER M5 ;
        RECT 792.000 483.608 792.048 483.808 ;
    END
  END lane[375]
  PIN lane[376]
    DIRECTION INPUT ;
    USE SIGNAL ;
    PORT
      LAYER M5 ;
        RECT 792.384 483.608 792.432 483.808 ;
    END
  END lane[376]
  PIN lane[377]
    DIRECTION INPUT ;
    USE SIGNAL ;
    PORT
      LAYER M5 ;
        RECT 792.768 483.608 792.816 483.808 ;
    END
  END lane[377]
  PIN lane[378]
    DIRECTION INPUT ;
    USE SIGNAL ;
    PORT
      LAYER M5 ;
        RECT 793.152 483.608 793.200 483.808 ;
    END
  END lane[378]
  PIN lane[379]
    DIRECTION INPUT ;
    USE SIGNAL ;
    PORT
      LAYER M5 ;
        RECT 793.536 483.608 793.584 483.808 ;
    END
  END lane[379]
  PIN lane[380]
    DIRECTION INPUT ;
    USE SIGNAL ;
    PORT
      LAYER M5 ;
        RECT 793.920 483.608 793.968 483.808 ;
    END
  END lane[380]
  PIN lane[381]
    DIRECTION INPUT ;
    USE SIGNAL ;
    PORT
      LAYER M5 ;
        RECT 794.304 483.608 794.352 483.808 ;
    END
  END lane[381]
  PIN lane[382]
    DIRECTION INPUT ;
    USE SIGNAL ;
    PORT
      LAYER M5 ;
        RECT 794.688 483.608 794.736 483.808 ;
    END
  END lane[382]
  PIN lane[383]
    DIRECTION INPUT ;
    USE SIGNAL ;
    PORT
      LAYER M5 ;
        RECT 795.072 483.608 795.120 483.808 ;
    END
  END lane[383]
  PIN lane[384]
    DIRECTION INPUT ;
    USE SIGNAL ;
    PORT
      LAYER M5 ;
        RECT 795.456 483.608 795.504 483.808 ;
    END
  END lane[384]
  PIN lane[385]
    DIRECTION INPUT ;
    USE SIGNAL ;
    PORT
      LAYER M5 ;
        RECT 795.840 483.608 795.888 483.808 ;
    END
  END lane[385]
  PIN lane[386]
    DIRECTION INPUT ;
    USE SIGNAL ;
    PORT
      LAYER M5 ;
        RECT 796.224 483.608 796.272 483.808 ;
    END
  END lane[386]
  PIN lane[387]
    DIRECTION INPUT ;
    USE SIGNAL ;
    PORT
      LAYER M5 ;
        RECT 796.608 483.608 796.656 483.808 ;
    END
  END lane[387]
  PIN lane[388]
    DIRECTION INPUT ;
    USE SIGNAL ;
    PORT
      LAYER M5 ;
        RECT 796.992 483.608 797.040 483.808 ;
    END
  END lane[388]
  PIN lane[389]
    DIRECTION INPUT ;
    USE SIGNAL ;
    PORT
      LAYER M5 ;
        RECT 797.376 483.608 797.424 483.808 ;
    END
  END lane[389]
  PIN lane[390]
    DIRECTION INPUT ;
    USE SIGNAL ;
    PORT
      LAYER M5 ;
        RECT 797.760 483.608 797.808 483.808 ;
    END
  END lane[390]
  PIN lane[391]
    DIRECTION INPUT ;
    USE SIGNAL ;
    PORT
      LAYER M5 ;
        RECT 798.144 483.608 798.192 483.808 ;
    END
  END lane[391]
  PIN lane[392]
    DIRECTION INPUT ;
    USE SIGNAL ;
    PORT
      LAYER M5 ;
        RECT 798.528 483.608 798.576 483.808 ;
    END
  END lane[392]
  PIN lane[393]
    DIRECTION INPUT ;
    USE SIGNAL ;
    PORT
      LAYER M5 ;
        RECT 798.912 483.608 798.960 483.808 ;
    END
  END lane[393]
  PIN lane[394]
    DIRECTION INPUT ;
    USE SIGNAL ;
    PORT
      LAYER M5 ;
        RECT 799.296 483.608 799.344 483.808 ;
    END
  END lane[394]
  PIN lane[395]
    DIRECTION INPUT ;
    USE SIGNAL ;
    PORT
      LAYER M5 ;
        RECT 799.680 483.608 799.728 483.808 ;
    END
  END lane[395]
  PIN lane[396]
    DIRECTION INPUT ;
    USE SIGNAL ;
    PORT
      LAYER M5 ;
        RECT 800.064 483.608 800.112 483.808 ;
    END
  END lane[396]
  PIN lane[397]
    DIRECTION INPUT ;
    USE SIGNAL ;
    PORT
      LAYER M5 ;
        RECT 800.448 483.608 800.496 483.808 ;
    END
  END lane[397]
  PIN lane[398]
    DIRECTION INPUT ;
    USE SIGNAL ;
    PORT
      LAYER M5 ;
        RECT 800.832 483.608 800.880 483.808 ;
    END
  END lane[398]
  PIN lane[399]
    DIRECTION INPUT ;
    USE SIGNAL ;
    PORT
      LAYER M5 ;
        RECT 801.216 483.608 801.264 483.808 ;
    END
  END lane[399]
  PIN lane[400]
    DIRECTION INPUT ;
    USE SIGNAL ;
    PORT
      LAYER M5 ;
        RECT 801.600 483.608 801.648 483.808 ;
    END
  END lane[400]
  PIN lane[401]
    DIRECTION INPUT ;
    USE SIGNAL ;
    PORT
      LAYER M5 ;
        RECT 801.984 483.608 802.032 483.808 ;
    END
  END lane[401]
  PIN lane[402]
    DIRECTION INPUT ;
    USE SIGNAL ;
    PORT
      LAYER M5 ;
        RECT 802.368 483.608 802.416 483.808 ;
    END
  END lane[402]
  PIN lane[403]
    DIRECTION INPUT ;
    USE SIGNAL ;
    PORT
      LAYER M5 ;
        RECT 802.752 483.608 802.800 483.808 ;
    END
  END lane[403]
  PIN lane[404]
    DIRECTION INPUT ;
    USE SIGNAL ;
    PORT
      LAYER M5 ;
        RECT 803.136 483.608 803.184 483.808 ;
    END
  END lane[404]
  PIN lane[405]
    DIRECTION INPUT ;
    USE SIGNAL ;
    PORT
      LAYER M5 ;
        RECT 803.520 483.608 803.568 483.808 ;
    END
  END lane[405]
  PIN lane[406]
    DIRECTION INPUT ;
    USE SIGNAL ;
    PORT
      LAYER M5 ;
        RECT 803.904 483.608 803.952 483.808 ;
    END
  END lane[406]
  PIN lane[407]
    DIRECTION INPUT ;
    USE SIGNAL ;
    PORT
      LAYER M5 ;
        RECT 804.288 483.608 804.336 483.808 ;
    END
  END lane[407]
  PIN lane[408]
    DIRECTION INPUT ;
    USE SIGNAL ;
    PORT
      LAYER M5 ;
        RECT 804.672 483.608 804.720 483.808 ;
    END
  END lane[408]
  PIN lane[409]
    DIRECTION INPUT ;
    USE SIGNAL ;
    PORT
      LAYER M5 ;
        RECT 805.056 483.608 805.104 483.808 ;
    END
  END lane[409]
  PIN lane[410]
    DIRECTION INPUT ;
    USE SIGNAL ;
    PORT
      LAYER M5 ;
        RECT 805.440 483.608 805.488 483.808 ;
    END
  END lane[410]
  PIN lane[411]
    DIRECTION INPUT ;
    USE SIGNAL ;
    PORT
      LAYER M5 ;
        RECT 805.824 483.608 805.872 483.808 ;
    END
  END lane[411]
  PIN lane[412]
    DIRECTION INPUT ;
    USE SIGNAL ;
    PORT
      LAYER M5 ;
        RECT 806.208 483.608 806.256 483.808 ;
    END
  END lane[412]
  PIN lane[413]
    DIRECTION INPUT ;
    USE SIGNAL ;
    PORT
      LAYER M5 ;
        RECT 806.592 483.608 806.640 483.808 ;
    END
  END lane[413]
  PIN lane[414]
    DIRECTION INPUT ;
    USE SIGNAL ;
    PORT
      LAYER M5 ;
        RECT 806.976 483.608 807.024 483.808 ;
    END
  END lane[414]
  PIN lane[415]
    DIRECTION INPUT ;
    USE SIGNAL ;
    PORT
      LAYER M5 ;
        RECT 807.360 483.608 807.408 483.808 ;
    END
  END lane[415]
  PIN lane[416]
    DIRECTION INPUT ;
    USE SIGNAL ;
    PORT
      LAYER M5 ;
        RECT 807.744 483.608 807.792 483.808 ;
    END
  END lane[416]
  PIN lane[417]
    DIRECTION INPUT ;
    USE SIGNAL ;
    PORT
      LAYER M5 ;
        RECT 808.128 483.608 808.176 483.808 ;
    END
  END lane[417]
  PIN lane[418]
    DIRECTION INPUT ;
    USE SIGNAL ;
    PORT
      LAYER M5 ;
        RECT 808.512 483.608 808.560 483.808 ;
    END
  END lane[418]
  PIN lane[419]
    DIRECTION INPUT ;
    USE SIGNAL ;
    PORT
      LAYER M5 ;
        RECT 808.896 483.608 808.944 483.808 ;
    END
  END lane[419]
  PIN lane[420]
    DIRECTION INPUT ;
    USE SIGNAL ;
    PORT
      LAYER M5 ;
        RECT 809.280 483.608 809.328 483.808 ;
    END
  END lane[420]
  PIN lane[421]
    DIRECTION INPUT ;
    USE SIGNAL ;
    PORT
      LAYER M5 ;
        RECT 809.664 483.608 809.712 483.808 ;
    END
  END lane[421]
  PIN lane[422]
    DIRECTION INPUT ;
    USE SIGNAL ;
    PORT
      LAYER M5 ;
        RECT 810.048 483.608 810.096 483.808 ;
    END
  END lane[422]
  PIN lane[423]
    DIRECTION INPUT ;
    USE SIGNAL ;
    PORT
      LAYER M5 ;
        RECT 810.432 483.608 810.480 483.808 ;
    END
  END lane[423]
  PIN lane[424]
    DIRECTION INPUT ;
    USE SIGNAL ;
    PORT
      LAYER M5 ;
        RECT 810.816 483.608 810.864 483.808 ;
    END
  END lane[424]
  PIN lane[425]
    DIRECTION INPUT ;
    USE SIGNAL ;
    PORT
      LAYER M5 ;
        RECT 811.200 483.608 811.248 483.808 ;
    END
  END lane[425]
  PIN lane[426]
    DIRECTION INPUT ;
    USE SIGNAL ;
    PORT
      LAYER M5 ;
        RECT 811.584 483.608 811.632 483.808 ;
    END
  END lane[426]
  PIN lane[427]
    DIRECTION INPUT ;
    USE SIGNAL ;
    PORT
      LAYER M5 ;
        RECT 811.968 483.608 812.016 483.808 ;
    END
  END lane[427]
  PIN lane[428]
    DIRECTION INPUT ;
    USE SIGNAL ;
    PORT
      LAYER M5 ;
        RECT 812.352 483.608 812.400 483.808 ;
    END
  END lane[428]
  PIN lane[429]
    DIRECTION INPUT ;
    USE SIGNAL ;
    PORT
      LAYER M5 ;
        RECT 812.736 483.608 812.784 483.808 ;
    END
  END lane[429]
  PIN lane[430]
    DIRECTION INPUT ;
    USE SIGNAL ;
    PORT
      LAYER M5 ;
        RECT 813.120 483.608 813.168 483.808 ;
    END
  END lane[430]
  PIN lane[431]
    DIRECTION INPUT ;
    USE SIGNAL ;
    PORT
      LAYER M5 ;
        RECT 813.504 483.608 813.552 483.808 ;
    END
  END lane[431]
  PIN lane[432]
    DIRECTION INPUT ;
    USE SIGNAL ;
    PORT
      LAYER M5 ;
        RECT 813.888 483.608 813.936 483.808 ;
    END
  END lane[432]
  PIN lane[433]
    DIRECTION INPUT ;
    USE SIGNAL ;
    PORT
      LAYER M5 ;
        RECT 814.272 483.608 814.320 483.808 ;
    END
  END lane[433]
  PIN lane[434]
    DIRECTION INPUT ;
    USE SIGNAL ;
    PORT
      LAYER M5 ;
        RECT 814.656 483.608 814.704 483.808 ;
    END
  END lane[434]
  PIN lane[435]
    DIRECTION INPUT ;
    USE SIGNAL ;
    PORT
      LAYER M5 ;
        RECT 815.040 483.608 815.088 483.808 ;
    END
  END lane[435]
  PIN lane[436]
    DIRECTION INPUT ;
    USE SIGNAL ;
    PORT
      LAYER M5 ;
        RECT 815.424 483.608 815.472 483.808 ;
    END
  END lane[436]
  PIN lane[437]
    DIRECTION INPUT ;
    USE SIGNAL ;
    PORT
      LAYER M5 ;
        RECT 815.808 483.608 815.856 483.808 ;
    END
  END lane[437]
  PIN lane[438]
    DIRECTION INPUT ;
    USE SIGNAL ;
    PORT
      LAYER M5 ;
        RECT 816.192 483.608 816.240 483.808 ;
    END
  END lane[438]
  PIN lane[439]
    DIRECTION INPUT ;
    USE SIGNAL ;
    PORT
      LAYER M5 ;
        RECT 816.576 483.608 816.624 483.808 ;
    END
  END lane[439]
  PIN lane[440]
    DIRECTION INPUT ;
    USE SIGNAL ;
    PORT
      LAYER M5 ;
        RECT 816.960 483.608 817.008 483.808 ;
    END
  END lane[440]
  PIN lane[441]
    DIRECTION INPUT ;
    USE SIGNAL ;
    PORT
      LAYER M5 ;
        RECT 817.344 483.608 817.392 483.808 ;
    END
  END lane[441]
  PIN lane[442]
    DIRECTION INPUT ;
    USE SIGNAL ;
    PORT
      LAYER M5 ;
        RECT 817.728 483.608 817.776 483.808 ;
    END
  END lane[442]
  PIN lane[443]
    DIRECTION INPUT ;
    USE SIGNAL ;
    PORT
      LAYER M5 ;
        RECT 818.112 483.608 818.160 483.808 ;
    END
  END lane[443]
  PIN lane[444]
    DIRECTION INPUT ;
    USE SIGNAL ;
    PORT
      LAYER M5 ;
        RECT 818.496 483.608 818.544 483.808 ;
    END
  END lane[444]
  PIN lane[445]
    DIRECTION INPUT ;
    USE SIGNAL ;
    PORT
      LAYER M5 ;
        RECT 818.880 483.608 818.928 483.808 ;
    END
  END lane[445]
  PIN lane[446]
    DIRECTION INPUT ;
    USE SIGNAL ;
    PORT
      LAYER M5 ;
        RECT 819.264 483.608 819.312 483.808 ;
    END
  END lane[446]
  PIN lane[447]
    DIRECTION INPUT ;
    USE SIGNAL ;
    PORT
      LAYER M5 ;
        RECT 819.648 483.608 819.696 483.808 ;
    END
  END lane[447]
  PIN lane[448]
    DIRECTION INPUT ;
    USE SIGNAL ;
    PORT
      LAYER M5 ;
        RECT 820.032 483.608 820.080 483.808 ;
    END
  END lane[448]
  PIN lane[449]
    DIRECTION INPUT ;
    USE SIGNAL ;
    PORT
      LAYER M5 ;
        RECT 820.416 483.608 820.464 483.808 ;
    END
  END lane[449]
  PIN lane[450]
    DIRECTION INPUT ;
    USE SIGNAL ;
    PORT
      LAYER M5 ;
        RECT 820.800 483.608 820.848 483.808 ;
    END
  END lane[450]
  PIN lane[451]
    DIRECTION INPUT ;
    USE SIGNAL ;
    PORT
      LAYER M5 ;
        RECT 821.184 483.608 821.232 483.808 ;
    END
  END lane[451]
  PIN lane[452]
    DIRECTION INPUT ;
    USE SIGNAL ;
    PORT
      LAYER M5 ;
        RECT 821.568 483.608 821.616 483.808 ;
    END
  END lane[452]
  PIN lane[453]
    DIRECTION INPUT ;
    USE SIGNAL ;
    PORT
      LAYER M5 ;
        RECT 821.952 483.608 822.000 483.808 ;
    END
  END lane[453]
  PIN lane[454]
    DIRECTION INPUT ;
    USE SIGNAL ;
    PORT
      LAYER M5 ;
        RECT 822.336 483.608 822.384 483.808 ;
    END
  END lane[454]
  PIN lane[455]
    DIRECTION INPUT ;
    USE SIGNAL ;
    PORT
      LAYER M5 ;
        RECT 822.720 483.608 822.768 483.808 ;
    END
  END lane[455]
  PIN lane[456]
    DIRECTION INPUT ;
    USE SIGNAL ;
    PORT
      LAYER M5 ;
        RECT 823.104 483.608 823.152 483.808 ;
    END
  END lane[456]
  PIN lane[457]
    DIRECTION INPUT ;
    USE SIGNAL ;
    PORT
      LAYER M5 ;
        RECT 823.488 483.608 823.536 483.808 ;
    END
  END lane[457]
  PIN lane[458]
    DIRECTION INPUT ;
    USE SIGNAL ;
    PORT
      LAYER M5 ;
        RECT 823.872 483.608 823.920 483.808 ;
    END
  END lane[458]
  PIN lane[459]
    DIRECTION INPUT ;
    USE SIGNAL ;
    PORT
      LAYER M5 ;
        RECT 824.256 483.608 824.304 483.808 ;
    END
  END lane[459]
  PIN lane[460]
    DIRECTION INPUT ;
    USE SIGNAL ;
    PORT
      LAYER M5 ;
        RECT 824.640 483.608 824.688 483.808 ;
    END
  END lane[460]
  PIN lane[461]
    DIRECTION INPUT ;
    USE SIGNAL ;
    PORT
      LAYER M5 ;
        RECT 825.024 483.608 825.072 483.808 ;
    END
  END lane[461]
  PIN lane[462]
    DIRECTION INPUT ;
    USE SIGNAL ;
    PORT
      LAYER M5 ;
        RECT 825.408 483.608 825.456 483.808 ;
    END
  END lane[462]
  PIN lane[463]
    DIRECTION INPUT ;
    USE SIGNAL ;
    PORT
      LAYER M5 ;
        RECT 825.792 483.608 825.840 483.808 ;
    END
  END lane[463]
  PIN lane[464]
    DIRECTION INPUT ;
    USE SIGNAL ;
    PORT
      LAYER M5 ;
        RECT 826.176 483.608 826.224 483.808 ;
    END
  END lane[464]
  PIN lane[465]
    DIRECTION INPUT ;
    USE SIGNAL ;
    PORT
      LAYER M5 ;
        RECT 826.560 483.608 826.608 483.808 ;
    END
  END lane[465]
  PIN lane[466]
    DIRECTION INPUT ;
    USE SIGNAL ;
    PORT
      LAYER M5 ;
        RECT 826.944 483.608 826.992 483.808 ;
    END
  END lane[466]
  PIN lane[467]
    DIRECTION INPUT ;
    USE SIGNAL ;
    PORT
      LAYER M5 ;
        RECT 827.328 483.608 827.376 483.808 ;
    END
  END lane[467]
  PIN lane[468]
    DIRECTION INPUT ;
    USE SIGNAL ;
    PORT
      LAYER M5 ;
        RECT 827.712 483.608 827.760 483.808 ;
    END
  END lane[468]
  PIN lane[469]
    DIRECTION INPUT ;
    USE SIGNAL ;
    PORT
      LAYER M5 ;
        RECT 828.096 483.608 828.144 483.808 ;
    END
  END lane[469]
  PIN lane[470]
    DIRECTION INPUT ;
    USE SIGNAL ;
    PORT
      LAYER M5 ;
        RECT 828.480 483.608 828.528 483.808 ;
    END
  END lane[470]
  PIN lane[471]
    DIRECTION INPUT ;
    USE SIGNAL ;
    PORT
      LAYER M5 ;
        RECT 828.864 483.608 828.912 483.808 ;
    END
  END lane[471]
  PIN lane[472]
    DIRECTION INPUT ;
    USE SIGNAL ;
    PORT
      LAYER M5 ;
        RECT 829.248 483.608 829.296 483.808 ;
    END
  END lane[472]
  PIN lane[473]
    DIRECTION INPUT ;
    USE SIGNAL ;
    PORT
      LAYER M5 ;
        RECT 829.632 483.608 829.680 483.808 ;
    END
  END lane[473]
  PIN lane[474]
    DIRECTION INPUT ;
    USE SIGNAL ;
    PORT
      LAYER M5 ;
        RECT 830.016 483.608 830.064 483.808 ;
    END
  END lane[474]
  PIN lane[475]
    DIRECTION INPUT ;
    USE SIGNAL ;
    PORT
      LAYER M5 ;
        RECT 830.400 483.608 830.448 483.808 ;
    END
  END lane[475]
  PIN lane[476]
    DIRECTION INPUT ;
    USE SIGNAL ;
    PORT
      LAYER M5 ;
        RECT 830.784 483.608 830.832 483.808 ;
    END
  END lane[476]
  PIN lane[477]
    DIRECTION INPUT ;
    USE SIGNAL ;
    PORT
      LAYER M5 ;
        RECT 831.168 483.608 831.216 483.808 ;
    END
  END lane[477]
  PIN lane[478]
    DIRECTION INPUT ;
    USE SIGNAL ;
    PORT
      LAYER M5 ;
        RECT 831.552 483.608 831.600 483.808 ;
    END
  END lane[478]
  PIN lane[479]
    DIRECTION INPUT ;
    USE SIGNAL ;
    PORT
      LAYER M5 ;
        RECT 831.936 483.608 831.984 483.808 ;
    END
  END lane[479]
  PIN lane[480]
    DIRECTION INPUT ;
    USE SIGNAL ;
    PORT
      LAYER M5 ;
        RECT 832.320 483.608 832.368 483.808 ;
    END
  END lane[480]
  PIN lane[481]
    DIRECTION INPUT ;
    USE SIGNAL ;
    PORT
      LAYER M5 ;
        RECT 832.704 483.608 832.752 483.808 ;
    END
  END lane[481]
  PIN lane[482]
    DIRECTION INPUT ;
    USE SIGNAL ;
    PORT
      LAYER M5 ;
        RECT 833.088 483.608 833.136 483.808 ;
    END
  END lane[482]
  PIN lane[483]
    DIRECTION INPUT ;
    USE SIGNAL ;
    PORT
      LAYER M5 ;
        RECT 833.472 483.608 833.520 483.808 ;
    END
  END lane[483]
  PIN lane[484]
    DIRECTION INPUT ;
    USE SIGNAL ;
    PORT
      LAYER M5 ;
        RECT 833.856 483.608 833.904 483.808 ;
    END
  END lane[484]
  PIN lane[485]
    DIRECTION INPUT ;
    USE SIGNAL ;
    PORT
      LAYER M5 ;
        RECT 834.240 483.608 834.288 483.808 ;
    END
  END lane[485]
  PIN lane[486]
    DIRECTION INPUT ;
    USE SIGNAL ;
    PORT
      LAYER M5 ;
        RECT 834.624 483.608 834.672 483.808 ;
    END
  END lane[486]
  PIN lane[487]
    DIRECTION INPUT ;
    USE SIGNAL ;
    PORT
      LAYER M5 ;
        RECT 835.008 483.608 835.056 483.808 ;
    END
  END lane[487]
  PIN lane[488]
    DIRECTION INPUT ;
    USE SIGNAL ;
    PORT
      LAYER M5 ;
        RECT 835.392 483.608 835.440 483.808 ;
    END
  END lane[488]
  PIN lane[489]
    DIRECTION INPUT ;
    USE SIGNAL ;
    PORT
      LAYER M5 ;
        RECT 835.776 483.608 835.824 483.808 ;
    END
  END lane[489]
  PIN lane[490]
    DIRECTION INPUT ;
    USE SIGNAL ;
    PORT
      LAYER M5 ;
        RECT 836.160 483.608 836.208 483.808 ;
    END
  END lane[490]
  PIN lane[491]
    DIRECTION INPUT ;
    USE SIGNAL ;
    PORT
      LAYER M5 ;
        RECT 836.544 483.608 836.592 483.808 ;
    END
  END lane[491]
  PIN lane[492]
    DIRECTION INPUT ;
    USE SIGNAL ;
    PORT
      LAYER M5 ;
        RECT 836.928 483.608 836.976 483.808 ;
    END
  END lane[492]
  PIN lane[493]
    DIRECTION INPUT ;
    USE SIGNAL ;
    PORT
      LAYER M5 ;
        RECT 837.312 483.608 837.360 483.808 ;
    END
  END lane[493]
  PIN lane[494]
    DIRECTION INPUT ;
    USE SIGNAL ;
    PORT
      LAYER M5 ;
        RECT 837.696 483.608 837.744 483.808 ;
    END
  END lane[494]
  PIN lane[495]
    DIRECTION INPUT ;
    USE SIGNAL ;
    PORT
      LAYER M5 ;
        RECT 838.080 483.608 838.128 483.808 ;
    END
  END lane[495]
  PIN lane[496]
    DIRECTION INPUT ;
    USE SIGNAL ;
    PORT
      LAYER M5 ;
        RECT 838.464 483.608 838.512 483.808 ;
    END
  END lane[496]
  PIN lane[497]
    DIRECTION INPUT ;
    USE SIGNAL ;
    PORT
      LAYER M5 ;
        RECT 838.848 483.608 838.896 483.808 ;
    END
  END lane[497]
  PIN lane[498]
    DIRECTION INPUT ;
    USE SIGNAL ;
    PORT
      LAYER M5 ;
        RECT 839.232 483.608 839.280 483.808 ;
    END
  END lane[498]
  PIN lane[499]
    DIRECTION INPUT ;
    USE SIGNAL ;
    PORT
      LAYER M5 ;
        RECT 839.616 483.608 839.664 483.808 ;
    END
  END lane[499]
  PIN lane[500]
    DIRECTION INPUT ;
    USE SIGNAL ;
    PORT
      LAYER M5 ;
        RECT 840.000 483.608 840.048 483.808 ;
    END
  END lane[500]
  PIN lane[501]
    DIRECTION INPUT ;
    USE SIGNAL ;
    PORT
      LAYER M5 ;
        RECT 840.384 483.608 840.432 483.808 ;
    END
  END lane[501]
  PIN lane[502]
    DIRECTION INPUT ;
    USE SIGNAL ;
    PORT
      LAYER M5 ;
        RECT 840.768 483.608 840.816 483.808 ;
    END
  END lane[502]
  PIN lane[503]
    DIRECTION INPUT ;
    USE SIGNAL ;
    PORT
      LAYER M5 ;
        RECT 841.152 483.608 841.200 483.808 ;
    END
  END lane[503]
  PIN lane[504]
    DIRECTION INPUT ;
    USE SIGNAL ;
    PORT
      LAYER M5 ;
        RECT 841.536 483.608 841.584 483.808 ;
    END
  END lane[504]
  PIN lane[505]
    DIRECTION INPUT ;
    USE SIGNAL ;
    PORT
      LAYER M5 ;
        RECT 841.920 483.608 841.968 483.808 ;
    END
  END lane[505]
  PIN lane[506]
    DIRECTION INPUT ;
    USE SIGNAL ;
    PORT
      LAYER M5 ;
        RECT 842.304 483.608 842.352 483.808 ;
    END
  END lane[506]
  PIN lane[507]
    DIRECTION INPUT ;
    USE SIGNAL ;
    PORT
      LAYER M5 ;
        RECT 842.688 483.608 842.736 483.808 ;
    END
  END lane[507]
  PIN lane[508]
    DIRECTION INPUT ;
    USE SIGNAL ;
    PORT
      LAYER M5 ;
        RECT 843.072 483.608 843.120 483.808 ;
    END
  END lane[508]
  PIN lane[509]
    DIRECTION INPUT ;
    USE SIGNAL ;
    PORT
      LAYER M5 ;
        RECT 843.456 483.608 843.504 483.808 ;
    END
  END lane[509]
  PIN lane[510]
    DIRECTION INPUT ;
    USE SIGNAL ;
    PORT
      LAYER M5 ;
        RECT 843.840 483.608 843.888 483.808 ;
    END
  END lane[510]
  PIN lane[511]
    DIRECTION INPUT ;
    USE SIGNAL ;
    PORT
      LAYER M5 ;
        RECT 844.224 483.608 844.272 483.808 ;
    END
  END lane[511]
  PIN lane[512]
    DIRECTION INPUT ;
    USE SIGNAL ;
    PORT
      LAYER M5 ;
        RECT 844.608 483.608 844.656 483.808 ;
    END
  END lane[512]
  PIN lane[513]
    DIRECTION INPUT ;
    USE SIGNAL ;
    PORT
      LAYER M5 ;
        RECT 844.992 483.608 845.040 483.808 ;
    END
  END lane[513]
  PIN lane[514]
    DIRECTION INPUT ;
    USE SIGNAL ;
    PORT
      LAYER M5 ;
        RECT 845.376 483.608 845.424 483.808 ;
    END
  END lane[514]
  PIN ck
    DIRECTION INPUT ;
    USE CLOCK ;
    PORT
      LAYER M5 ;
        RECT 432.000 241.820 432.048 242.020 ;
    END
  END ck
  PIN rst
    DIRECTION INPUT ;
    USE SIGNAL ;
    PORT
      LAYER M5 ;
        RECT 440.640 241.820 440.688 242.020 ;
    END
  END rst
  OBS
    LAYER M1 ;
      RECT 0 0 864.0 483.84 ;
    LAYER M2 ;
      RECT 0 0 864.0 483.84 ;
    LAYER M3 ;
      RECT 0 0 864.0 483.84 ;
    LAYER M4 ;
      RECT 0 0 864.0 483.84 ;
    LAYER M5 ;
      RECT 0 0 864.0 483.84 ;
  END
END dsdv_bksel_q
END LIBRARY
